# Placeholder macro written by tools/chip_assembly/macros.py
# kind: analog_pma; S81 SerDes PMA RX half (modelled analog, ot_s81_pma_bm LAT 4 behaviour)
VERSION 5.7 ;
BUSBITCHARS "[]" ;
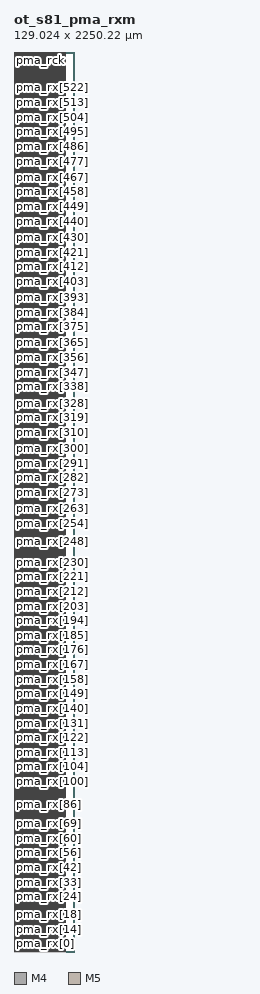
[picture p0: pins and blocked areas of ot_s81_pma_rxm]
MACRO ot_s81_pma_rxm
  FOREIGN ot_s81_pma_rxm 0 0 ;
  SYMMETRY X Y R90 ;
  SIZE 129.024 BY 2250.216 ;
  CLASS BLOCK ;
  PIN pma_rck
    DIRECTION INPUT ;
    USE SIGNAL ;
    SHAPE ABUTMENT ;
    PORT
      LAYER M4 ;
      RECT 0.000 2240.208 0.192 2240.232 ;
    END
  END pma_rck
  PIN pma_rx[0]
    DIRECTION INPUT ;
    USE SIGNAL ;
    SHAPE ABUTMENT ;
    PORT
      LAYER M4 ;
      RECT 0.000 20.496 0.192 20.520 ;
    END
  END pma_rx[0]
  PIN pma_rx[1]
    DIRECTION INPUT ;
    USE SIGNAL ;
    SHAPE ABUTMENT ;
    PORT
      LAYER M4 ;
      RECT 0.000 24.528 0.192 24.552 ;
    END
  END pma_rx[1]
  PIN pma_rx[2]
    DIRECTION INPUT ;
    USE SIGNAL ;
    SHAPE ABUTMENT ;
    PORT
      LAYER M4 ;
      RECT 0.000 28.608 0.192 28.632 ;
    END
  END pma_rx[2]
  PIN pma_rx[3]
    DIRECTION INPUT ;
    USE SIGNAL ;
    SHAPE ABUTMENT ;
    PORT
      LAYER M4 ;
      RECT 0.000 32.640 0.192 32.664 ;
    END
  END pma_rx[3]
  PIN pma_rx[4]
    DIRECTION INPUT ;
    USE SIGNAL ;
    SHAPE ABUTMENT ;
    PORT
      LAYER M4 ;
      RECT 0.000 36.720 0.192 36.744 ;
    END
  END pma_rx[4]
  PIN pma_rx[5]
    DIRECTION INPUT ;
    USE SIGNAL ;
    SHAPE ABUTMENT ;
    PORT
      LAYER M4 ;
      RECT 0.000 40.800 0.192 40.824 ;
    END
  END pma_rx[5]
  PIN pma_rx[6]
    DIRECTION INPUT ;
    USE SIGNAL ;
    SHAPE ABUTMENT ;
    PORT
      LAYER M4 ;
      RECT 0.000 44.832 0.192 44.856 ;
    END
  END pma_rx[6]
  PIN pma_rx[7]
    DIRECTION INPUT ;
    USE SIGNAL ;
    SHAPE ABUTMENT ;
    PORT
      LAYER M4 ;
      RECT 0.000 48.912 0.192 48.936 ;
    END
  END pma_rx[7]
  PIN pma_rx[8]
    DIRECTION INPUT ;
    USE SIGNAL ;
    SHAPE ABUTMENT ;
    PORT
      LAYER M4 ;
      RECT 0.000 52.944 0.192 52.968 ;
    END
  END pma_rx[8]
  PIN pma_rx[9]
    DIRECTION INPUT ;
    USE SIGNAL ;
    SHAPE ABUTMENT ;
    PORT
      LAYER M4 ;
      RECT 0.000 57.024 0.192 57.048 ;
    END
  END pma_rx[9]
  PIN pma_rx[10]
    DIRECTION INPUT ;
    USE SIGNAL ;
    SHAPE ABUTMENT ;
    PORT
      LAYER M4 ;
      RECT 0.000 61.104 0.192 61.128 ;
    END
  END pma_rx[10]
  PIN pma_rx[11]
    DIRECTION INPUT ;
    USE SIGNAL ;
    SHAPE ABUTMENT ;
    PORT
      LAYER M4 ;
      RECT 0.000 65.136 0.192 65.160 ;
    END
  END pma_rx[11]
  PIN pma_rx[12]
    DIRECTION INPUT ;
    USE SIGNAL ;
    SHAPE ABUTMENT ;
    PORT
      LAYER M4 ;
      RECT 0.000 69.216 0.192 69.240 ;
    END
  END pma_rx[12]
  PIN pma_rx[13]
    DIRECTION INPUT ;
    USE SIGNAL ;
    SHAPE ABUTMENT ;
    PORT
      LAYER M4 ;
      RECT 0.000 73.248 0.192 73.272 ;
    END
  END pma_rx[13]
  PIN pma_rx[14]
    DIRECTION INPUT ;
    USE SIGNAL ;
    SHAPE ABUTMENT ;
    PORT
      LAYER M4 ;
      RECT 0.000 77.328 0.192 77.352 ;
    END
  END pma_rx[14]
  PIN pma_rx[15]
    DIRECTION INPUT ;
    USE SIGNAL ;
    SHAPE ABUTMENT ;
    PORT
      LAYER M4 ;
      RECT 0.000 81.408 0.192 81.432 ;
    END
  END pma_rx[15]
  PIN pma_rx[16]
    DIRECTION INPUT ;
    USE SIGNAL ;
    SHAPE ABUTMENT ;
    PORT
      LAYER M4 ;
      RECT 0.000 85.440 0.192 85.464 ;
    END
  END pma_rx[16]
  PIN pma_rx[17]
    DIRECTION INPUT ;
    USE SIGNAL ;
    SHAPE ABUTMENT ;
    PORT
      LAYER M4 ;
      RECT 0.000 89.520 0.192 89.544 ;
    END
  END pma_rx[17]
  PIN pma_rx[18]
    DIRECTION INPUT ;
    USE SIGNAL ;
    SHAPE ABUTMENT ;
    PORT
      LAYER M4 ;
      RECT 0.000 93.552 0.192 93.576 ;
    END
  END pma_rx[18]
  PIN pma_rx[19]
    DIRECTION INPUT ;
    USE SIGNAL ;
    SHAPE ABUTMENT ;
    PORT
      LAYER M4 ;
      RECT 0.000 97.632 0.192 97.656 ;
    END
  END pma_rx[19]
  PIN pma_rx[20]
    DIRECTION INPUT ;
    USE SIGNAL ;
    SHAPE ABUTMENT ;
    PORT
      LAYER M4 ;
      RECT 0.000 101.712 0.192 101.736 ;
    END
  END pma_rx[20]
  PIN pma_rx[21]
    DIRECTION INPUT ;
    USE SIGNAL ;
    SHAPE ABUTMENT ;
    PORT
      LAYER M4 ;
      RECT 0.000 105.744 0.192 105.768 ;
    END
  END pma_rx[21]
  PIN pma_rx[22]
    DIRECTION INPUT ;
    USE SIGNAL ;
    SHAPE ABUTMENT ;
    PORT
      LAYER M4 ;
      RECT 0.000 109.824 0.192 109.848 ;
    END
  END pma_rx[22]
  PIN pma_rx[23]
    DIRECTION INPUT ;
    USE SIGNAL ;
    SHAPE ABUTMENT ;
    PORT
      LAYER M4 ;
      RECT 0.000 113.856 0.192 113.880 ;
    END
  END pma_rx[23]
  PIN pma_rx[24]
    DIRECTION INPUT ;
    USE SIGNAL ;
    SHAPE ABUTMENT ;
    PORT
      LAYER M4 ;
      RECT 0.000 117.936 0.192 117.960 ;
    END
  END pma_rx[24]
  PIN pma_rx[25]
    DIRECTION INPUT ;
    USE SIGNAL ;
    SHAPE ABUTMENT ;
    PORT
      LAYER M4 ;
      RECT 0.000 122.016 0.192 122.040 ;
    END
  END pma_rx[25]
  PIN pma_rx[26]
    DIRECTION INPUT ;
    USE SIGNAL ;
    SHAPE ABUTMENT ;
    PORT
      LAYER M4 ;
      RECT 0.000 126.048 0.192 126.072 ;
    END
  END pma_rx[26]
  PIN pma_rx[27]
    DIRECTION INPUT ;
    USE SIGNAL ;
    SHAPE ABUTMENT ;
    PORT
      LAYER M4 ;
      RECT 0.000 130.128 0.192 130.152 ;
    END
  END pma_rx[27]
  PIN pma_rx[28]
    DIRECTION INPUT ;
    USE SIGNAL ;
    SHAPE ABUTMENT ;
    PORT
      LAYER M4 ;
      RECT 0.000 134.160 0.192 134.184 ;
    END
  END pma_rx[28]
  PIN pma_rx[29]
    DIRECTION INPUT ;
    USE SIGNAL ;
    SHAPE ABUTMENT ;
    PORT
      LAYER M4 ;
      RECT 0.000 138.240 0.192 138.264 ;
    END
  END pma_rx[29]
  PIN pma_rx[30]
    DIRECTION INPUT ;
    USE SIGNAL ;
    SHAPE ABUTMENT ;
    PORT
      LAYER M4 ;
      RECT 0.000 142.320 0.192 142.344 ;
    END
  END pma_rx[30]
  PIN pma_rx[31]
    DIRECTION INPUT ;
    USE SIGNAL ;
    SHAPE ABUTMENT ;
    PORT
      LAYER M4 ;
      RECT 0.000 146.352 0.192 146.376 ;
    END
  END pma_rx[31]
  PIN pma_rx[32]
    DIRECTION INPUT ;
    USE SIGNAL ;
    SHAPE ABUTMENT ;
    PORT
      LAYER M4 ;
      RECT 0.000 150.432 0.192 150.456 ;
    END
  END pma_rx[32]
  PIN pma_rx[33]
    DIRECTION INPUT ;
    USE SIGNAL ;
    SHAPE ABUTMENT ;
    PORT
      LAYER M4 ;
      RECT 0.000 154.464 0.192 154.488 ;
    END
  END pma_rx[33]
  PIN pma_rx[34]
    DIRECTION INPUT ;
    USE SIGNAL ;
    SHAPE ABUTMENT ;
    PORT
      LAYER M4 ;
      RECT 0.000 158.544 0.192 158.568 ;
    END
  END pma_rx[34]
  PIN pma_rx[35]
    DIRECTION INPUT ;
    USE SIGNAL ;
    SHAPE ABUTMENT ;
    PORT
      LAYER M4 ;
      RECT 0.000 162.624 0.192 162.648 ;
    END
  END pma_rx[35]
  PIN pma_rx[36]
    DIRECTION INPUT ;
    USE SIGNAL ;
    SHAPE ABUTMENT ;
    PORT
      LAYER M4 ;
      RECT 0.000 166.656 0.192 166.680 ;
    END
  END pma_rx[36]
  PIN pma_rx[37]
    DIRECTION INPUT ;
    USE SIGNAL ;
    SHAPE ABUTMENT ;
    PORT
      LAYER M4 ;
      RECT 0.000 170.736 0.192 170.760 ;
    END
  END pma_rx[37]
  PIN pma_rx[38]
    DIRECTION INPUT ;
    USE SIGNAL ;
    SHAPE ABUTMENT ;
    PORT
      LAYER M4 ;
      RECT 0.000 174.768 0.192 174.792 ;
    END
  END pma_rx[38]
  PIN pma_rx[39]
    DIRECTION INPUT ;
    USE SIGNAL ;
    SHAPE ABUTMENT ;
    PORT
      LAYER M4 ;
      RECT 0.000 178.848 0.192 178.872 ;
    END
  END pma_rx[39]
  PIN pma_rx[40]
    DIRECTION INPUT ;
    USE SIGNAL ;
    SHAPE ABUTMENT ;
    PORT
      LAYER M4 ;
      RECT 0.000 182.928 0.192 182.952 ;
    END
  END pma_rx[40]
  PIN pma_rx[41]
    DIRECTION INPUT ;
    USE SIGNAL ;
    SHAPE ABUTMENT ;
    PORT
      LAYER M4 ;
      RECT 0.000 186.960 0.192 186.984 ;
    END
  END pma_rx[41]
  PIN pma_rx[42]
    DIRECTION INPUT ;
    USE SIGNAL ;
    SHAPE ABUTMENT ;
    PORT
      LAYER M4 ;
      RECT 0.000 191.040 0.192 191.064 ;
    END
  END pma_rx[42]
  PIN pma_rx[43]
    DIRECTION INPUT ;
    USE SIGNAL ;
    SHAPE ABUTMENT ;
    PORT
      LAYER M4 ;
      RECT 0.000 195.120 0.192 195.144 ;
    END
  END pma_rx[43]
  PIN pma_rx[44]
    DIRECTION INPUT ;
    USE SIGNAL ;
    SHAPE ABUTMENT ;
    PORT
      LAYER M4 ;
      RECT 0.000 199.152 0.192 199.176 ;
    END
  END pma_rx[44]
  PIN pma_rx[45]
    DIRECTION INPUT ;
    USE SIGNAL ;
    SHAPE ABUTMENT ;
    PORT
      LAYER M4 ;
      RECT 0.000 203.232 0.192 203.256 ;
    END
  END pma_rx[45]
  PIN pma_rx[46]
    DIRECTION INPUT ;
    USE SIGNAL ;
    SHAPE ABUTMENT ;
    PORT
      LAYER M4 ;
      RECT 0.000 207.264 0.192 207.288 ;
    END
  END pma_rx[46]
  PIN pma_rx[47]
    DIRECTION INPUT ;
    USE SIGNAL ;
    SHAPE ABUTMENT ;
    PORT
      LAYER M4 ;
      RECT 0.000 211.344 0.192 211.368 ;
    END
  END pma_rx[47]
  PIN pma_rx[48]
    DIRECTION INPUT ;
    USE SIGNAL ;
    SHAPE ABUTMENT ;
    PORT
      LAYER M4 ;
      RECT 0.000 215.424 0.192 215.448 ;
    END
  END pma_rx[48]
  PIN pma_rx[49]
    DIRECTION INPUT ;
    USE SIGNAL ;
    SHAPE ABUTMENT ;
    PORT
      LAYER M4 ;
      RECT 0.000 219.456 0.192 219.480 ;
    END
  END pma_rx[49]
  PIN pma_rx[50]
    DIRECTION INPUT ;
    USE SIGNAL ;
    SHAPE ABUTMENT ;
    PORT
      LAYER M4 ;
      RECT 0.000 223.536 0.192 223.560 ;
    END
  END pma_rx[50]
  PIN pma_rx[51]
    DIRECTION INPUT ;
    USE SIGNAL ;
    SHAPE ABUTMENT ;
    PORT
      LAYER M4 ;
      RECT 0.000 227.568 0.192 227.592 ;
    END
  END pma_rx[51]
  PIN pma_rx[52]
    DIRECTION INPUT ;
    USE SIGNAL ;
    SHAPE ABUTMENT ;
    PORT
      LAYER M4 ;
      RECT 0.000 231.648 0.192 231.672 ;
    END
  END pma_rx[52]
  PIN pma_rx[53]
    DIRECTION INPUT ;
    USE SIGNAL ;
    SHAPE ABUTMENT ;
    PORT
      LAYER M4 ;
      RECT 0.000 235.728 0.192 235.752 ;
    END
  END pma_rx[53]
  PIN pma_rx[54]
    DIRECTION INPUT ;
    USE SIGNAL ;
    SHAPE ABUTMENT ;
    PORT
      LAYER M4 ;
      RECT 0.000 239.760 0.192 239.784 ;
    END
  END pma_rx[54]
  PIN pma_rx[55]
    DIRECTION INPUT ;
    USE SIGNAL ;
    SHAPE ABUTMENT ;
    PORT
      LAYER M4 ;
      RECT 0.000 243.840 0.192 243.864 ;
    END
  END pma_rx[55]
  PIN pma_rx[56]
    DIRECTION INPUT ;
    USE SIGNAL ;
    SHAPE ABUTMENT ;
    PORT
      LAYER M4 ;
      RECT 0.000 247.872 0.192 247.896 ;
    END
  END pma_rx[56]
  PIN pma_rx[57]
    DIRECTION INPUT ;
    USE SIGNAL ;
    SHAPE ABUTMENT ;
    PORT
      LAYER M4 ;
      RECT 0.000 251.952 0.192 251.976 ;
    END
  END pma_rx[57]
  PIN pma_rx[58]
    DIRECTION INPUT ;
    USE SIGNAL ;
    SHAPE ABUTMENT ;
    PORT
      LAYER M4 ;
      RECT 0.000 256.032 0.192 256.056 ;
    END
  END pma_rx[58]
  PIN pma_rx[59]
    DIRECTION INPUT ;
    USE SIGNAL ;
    SHAPE ABUTMENT ;
    PORT
      LAYER M4 ;
      RECT 0.000 260.064 0.192 260.088 ;
    END
  END pma_rx[59]
  PIN pma_rx[60]
    DIRECTION INPUT ;
    USE SIGNAL ;
    SHAPE ABUTMENT ;
    PORT
      LAYER M4 ;
      RECT 0.000 264.144 0.192 264.168 ;
    END
  END pma_rx[60]
  PIN pma_rx[61]
    DIRECTION INPUT ;
    USE SIGNAL ;
    SHAPE ABUTMENT ;
    PORT
      LAYER M4 ;
      RECT 0.000 268.176 0.192 268.200 ;
    END
  END pma_rx[61]
  PIN pma_rx[62]
    DIRECTION INPUT ;
    USE SIGNAL ;
    SHAPE ABUTMENT ;
    PORT
      LAYER M4 ;
      RECT 0.000 272.256 0.192 272.280 ;
    END
  END pma_rx[62]
  PIN pma_rx[63]
    DIRECTION INPUT ;
    USE SIGNAL ;
    SHAPE ABUTMENT ;
    PORT
      LAYER M4 ;
      RECT 0.000 276.336 0.192 276.360 ;
    END
  END pma_rx[63]
  PIN pma_rx[64]
    DIRECTION INPUT ;
    USE SIGNAL ;
    SHAPE ABUTMENT ;
    PORT
      LAYER M4 ;
      RECT 0.000 280.368 0.192 280.392 ;
    END
  END pma_rx[64]
  PIN pma_rx[65]
    DIRECTION INPUT ;
    USE SIGNAL ;
    SHAPE ABUTMENT ;
    PORT
      LAYER M4 ;
      RECT 0.000 284.448 0.192 284.472 ;
    END
  END pma_rx[65]
  PIN pma_rx[66]
    DIRECTION INPUT ;
    USE SIGNAL ;
    SHAPE ABUTMENT ;
    PORT
      LAYER M4 ;
      RECT 0.000 288.480 0.192 288.504 ;
    END
  END pma_rx[66]
  PIN pma_rx[67]
    DIRECTION INPUT ;
    USE SIGNAL ;
    SHAPE ABUTMENT ;
    PORT
      LAYER M4 ;
      RECT 0.000 292.560 0.192 292.584 ;
    END
  END pma_rx[67]
  PIN pma_rx[68]
    DIRECTION INPUT ;
    USE SIGNAL ;
    SHAPE ABUTMENT ;
    PORT
      LAYER M4 ;
      RECT 0.000 296.640 0.192 296.664 ;
    END
  END pma_rx[68]
  PIN pma_rx[69]
    DIRECTION INPUT ;
    USE SIGNAL ;
    SHAPE ABUTMENT ;
    PORT
      LAYER M4 ;
      RECT 0.000 300.672 0.192 300.696 ;
    END
  END pma_rx[69]
  PIN pma_rx[70]
    DIRECTION INPUT ;
    USE SIGNAL ;
    SHAPE ABUTMENT ;
    PORT
      LAYER M4 ;
      RECT 0.000 304.752 0.192 304.776 ;
    END
  END pma_rx[70]
  PIN pma_rx[71]
    DIRECTION INPUT ;
    USE SIGNAL ;
    SHAPE ABUTMENT ;
    PORT
      LAYER M4 ;
      RECT 0.000 308.784 0.192 308.808 ;
    END
  END pma_rx[71]
  PIN pma_rx[72]
    DIRECTION INPUT ;
    USE SIGNAL ;
    SHAPE ABUTMENT ;
    PORT
      LAYER M4 ;
      RECT 0.000 312.864 0.192 312.888 ;
    END
  END pma_rx[72]
  PIN pma_rx[73]
    DIRECTION INPUT ;
    USE SIGNAL ;
    SHAPE ABUTMENT ;
    PORT
      LAYER M4 ;
      RECT 0.000 316.944 0.192 316.968 ;
    END
  END pma_rx[73]
  PIN pma_rx[74]
    DIRECTION INPUT ;
    USE SIGNAL ;
    SHAPE ABUTMENT ;
    PORT
      LAYER M4 ;
      RECT 0.000 320.976 0.192 321.000 ;
    END
  END pma_rx[74]
  PIN pma_rx[75]
    DIRECTION INPUT ;
    USE SIGNAL ;
    SHAPE ABUTMENT ;
    PORT
      LAYER M4 ;
      RECT 0.000 325.056 0.192 325.080 ;
    END
  END pma_rx[75]
  PIN pma_rx[76]
    DIRECTION INPUT ;
    USE SIGNAL ;
    SHAPE ABUTMENT ;
    PORT
      LAYER M4 ;
      RECT 0.000 329.088 0.192 329.112 ;
    END
  END pma_rx[76]
  PIN pma_rx[77]
    DIRECTION INPUT ;
    USE SIGNAL ;
    SHAPE ABUTMENT ;
    PORT
      LAYER M4 ;
      RECT 0.000 333.168 0.192 333.192 ;
    END
  END pma_rx[77]
  PIN pma_rx[78]
    DIRECTION INPUT ;
    USE SIGNAL ;
    SHAPE ABUTMENT ;
    PORT
      LAYER M4 ;
      RECT 0.000 337.248 0.192 337.272 ;
    END
  END pma_rx[78]
  PIN pma_rx[79]
    DIRECTION INPUT ;
    USE SIGNAL ;
    SHAPE ABUTMENT ;
    PORT
      LAYER M4 ;
      RECT 0.000 341.280 0.192 341.304 ;
    END
  END pma_rx[79]
  PIN pma_rx[80]
    DIRECTION INPUT ;
    USE SIGNAL ;
    SHAPE ABUTMENT ;
    PORT
      LAYER M4 ;
      RECT 0.000 345.360 0.192 345.384 ;
    END
  END pma_rx[80]
  PIN pma_rx[81]
    DIRECTION INPUT ;
    USE SIGNAL ;
    SHAPE ABUTMENT ;
    PORT
      LAYER M4 ;
      RECT 0.000 349.392 0.192 349.416 ;
    END
  END pma_rx[81]
  PIN pma_rx[82]
    DIRECTION INPUT ;
    USE SIGNAL ;
    SHAPE ABUTMENT ;
    PORT
      LAYER M4 ;
      RECT 0.000 353.472 0.192 353.496 ;
    END
  END pma_rx[82]
  PIN pma_rx[83]
    DIRECTION INPUT ;
    USE SIGNAL ;
    SHAPE ABUTMENT ;
    PORT
      LAYER M4 ;
      RECT 0.000 357.552 0.192 357.576 ;
    END
  END pma_rx[83]
  PIN pma_rx[84]
    DIRECTION INPUT ;
    USE SIGNAL ;
    SHAPE ABUTMENT ;
    PORT
      LAYER M4 ;
      RECT 0.000 361.584 0.192 361.608 ;
    END
  END pma_rx[84]
  PIN pma_rx[85]
    DIRECTION INPUT ;
    USE SIGNAL ;
    SHAPE ABUTMENT ;
    PORT
      LAYER M4 ;
      RECT 0.000 365.664 0.192 365.688 ;
    END
  END pma_rx[85]
  PIN pma_rx[86]
    DIRECTION INPUT ;
    USE SIGNAL ;
    SHAPE ABUTMENT ;
    PORT
      LAYER M4 ;
      RECT 0.000 369.744 0.192 369.768 ;
    END
  END pma_rx[86]
  PIN pma_rx[87]
    DIRECTION INPUT ;
    USE SIGNAL ;
    SHAPE ABUTMENT ;
    PORT
      LAYER M4 ;
      RECT 0.000 373.776 0.192 373.800 ;
    END
  END pma_rx[87]
  PIN pma_rx[88]
    DIRECTION INPUT ;
    USE SIGNAL ;
    SHAPE ABUTMENT ;
    PORT
      LAYER M4 ;
      RECT 0.000 377.856 0.192 377.880 ;
    END
  END pma_rx[88]
  PIN pma_rx[89]
    DIRECTION INPUT ;
    USE SIGNAL ;
    SHAPE ABUTMENT ;
    PORT
      LAYER M4 ;
      RECT 0.000 381.888 0.192 381.912 ;
    END
  END pma_rx[89]
  PIN pma_rx[90]
    DIRECTION INPUT ;
    USE SIGNAL ;
    SHAPE ABUTMENT ;
    PORT
      LAYER M4 ;
      RECT 0.000 385.968 0.192 385.992 ;
    END
  END pma_rx[90]
  PIN pma_rx[91]
    DIRECTION INPUT ;
    USE SIGNAL ;
    SHAPE ABUTMENT ;
    PORT
      LAYER M4 ;
      RECT 0.000 390.048 0.192 390.072 ;
    END
  END pma_rx[91]
  PIN pma_rx[92]
    DIRECTION INPUT ;
    USE SIGNAL ;
    SHAPE ABUTMENT ;
    PORT
      LAYER M4 ;
      RECT 0.000 394.080 0.192 394.104 ;
    END
  END pma_rx[92]
  PIN pma_rx[93]
    DIRECTION INPUT ;
    USE SIGNAL ;
    SHAPE ABUTMENT ;
    PORT
      LAYER M4 ;
      RECT 0.000 398.160 0.192 398.184 ;
    END
  END pma_rx[93]
  PIN pma_rx[94]
    DIRECTION INPUT ;
    USE SIGNAL ;
    SHAPE ABUTMENT ;
    PORT
      LAYER M4 ;
      RECT 0.000 402.192 0.192 402.216 ;
    END
  END pma_rx[94]
  PIN pma_rx[95]
    DIRECTION INPUT ;
    USE SIGNAL ;
    SHAPE ABUTMENT ;
    PORT
      LAYER M4 ;
      RECT 0.000 406.272 0.192 406.296 ;
    END
  END pma_rx[95]
  PIN pma_rx[96]
    DIRECTION INPUT ;
    USE SIGNAL ;
    SHAPE ABUTMENT ;
    PORT
      LAYER M4 ;
      RECT 0.000 410.352 0.192 410.376 ;
    END
  END pma_rx[96]
  PIN pma_rx[97]
    DIRECTION INPUT ;
    USE SIGNAL ;
    SHAPE ABUTMENT ;
    PORT
      LAYER M4 ;
      RECT 0.000 414.384 0.192 414.408 ;
    END
  END pma_rx[97]
  PIN pma_rx[98]
    DIRECTION INPUT ;
    USE SIGNAL ;
    SHAPE ABUTMENT ;
    PORT
      LAYER M4 ;
      RECT 0.000 418.464 0.192 418.488 ;
    END
  END pma_rx[98]
  PIN pma_rx[99]
    DIRECTION INPUT ;
    USE SIGNAL ;
    SHAPE ABUTMENT ;
    PORT
      LAYER M4 ;
      RECT 0.000 422.496 0.192 422.520 ;
    END
  END pma_rx[99]
  PIN pma_rx[100]
    DIRECTION INPUT ;
    USE SIGNAL ;
    SHAPE ABUTMENT ;
    PORT
      LAYER M4 ;
      RECT 0.000 426.576 0.192 426.600 ;
    END
  END pma_rx[100]
  PIN pma_rx[101]
    DIRECTION INPUT ;
    USE SIGNAL ;
    SHAPE ABUTMENT ;
    PORT
      LAYER M4 ;
      RECT 0.000 430.656 0.192 430.680 ;
    END
  END pma_rx[101]
  PIN pma_rx[102]
    DIRECTION INPUT ;
    USE SIGNAL ;
    SHAPE ABUTMENT ;
    PORT
      LAYER M4 ;
      RECT 0.000 434.688 0.192 434.712 ;
    END
  END pma_rx[102]
  PIN pma_rx[103]
    DIRECTION INPUT ;
    USE SIGNAL ;
    SHAPE ABUTMENT ;
    PORT
      LAYER M4 ;
      RECT 0.000 438.768 0.192 438.792 ;
    END
  END pma_rx[103]
  PIN pma_rx[104]
    DIRECTION INPUT ;
    USE SIGNAL ;
    SHAPE ABUTMENT ;
    PORT
      LAYER M4 ;
      RECT 0.000 442.800 0.192 442.824 ;
    END
  END pma_rx[104]
  PIN pma_rx[105]
    DIRECTION INPUT ;
    USE SIGNAL ;
    SHAPE ABUTMENT ;
    PORT
      LAYER M4 ;
      RECT 0.000 446.880 0.192 446.904 ;
    END
  END pma_rx[105]
  PIN pma_rx[106]
    DIRECTION INPUT ;
    USE SIGNAL ;
    SHAPE ABUTMENT ;
    PORT
      LAYER M4 ;
      RECT 0.000 450.960 0.192 450.984 ;
    END
  END pma_rx[106]
  PIN pma_rx[107]
    DIRECTION INPUT ;
    USE SIGNAL ;
    SHAPE ABUTMENT ;
    PORT
      LAYER M4 ;
      RECT 0.000 454.992 0.192 455.016 ;
    END
  END pma_rx[107]
  PIN pma_rx[108]
    DIRECTION INPUT ;
    USE SIGNAL ;
    SHAPE ABUTMENT ;
    PORT
      LAYER M4 ;
      RECT 0.000 459.072 0.192 459.096 ;
    END
  END pma_rx[108]
  PIN pma_rx[109]
    DIRECTION INPUT ;
    USE SIGNAL ;
    SHAPE ABUTMENT ;
    PORT
      LAYER M4 ;
      RECT 0.000 463.104 0.192 463.128 ;
    END
  END pma_rx[109]
  PIN pma_rx[110]
    DIRECTION INPUT ;
    USE SIGNAL ;
    SHAPE ABUTMENT ;
    PORT
      LAYER M4 ;
      RECT 0.000 467.184 0.192 467.208 ;
    END
  END pma_rx[110]
  PIN pma_rx[111]
    DIRECTION INPUT ;
    USE SIGNAL ;
    SHAPE ABUTMENT ;
    PORT
      LAYER M4 ;
      RECT 0.000 471.264 0.192 471.288 ;
    END
  END pma_rx[111]
  PIN pma_rx[112]
    DIRECTION INPUT ;
    USE SIGNAL ;
    SHAPE ABUTMENT ;
    PORT
      LAYER M4 ;
      RECT 0.000 475.296 0.192 475.320 ;
    END
  END pma_rx[112]
  PIN pma_rx[113]
    DIRECTION INPUT ;
    USE SIGNAL ;
    SHAPE ABUTMENT ;
    PORT
      LAYER M4 ;
      RECT 0.000 479.376 0.192 479.400 ;
    END
  END pma_rx[113]
  PIN pma_rx[114]
    DIRECTION INPUT ;
    USE SIGNAL ;
    SHAPE ABUTMENT ;
    PORT
      LAYER M4 ;
      RECT 0.000 483.408 0.192 483.432 ;
    END
  END pma_rx[114]
  PIN pma_rx[115]
    DIRECTION INPUT ;
    USE SIGNAL ;
    SHAPE ABUTMENT ;
    PORT
      LAYER M4 ;
      RECT 0.000 487.488 0.192 487.512 ;
    END
  END pma_rx[115]
  PIN pma_rx[116]
    DIRECTION INPUT ;
    USE SIGNAL ;
    SHAPE ABUTMENT ;
    PORT
      LAYER M4 ;
      RECT 0.000 491.568 0.192 491.592 ;
    END
  END pma_rx[116]
  PIN pma_rx[117]
    DIRECTION INPUT ;
    USE SIGNAL ;
    SHAPE ABUTMENT ;
    PORT
      LAYER M4 ;
      RECT 0.000 495.600 0.192 495.624 ;
    END
  END pma_rx[117]
  PIN pma_rx[118]
    DIRECTION INPUT ;
    USE SIGNAL ;
    SHAPE ABUTMENT ;
    PORT
      LAYER M4 ;
      RECT 0.000 499.680 0.192 499.704 ;
    END
  END pma_rx[118]
  PIN pma_rx[119]
    DIRECTION INPUT ;
    USE SIGNAL ;
    SHAPE ABUTMENT ;
    PORT
      LAYER M4 ;
      RECT 0.000 503.712 0.192 503.736 ;
    END
  END pma_rx[119]
  PIN pma_rx[120]
    DIRECTION INPUT ;
    USE SIGNAL ;
    SHAPE ABUTMENT ;
    PORT
      LAYER M4 ;
      RECT 0.000 507.792 0.192 507.816 ;
    END
  END pma_rx[120]
  PIN pma_rx[121]
    DIRECTION INPUT ;
    USE SIGNAL ;
    SHAPE ABUTMENT ;
    PORT
      LAYER M4 ;
      RECT 0.000 511.872 0.192 511.896 ;
    END
  END pma_rx[121]
  PIN pma_rx[122]
    DIRECTION INPUT ;
    USE SIGNAL ;
    SHAPE ABUTMENT ;
    PORT
      LAYER M4 ;
      RECT 0.000 515.904 0.192 515.928 ;
    END
  END pma_rx[122]
  PIN pma_rx[123]
    DIRECTION INPUT ;
    USE SIGNAL ;
    SHAPE ABUTMENT ;
    PORT
      LAYER M4 ;
      RECT 0.000 519.984 0.192 520.008 ;
    END
  END pma_rx[123]
  PIN pma_rx[124]
    DIRECTION INPUT ;
    USE SIGNAL ;
    SHAPE ABUTMENT ;
    PORT
      LAYER M4 ;
      RECT 0.000 524.016 0.192 524.040 ;
    END
  END pma_rx[124]
  PIN pma_rx[125]
    DIRECTION INPUT ;
    USE SIGNAL ;
    SHAPE ABUTMENT ;
    PORT
      LAYER M4 ;
      RECT 0.000 528.096 0.192 528.120 ;
    END
  END pma_rx[125]
  PIN pma_rx[126]
    DIRECTION INPUT ;
    USE SIGNAL ;
    SHAPE ABUTMENT ;
    PORT
      LAYER M4 ;
      RECT 0.000 532.176 0.192 532.200 ;
    END
  END pma_rx[126]
  PIN pma_rx[127]
    DIRECTION INPUT ;
    USE SIGNAL ;
    SHAPE ABUTMENT ;
    PORT
      LAYER M4 ;
      RECT 0.000 536.208 0.192 536.232 ;
    END
  END pma_rx[127]
  PIN pma_rx[128]
    DIRECTION INPUT ;
    USE SIGNAL ;
    SHAPE ABUTMENT ;
    PORT
      LAYER M4 ;
      RECT 0.000 540.288 0.192 540.312 ;
    END
  END pma_rx[128]
  PIN pma_rx[129]
    DIRECTION INPUT ;
    USE SIGNAL ;
    SHAPE ABUTMENT ;
    PORT
      LAYER M4 ;
      RECT 0.000 544.368 0.192 544.392 ;
    END
  END pma_rx[129]
  PIN pma_rx[130]
    DIRECTION INPUT ;
    USE SIGNAL ;
    SHAPE ABUTMENT ;
    PORT
      LAYER M4 ;
      RECT 0.000 548.400 0.192 548.424 ;
    END
  END pma_rx[130]
  PIN pma_rx[131]
    DIRECTION INPUT ;
    USE SIGNAL ;
    SHAPE ABUTMENT ;
    PORT
      LAYER M4 ;
      RECT 0.000 552.480 0.192 552.504 ;
    END
  END pma_rx[131]
  PIN pma_rx[132]
    DIRECTION INPUT ;
    USE SIGNAL ;
    SHAPE ABUTMENT ;
    PORT
      LAYER M4 ;
      RECT 0.000 556.512 0.192 556.536 ;
    END
  END pma_rx[132]
  PIN pma_rx[133]
    DIRECTION INPUT ;
    USE SIGNAL ;
    SHAPE ABUTMENT ;
    PORT
      LAYER M4 ;
      RECT 0.000 560.592 0.192 560.616 ;
    END
  END pma_rx[133]
  PIN pma_rx[134]
    DIRECTION INPUT ;
    USE SIGNAL ;
    SHAPE ABUTMENT ;
    PORT
      LAYER M4 ;
      RECT 0.000 564.672 0.192 564.696 ;
    END
  END pma_rx[134]
  PIN pma_rx[135]
    DIRECTION INPUT ;
    USE SIGNAL ;
    SHAPE ABUTMENT ;
    PORT
      LAYER M4 ;
      RECT 0.000 568.704 0.192 568.728 ;
    END
  END pma_rx[135]
  PIN pma_rx[136]
    DIRECTION INPUT ;
    USE SIGNAL ;
    SHAPE ABUTMENT ;
    PORT
      LAYER M4 ;
      RECT 0.000 572.784 0.192 572.808 ;
    END
  END pma_rx[136]
  PIN pma_rx[137]
    DIRECTION INPUT ;
    USE SIGNAL ;
    SHAPE ABUTMENT ;
    PORT
      LAYER M4 ;
      RECT 0.000 576.816 0.192 576.840 ;
    END
  END pma_rx[137]
  PIN pma_rx[138]
    DIRECTION INPUT ;
    USE SIGNAL ;
    SHAPE ABUTMENT ;
    PORT
      LAYER M4 ;
      RECT 0.000 580.896 0.192 580.920 ;
    END
  END pma_rx[138]
  PIN pma_rx[139]
    DIRECTION INPUT ;
    USE SIGNAL ;
    SHAPE ABUTMENT ;
    PORT
      LAYER M4 ;
      RECT 0.000 584.976 0.192 585.000 ;
    END
  END pma_rx[139]
  PIN pma_rx[140]
    DIRECTION INPUT ;
    USE SIGNAL ;
    SHAPE ABUTMENT ;
    PORT
      LAYER M4 ;
      RECT 0.000 589.008 0.192 589.032 ;
    END
  END pma_rx[140]
  PIN pma_rx[141]
    DIRECTION INPUT ;
    USE SIGNAL ;
    SHAPE ABUTMENT ;
    PORT
      LAYER M4 ;
      RECT 0.000 593.088 0.192 593.112 ;
    END
  END pma_rx[141]
  PIN pma_rx[142]
    DIRECTION INPUT ;
    USE SIGNAL ;
    SHAPE ABUTMENT ;
    PORT
      LAYER M4 ;
      RECT 0.000 597.120 0.192 597.144 ;
    END
  END pma_rx[142]
  PIN pma_rx[143]
    DIRECTION INPUT ;
    USE SIGNAL ;
    SHAPE ABUTMENT ;
    PORT
      LAYER M4 ;
      RECT 0.000 601.200 0.192 601.224 ;
    END
  END pma_rx[143]
  PIN pma_rx[144]
    DIRECTION INPUT ;
    USE SIGNAL ;
    SHAPE ABUTMENT ;
    PORT
      LAYER M4 ;
      RECT 0.000 605.280 0.192 605.304 ;
    END
  END pma_rx[144]
  PIN pma_rx[145]
    DIRECTION INPUT ;
    USE SIGNAL ;
    SHAPE ABUTMENT ;
    PORT
      LAYER M4 ;
      RECT 0.000 609.312 0.192 609.336 ;
    END
  END pma_rx[145]
  PIN pma_rx[146]
    DIRECTION INPUT ;
    USE SIGNAL ;
    SHAPE ABUTMENT ;
    PORT
      LAYER M4 ;
      RECT 0.000 613.392 0.192 613.416 ;
    END
  END pma_rx[146]
  PIN pma_rx[147]
    DIRECTION INPUT ;
    USE SIGNAL ;
    SHAPE ABUTMENT ;
    PORT
      LAYER M4 ;
      RECT 0.000 617.424 0.192 617.448 ;
    END
  END pma_rx[147]
  PIN pma_rx[148]
    DIRECTION INPUT ;
    USE SIGNAL ;
    SHAPE ABUTMENT ;
    PORT
      LAYER M4 ;
      RECT 0.000 621.504 0.192 621.528 ;
    END
  END pma_rx[148]
  PIN pma_rx[149]
    DIRECTION INPUT ;
    USE SIGNAL ;
    SHAPE ABUTMENT ;
    PORT
      LAYER M4 ;
      RECT 0.000 625.584 0.192 625.608 ;
    END
  END pma_rx[149]
  PIN pma_rx[150]
    DIRECTION INPUT ;
    USE SIGNAL ;
    SHAPE ABUTMENT ;
    PORT
      LAYER M4 ;
      RECT 0.000 629.616 0.192 629.640 ;
    END
  END pma_rx[150]
  PIN pma_rx[151]
    DIRECTION INPUT ;
    USE SIGNAL ;
    SHAPE ABUTMENT ;
    PORT
      LAYER M4 ;
      RECT 0.000 633.696 0.192 633.720 ;
    END
  END pma_rx[151]
  PIN pma_rx[152]
    DIRECTION INPUT ;
    USE SIGNAL ;
    SHAPE ABUTMENT ;
    PORT
      LAYER M4 ;
      RECT 0.000 637.728 0.192 637.752 ;
    END
  END pma_rx[152]
  PIN pma_rx[153]
    DIRECTION INPUT ;
    USE SIGNAL ;
    SHAPE ABUTMENT ;
    PORT
      LAYER M4 ;
      RECT 0.000 641.808 0.192 641.832 ;
    END
  END pma_rx[153]
  PIN pma_rx[154]
    DIRECTION INPUT ;
    USE SIGNAL ;
    SHAPE ABUTMENT ;
    PORT
      LAYER M4 ;
      RECT 0.000 645.888 0.192 645.912 ;
    END
  END pma_rx[154]
  PIN pma_rx[155]
    DIRECTION INPUT ;
    USE SIGNAL ;
    SHAPE ABUTMENT ;
    PORT
      LAYER M4 ;
      RECT 0.000 649.920 0.192 649.944 ;
    END
  END pma_rx[155]
  PIN pma_rx[156]
    DIRECTION INPUT ;
    USE SIGNAL ;
    SHAPE ABUTMENT ;
    PORT
      LAYER M4 ;
      RECT 0.000 654.000 0.192 654.024 ;
    END
  END pma_rx[156]
  PIN pma_rx[157]
    DIRECTION INPUT ;
    USE SIGNAL ;
    SHAPE ABUTMENT ;
    PORT
      LAYER M4 ;
      RECT 0.000 658.032 0.192 658.056 ;
    END
  END pma_rx[157]
  PIN pma_rx[158]
    DIRECTION INPUT ;
    USE SIGNAL ;
    SHAPE ABUTMENT ;
    PORT
      LAYER M4 ;
      RECT 0.000 662.112 0.192 662.136 ;
    END
  END pma_rx[158]
  PIN pma_rx[159]
    DIRECTION INPUT ;
    USE SIGNAL ;
    SHAPE ABUTMENT ;
    PORT
      LAYER M4 ;
      RECT 0.000 666.192 0.192 666.216 ;
    END
  END pma_rx[159]
  PIN pma_rx[160]
    DIRECTION INPUT ;
    USE SIGNAL ;
    SHAPE ABUTMENT ;
    PORT
      LAYER M4 ;
      RECT 0.000 670.224 0.192 670.248 ;
    END
  END pma_rx[160]
  PIN pma_rx[161]
    DIRECTION INPUT ;
    USE SIGNAL ;
    SHAPE ABUTMENT ;
    PORT
      LAYER M4 ;
      RECT 0.000 674.304 0.192 674.328 ;
    END
  END pma_rx[161]
  PIN pma_rx[162]
    DIRECTION INPUT ;
    USE SIGNAL ;
    SHAPE ABUTMENT ;
    PORT
      LAYER M4 ;
      RECT 0.000 678.336 0.192 678.360 ;
    END
  END pma_rx[162]
  PIN pma_rx[163]
    DIRECTION INPUT ;
    USE SIGNAL ;
    SHAPE ABUTMENT ;
    PORT
      LAYER M4 ;
      RECT 0.000 682.416 0.192 682.440 ;
    END
  END pma_rx[163]
  PIN pma_rx[164]
    DIRECTION INPUT ;
    USE SIGNAL ;
    SHAPE ABUTMENT ;
    PORT
      LAYER M4 ;
      RECT 0.000 686.496 0.192 686.520 ;
    END
  END pma_rx[164]
  PIN pma_rx[165]
    DIRECTION INPUT ;
    USE SIGNAL ;
    SHAPE ABUTMENT ;
    PORT
      LAYER M4 ;
      RECT 0.000 690.528 0.192 690.552 ;
    END
  END pma_rx[165]
  PIN pma_rx[166]
    DIRECTION INPUT ;
    USE SIGNAL ;
    SHAPE ABUTMENT ;
    PORT
      LAYER M4 ;
      RECT 0.000 694.608 0.192 694.632 ;
    END
  END pma_rx[166]
  PIN pma_rx[167]
    DIRECTION INPUT ;
    USE SIGNAL ;
    SHAPE ABUTMENT ;
    PORT
      LAYER M4 ;
      RECT 0.000 698.640 0.192 698.664 ;
    END
  END pma_rx[167]
  PIN pma_rx[168]
    DIRECTION INPUT ;
    USE SIGNAL ;
    SHAPE ABUTMENT ;
    PORT
      LAYER M4 ;
      RECT 0.000 702.720 0.192 702.744 ;
    END
  END pma_rx[168]
  PIN pma_rx[169]
    DIRECTION INPUT ;
    USE SIGNAL ;
    SHAPE ABUTMENT ;
    PORT
      LAYER M4 ;
      RECT 0.000 706.800 0.192 706.824 ;
    END
  END pma_rx[169]
  PIN pma_rx[170]
    DIRECTION INPUT ;
    USE SIGNAL ;
    SHAPE ABUTMENT ;
    PORT
      LAYER M4 ;
      RECT 0.000 710.832 0.192 710.856 ;
    END
  END pma_rx[170]
  PIN pma_rx[171]
    DIRECTION INPUT ;
    USE SIGNAL ;
    SHAPE ABUTMENT ;
    PORT
      LAYER M4 ;
      RECT 0.000 714.912 0.192 714.936 ;
    END
  END pma_rx[171]
  PIN pma_rx[172]
    DIRECTION INPUT ;
    USE SIGNAL ;
    SHAPE ABUTMENT ;
    PORT
      LAYER M4 ;
      RECT 0.000 718.992 0.192 719.016 ;
    END
  END pma_rx[172]
  PIN pma_rx[173]
    DIRECTION INPUT ;
    USE SIGNAL ;
    SHAPE ABUTMENT ;
    PORT
      LAYER M4 ;
      RECT 0.000 723.024 0.192 723.048 ;
    END
  END pma_rx[173]
  PIN pma_rx[174]
    DIRECTION INPUT ;
    USE SIGNAL ;
    SHAPE ABUTMENT ;
    PORT
      LAYER M4 ;
      RECT 0.000 727.104 0.192 727.128 ;
    END
  END pma_rx[174]
  PIN pma_rx[175]
    DIRECTION INPUT ;
    USE SIGNAL ;
    SHAPE ABUTMENT ;
    PORT
      LAYER M4 ;
      RECT 0.000 731.136 0.192 731.160 ;
    END
  END pma_rx[175]
  PIN pma_rx[176]
    DIRECTION INPUT ;
    USE SIGNAL ;
    SHAPE ABUTMENT ;
    PORT
      LAYER M4 ;
      RECT 0.000 735.216 0.192 735.240 ;
    END
  END pma_rx[176]
  PIN pma_rx[177]
    DIRECTION INPUT ;
    USE SIGNAL ;
    SHAPE ABUTMENT ;
    PORT
      LAYER M4 ;
      RECT 0.000 739.296 0.192 739.320 ;
    END
  END pma_rx[177]
  PIN pma_rx[178]
    DIRECTION INPUT ;
    USE SIGNAL ;
    SHAPE ABUTMENT ;
    PORT
      LAYER M4 ;
      RECT 0.000 743.328 0.192 743.352 ;
    END
  END pma_rx[178]
  PIN pma_rx[179]
    DIRECTION INPUT ;
    USE SIGNAL ;
    SHAPE ABUTMENT ;
    PORT
      LAYER M4 ;
      RECT 0.000 747.408 0.192 747.432 ;
    END
  END pma_rx[179]
  PIN pma_rx[180]
    DIRECTION INPUT ;
    USE SIGNAL ;
    SHAPE ABUTMENT ;
    PORT
      LAYER M4 ;
      RECT 0.000 751.440 0.192 751.464 ;
    END
  END pma_rx[180]
  PIN pma_rx[181]
    DIRECTION INPUT ;
    USE SIGNAL ;
    SHAPE ABUTMENT ;
    PORT
      LAYER M4 ;
      RECT 0.000 755.520 0.192 755.544 ;
    END
  END pma_rx[181]
  PIN pma_rx[182]
    DIRECTION INPUT ;
    USE SIGNAL ;
    SHAPE ABUTMENT ;
    PORT
      LAYER M4 ;
      RECT 0.000 759.600 0.192 759.624 ;
    END
  END pma_rx[182]
  PIN pma_rx[183]
    DIRECTION INPUT ;
    USE SIGNAL ;
    SHAPE ABUTMENT ;
    PORT
      LAYER M4 ;
      RECT 0.000 763.632 0.192 763.656 ;
    END
  END pma_rx[183]
  PIN pma_rx[184]
    DIRECTION INPUT ;
    USE SIGNAL ;
    SHAPE ABUTMENT ;
    PORT
      LAYER M4 ;
      RECT 0.000 767.712 0.192 767.736 ;
    END
  END pma_rx[184]
  PIN pma_rx[185]
    DIRECTION INPUT ;
    USE SIGNAL ;
    SHAPE ABUTMENT ;
    PORT
      LAYER M4 ;
      RECT 0.000 771.744 0.192 771.768 ;
    END
  END pma_rx[185]
  PIN pma_rx[186]
    DIRECTION INPUT ;
    USE SIGNAL ;
    SHAPE ABUTMENT ;
    PORT
      LAYER M4 ;
      RECT 0.000 775.824 0.192 775.848 ;
    END
  END pma_rx[186]
  PIN pma_rx[187]
    DIRECTION INPUT ;
    USE SIGNAL ;
    SHAPE ABUTMENT ;
    PORT
      LAYER M4 ;
      RECT 0.000 779.904 0.192 779.928 ;
    END
  END pma_rx[187]
  PIN pma_rx[188]
    DIRECTION INPUT ;
    USE SIGNAL ;
    SHAPE ABUTMENT ;
    PORT
      LAYER M4 ;
      RECT 0.000 783.936 0.192 783.960 ;
    END
  END pma_rx[188]
  PIN pma_rx[189]
    DIRECTION INPUT ;
    USE SIGNAL ;
    SHAPE ABUTMENT ;
    PORT
      LAYER M4 ;
      RECT 0.000 788.016 0.192 788.040 ;
    END
  END pma_rx[189]
  PIN pma_rx[190]
    DIRECTION INPUT ;
    USE SIGNAL ;
    SHAPE ABUTMENT ;
    PORT
      LAYER M4 ;
      RECT 0.000 792.048 0.192 792.072 ;
    END
  END pma_rx[190]
  PIN pma_rx[191]
    DIRECTION INPUT ;
    USE SIGNAL ;
    SHAPE ABUTMENT ;
    PORT
      LAYER M4 ;
      RECT 0.000 796.128 0.192 796.152 ;
    END
  END pma_rx[191]
  PIN pma_rx[192]
    DIRECTION INPUT ;
    USE SIGNAL ;
    SHAPE ABUTMENT ;
    PORT
      LAYER M4 ;
      RECT 0.000 800.208 0.192 800.232 ;
    END
  END pma_rx[192]
  PIN pma_rx[193]
    DIRECTION INPUT ;
    USE SIGNAL ;
    SHAPE ABUTMENT ;
    PORT
      LAYER M4 ;
      RECT 0.000 804.240 0.192 804.264 ;
    END
  END pma_rx[193]
  PIN pma_rx[194]
    DIRECTION INPUT ;
    USE SIGNAL ;
    SHAPE ABUTMENT ;
    PORT
      LAYER M4 ;
      RECT 0.000 808.320 0.192 808.344 ;
    END
  END pma_rx[194]
  PIN pma_rx[195]
    DIRECTION INPUT ;
    USE SIGNAL ;
    SHAPE ABUTMENT ;
    PORT
      LAYER M4 ;
      RECT 0.000 812.352 0.192 812.376 ;
    END
  END pma_rx[195]
  PIN pma_rx[196]
    DIRECTION INPUT ;
    USE SIGNAL ;
    SHAPE ABUTMENT ;
    PORT
      LAYER M4 ;
      RECT 0.000 816.432 0.192 816.456 ;
    END
  END pma_rx[196]
  PIN pma_rx[197]
    DIRECTION INPUT ;
    USE SIGNAL ;
    SHAPE ABUTMENT ;
    PORT
      LAYER M4 ;
      RECT 0.000 820.512 0.192 820.536 ;
    END
  END pma_rx[197]
  PIN pma_rx[198]
    DIRECTION INPUT ;
    USE SIGNAL ;
    SHAPE ABUTMENT ;
    PORT
      LAYER M4 ;
      RECT 0.000 824.544 0.192 824.568 ;
    END
  END pma_rx[198]
  PIN pma_rx[199]
    DIRECTION INPUT ;
    USE SIGNAL ;
    SHAPE ABUTMENT ;
    PORT
      LAYER M4 ;
      RECT 0.000 828.624 0.192 828.648 ;
    END
  END pma_rx[199]
  PIN pma_rx[200]
    DIRECTION INPUT ;
    USE SIGNAL ;
    SHAPE ABUTMENT ;
    PORT
      LAYER M4 ;
      RECT 0.000 832.656 0.192 832.680 ;
    END
  END pma_rx[200]
  PIN pma_rx[201]
    DIRECTION INPUT ;
    USE SIGNAL ;
    SHAPE ABUTMENT ;
    PORT
      LAYER M4 ;
      RECT 0.000 836.736 0.192 836.760 ;
    END
  END pma_rx[201]
  PIN pma_rx[202]
    DIRECTION INPUT ;
    USE SIGNAL ;
    SHAPE ABUTMENT ;
    PORT
      LAYER M4 ;
      RECT 0.000 840.816 0.192 840.840 ;
    END
  END pma_rx[202]
  PIN pma_rx[203]
    DIRECTION INPUT ;
    USE SIGNAL ;
    SHAPE ABUTMENT ;
    PORT
      LAYER M4 ;
      RECT 0.000 844.848 0.192 844.872 ;
    END
  END pma_rx[203]
  PIN pma_rx[204]
    DIRECTION INPUT ;
    USE SIGNAL ;
    SHAPE ABUTMENT ;
    PORT
      LAYER M4 ;
      RECT 0.000 848.928 0.192 848.952 ;
    END
  END pma_rx[204]
  PIN pma_rx[205]
    DIRECTION INPUT ;
    USE SIGNAL ;
    SHAPE ABUTMENT ;
    PORT
      LAYER M4 ;
      RECT 0.000 852.960 0.192 852.984 ;
    END
  END pma_rx[205]
  PIN pma_rx[206]
    DIRECTION INPUT ;
    USE SIGNAL ;
    SHAPE ABUTMENT ;
    PORT
      LAYER M4 ;
      RECT 0.000 857.040 0.192 857.064 ;
    END
  END pma_rx[206]
  PIN pma_rx[207]
    DIRECTION INPUT ;
    USE SIGNAL ;
    SHAPE ABUTMENT ;
    PORT
      LAYER M4 ;
      RECT 0.000 861.120 0.192 861.144 ;
    END
  END pma_rx[207]
  PIN pma_rx[208]
    DIRECTION INPUT ;
    USE SIGNAL ;
    SHAPE ABUTMENT ;
    PORT
      LAYER M4 ;
      RECT 0.000 865.152 0.192 865.176 ;
    END
  END pma_rx[208]
  PIN pma_rx[209]
    DIRECTION INPUT ;
    USE SIGNAL ;
    SHAPE ABUTMENT ;
    PORT
      LAYER M4 ;
      RECT 0.000 869.232 0.192 869.256 ;
    END
  END pma_rx[209]
  PIN pma_rx[210]
    DIRECTION INPUT ;
    USE SIGNAL ;
    SHAPE ABUTMENT ;
    PORT
      LAYER M4 ;
      RECT 0.000 873.312 0.192 873.336 ;
    END
  END pma_rx[210]
  PIN pma_rx[211]
    DIRECTION INPUT ;
    USE SIGNAL ;
    SHAPE ABUTMENT ;
    PORT
      LAYER M4 ;
      RECT 0.000 877.344 0.192 877.368 ;
    END
  END pma_rx[211]
  PIN pma_rx[212]
    DIRECTION INPUT ;
    USE SIGNAL ;
    SHAPE ABUTMENT ;
    PORT
      LAYER M4 ;
      RECT 0.000 881.424 0.192 881.448 ;
    END
  END pma_rx[212]
  PIN pma_rx[213]
    DIRECTION INPUT ;
    USE SIGNAL ;
    SHAPE ABUTMENT ;
    PORT
      LAYER M4 ;
      RECT 0.000 885.456 0.192 885.480 ;
    END
  END pma_rx[213]
  PIN pma_rx[214]
    DIRECTION INPUT ;
    USE SIGNAL ;
    SHAPE ABUTMENT ;
    PORT
      LAYER M4 ;
      RECT 0.000 889.536 0.192 889.560 ;
    END
  END pma_rx[214]
  PIN pma_rx[215]
    DIRECTION INPUT ;
    USE SIGNAL ;
    SHAPE ABUTMENT ;
    PORT
      LAYER M4 ;
      RECT 0.000 893.616 0.192 893.640 ;
    END
  END pma_rx[215]
  PIN pma_rx[216]
    DIRECTION INPUT ;
    USE SIGNAL ;
    SHAPE ABUTMENT ;
    PORT
      LAYER M4 ;
      RECT 0.000 897.648 0.192 897.672 ;
    END
  END pma_rx[216]
  PIN pma_rx[217]
    DIRECTION INPUT ;
    USE SIGNAL ;
    SHAPE ABUTMENT ;
    PORT
      LAYER M4 ;
      RECT 0.000 901.728 0.192 901.752 ;
    END
  END pma_rx[217]
  PIN pma_rx[218]
    DIRECTION INPUT ;
    USE SIGNAL ;
    SHAPE ABUTMENT ;
    PORT
      LAYER M4 ;
      RECT 0.000 905.760 0.192 905.784 ;
    END
  END pma_rx[218]
  PIN pma_rx[219]
    DIRECTION INPUT ;
    USE SIGNAL ;
    SHAPE ABUTMENT ;
    PORT
      LAYER M4 ;
      RECT 0.000 909.840 0.192 909.864 ;
    END
  END pma_rx[219]
  PIN pma_rx[220]
    DIRECTION INPUT ;
    USE SIGNAL ;
    SHAPE ABUTMENT ;
    PORT
      LAYER M4 ;
      RECT 0.000 913.920 0.192 913.944 ;
    END
  END pma_rx[220]
  PIN pma_rx[221]
    DIRECTION INPUT ;
    USE SIGNAL ;
    SHAPE ABUTMENT ;
    PORT
      LAYER M4 ;
      RECT 0.000 917.952 0.192 917.976 ;
    END
  END pma_rx[221]
  PIN pma_rx[222]
    DIRECTION INPUT ;
    USE SIGNAL ;
    SHAPE ABUTMENT ;
    PORT
      LAYER M4 ;
      RECT 0.000 922.032 0.192 922.056 ;
    END
  END pma_rx[222]
  PIN pma_rx[223]
    DIRECTION INPUT ;
    USE SIGNAL ;
    SHAPE ABUTMENT ;
    PORT
      LAYER M4 ;
      RECT 0.000 926.064 0.192 926.088 ;
    END
  END pma_rx[223]
  PIN pma_rx[224]
    DIRECTION INPUT ;
    USE SIGNAL ;
    SHAPE ABUTMENT ;
    PORT
      LAYER M4 ;
      RECT 0.000 930.144 0.192 930.168 ;
    END
  END pma_rx[224]
  PIN pma_rx[225]
    DIRECTION INPUT ;
    USE SIGNAL ;
    SHAPE ABUTMENT ;
    PORT
      LAYER M4 ;
      RECT 0.000 934.224 0.192 934.248 ;
    END
  END pma_rx[225]
  PIN pma_rx[226]
    DIRECTION INPUT ;
    USE SIGNAL ;
    SHAPE ABUTMENT ;
    PORT
      LAYER M4 ;
      RECT 0.000 938.256 0.192 938.280 ;
    END
  END pma_rx[226]
  PIN pma_rx[227]
    DIRECTION INPUT ;
    USE SIGNAL ;
    SHAPE ABUTMENT ;
    PORT
      LAYER M4 ;
      RECT 0.000 942.336 0.192 942.360 ;
    END
  END pma_rx[227]
  PIN pma_rx[228]
    DIRECTION INPUT ;
    USE SIGNAL ;
    SHAPE ABUTMENT ;
    PORT
      LAYER M4 ;
      RECT 0.000 946.368 0.192 946.392 ;
    END
  END pma_rx[228]
  PIN pma_rx[229]
    DIRECTION INPUT ;
    USE SIGNAL ;
    SHAPE ABUTMENT ;
    PORT
      LAYER M4 ;
      RECT 0.000 950.448 0.192 950.472 ;
    END
  END pma_rx[229]
  PIN pma_rx[230]
    DIRECTION INPUT ;
    USE SIGNAL ;
    SHAPE ABUTMENT ;
    PORT
      LAYER M4 ;
      RECT 0.000 954.528 0.192 954.552 ;
    END
  END pma_rx[230]
  PIN pma_rx[231]
    DIRECTION INPUT ;
    USE SIGNAL ;
    SHAPE ABUTMENT ;
    PORT
      LAYER M4 ;
      RECT 0.000 958.560 0.192 958.584 ;
    END
  END pma_rx[231]
  PIN pma_rx[232]
    DIRECTION INPUT ;
    USE SIGNAL ;
    SHAPE ABUTMENT ;
    PORT
      LAYER M4 ;
      RECT 0.000 962.640 0.192 962.664 ;
    END
  END pma_rx[232]
  PIN pma_rx[233]
    DIRECTION INPUT ;
    USE SIGNAL ;
    SHAPE ABUTMENT ;
    PORT
      LAYER M4 ;
      RECT 0.000 966.672 0.192 966.696 ;
    END
  END pma_rx[233]
  PIN pma_rx[234]
    DIRECTION INPUT ;
    USE SIGNAL ;
    SHAPE ABUTMENT ;
    PORT
      LAYER M4 ;
      RECT 0.000 970.752 0.192 970.776 ;
    END
  END pma_rx[234]
  PIN pma_rx[235]
    DIRECTION INPUT ;
    USE SIGNAL ;
    SHAPE ABUTMENT ;
    PORT
      LAYER M4 ;
      RECT 0.000 974.832 0.192 974.856 ;
    END
  END pma_rx[235]
  PIN pma_rx[236]
    DIRECTION INPUT ;
    USE SIGNAL ;
    SHAPE ABUTMENT ;
    PORT
      LAYER M4 ;
      RECT 0.000 978.864 0.192 978.888 ;
    END
  END pma_rx[236]
  PIN pma_rx[237]
    DIRECTION INPUT ;
    USE SIGNAL ;
    SHAPE ABUTMENT ;
    PORT
      LAYER M4 ;
      RECT 0.000 982.944 0.192 982.968 ;
    END
  END pma_rx[237]
  PIN pma_rx[238]
    DIRECTION INPUT ;
    USE SIGNAL ;
    SHAPE ABUTMENT ;
    PORT
      LAYER M4 ;
      RECT 0.000 986.976 0.192 987.000 ;
    END
  END pma_rx[238]
  PIN pma_rx[239]
    DIRECTION INPUT ;
    USE SIGNAL ;
    SHAPE ABUTMENT ;
    PORT
      LAYER M4 ;
      RECT 0.000 991.056 0.192 991.080 ;
    END
  END pma_rx[239]
  PIN pma_rx[240]
    DIRECTION INPUT ;
    USE SIGNAL ;
    SHAPE ABUTMENT ;
    PORT
      LAYER M4 ;
      RECT 0.000 995.136 0.192 995.160 ;
    END
  END pma_rx[240]
  PIN pma_rx[241]
    DIRECTION INPUT ;
    USE SIGNAL ;
    SHAPE ABUTMENT ;
    PORT
      LAYER M4 ;
      RECT 0.000 999.168 0.192 999.192 ;
    END
  END pma_rx[241]
  PIN pma_rx[242]
    DIRECTION INPUT ;
    USE SIGNAL ;
    SHAPE ABUTMENT ;
    PORT
      LAYER M4 ;
      RECT 0.000 1003.248 0.192 1003.272 ;
    END
  END pma_rx[242]
  PIN pma_rx[243]
    DIRECTION INPUT ;
    USE SIGNAL ;
    SHAPE ABUTMENT ;
    PORT
      LAYER M4 ;
      RECT 0.000 1007.280 0.192 1007.304 ;
    END
  END pma_rx[243]
  PIN pma_rx[244]
    DIRECTION INPUT ;
    USE SIGNAL ;
    SHAPE ABUTMENT ;
    PORT
      LAYER M4 ;
      RECT 0.000 1011.360 0.192 1011.384 ;
    END
  END pma_rx[244]
  PIN pma_rx[245]
    DIRECTION INPUT ;
    USE SIGNAL ;
    SHAPE ABUTMENT ;
    PORT
      LAYER M4 ;
      RECT 0.000 1015.440 0.192 1015.464 ;
    END
  END pma_rx[245]
  PIN pma_rx[246]
    DIRECTION INPUT ;
    USE SIGNAL ;
    SHAPE ABUTMENT ;
    PORT
      LAYER M4 ;
      RECT 0.000 1019.472 0.192 1019.496 ;
    END
  END pma_rx[246]
  PIN pma_rx[247]
    DIRECTION INPUT ;
    USE SIGNAL ;
    SHAPE ABUTMENT ;
    PORT
      LAYER M4 ;
      RECT 0.000 1023.552 0.192 1023.576 ;
    END
  END pma_rx[247]
  PIN pma_rx[248]
    DIRECTION INPUT ;
    USE SIGNAL ;
    SHAPE ABUTMENT ;
    PORT
      LAYER M4 ;
      RECT 0.000 1027.584 0.192 1027.608 ;
    END
  END pma_rx[248]
  PIN pma_rx[249]
    DIRECTION INPUT ;
    USE SIGNAL ;
    SHAPE ABUTMENT ;
    PORT
      LAYER M4 ;
      RECT 0.000 1031.664 0.192 1031.688 ;
    END
  END pma_rx[249]
  PIN pma_rx[250]
    DIRECTION INPUT ;
    USE SIGNAL ;
    SHAPE ABUTMENT ;
    PORT
      LAYER M4 ;
      RECT 0.000 1035.744 0.192 1035.768 ;
    END
  END pma_rx[250]
  PIN pma_rx[251]
    DIRECTION INPUT ;
    USE SIGNAL ;
    SHAPE ABUTMENT ;
    PORT
      LAYER M4 ;
      RECT 0.000 1039.776 0.192 1039.800 ;
    END
  END pma_rx[251]
  PIN pma_rx[252]
    DIRECTION INPUT ;
    USE SIGNAL ;
    SHAPE ABUTMENT ;
    PORT
      LAYER M4 ;
      RECT 0.000 1043.856 0.192 1043.880 ;
    END
  END pma_rx[252]
  PIN pma_rx[253]
    DIRECTION INPUT ;
    USE SIGNAL ;
    SHAPE ABUTMENT ;
    PORT
      LAYER M4 ;
      RECT 0.000 1047.936 0.192 1047.960 ;
    END
  END pma_rx[253]
  PIN pma_rx[254]
    DIRECTION INPUT ;
    USE SIGNAL ;
    SHAPE ABUTMENT ;
    PORT
      LAYER M4 ;
      RECT 0.000 1051.968 0.192 1051.992 ;
    END
  END pma_rx[254]
  PIN pma_rx[255]
    DIRECTION INPUT ;
    USE SIGNAL ;
    SHAPE ABUTMENT ;
    PORT
      LAYER M4 ;
      RECT 0.000 1056.048 0.192 1056.072 ;
    END
  END pma_rx[255]
  PIN pma_rx[256]
    DIRECTION INPUT ;
    USE SIGNAL ;
    SHAPE ABUTMENT ;
    PORT
      LAYER M4 ;
      RECT 0.000 1060.080 0.192 1060.104 ;
    END
  END pma_rx[256]
  PIN pma_rx[257]
    DIRECTION INPUT ;
    USE SIGNAL ;
    SHAPE ABUTMENT ;
    PORT
      LAYER M4 ;
      RECT 0.000 1064.160 0.192 1064.184 ;
    END
  END pma_rx[257]
  PIN pma_rx[258]
    DIRECTION INPUT ;
    USE SIGNAL ;
    SHAPE ABUTMENT ;
    PORT
      LAYER M4 ;
      RECT 0.000 1068.240 0.192 1068.264 ;
    END
  END pma_rx[258]
  PIN pma_rx[259]
    DIRECTION INPUT ;
    USE SIGNAL ;
    SHAPE ABUTMENT ;
    PORT
      LAYER M4 ;
      RECT 0.000 1072.272 0.192 1072.296 ;
    END
  END pma_rx[259]
  PIN pma_rx[260]
    DIRECTION INPUT ;
    USE SIGNAL ;
    SHAPE ABUTMENT ;
    PORT
      LAYER M4 ;
      RECT 0.000 1076.352 0.192 1076.376 ;
    END
  END pma_rx[260]
  PIN pma_rx[261]
    DIRECTION INPUT ;
    USE SIGNAL ;
    SHAPE ABUTMENT ;
    PORT
      LAYER M4 ;
      RECT 0.000 1080.384 0.192 1080.408 ;
    END
  END pma_rx[261]
  PIN pma_rx[262]
    DIRECTION INPUT ;
    USE SIGNAL ;
    SHAPE ABUTMENT ;
    PORT
      LAYER M4 ;
      RECT 0.000 1084.464 0.192 1084.488 ;
    END
  END pma_rx[262]
  PIN pma_rx[263]
    DIRECTION INPUT ;
    USE SIGNAL ;
    SHAPE ABUTMENT ;
    PORT
      LAYER M4 ;
      RECT 0.000 1088.544 0.192 1088.568 ;
    END
  END pma_rx[263]
  PIN pma_rx[264]
    DIRECTION INPUT ;
    USE SIGNAL ;
    SHAPE ABUTMENT ;
    PORT
      LAYER M4 ;
      RECT 0.000 1092.576 0.192 1092.600 ;
    END
  END pma_rx[264]
  PIN pma_rx[265]
    DIRECTION INPUT ;
    USE SIGNAL ;
    SHAPE ABUTMENT ;
    PORT
      LAYER M4 ;
      RECT 0.000 1096.656 0.192 1096.680 ;
    END
  END pma_rx[265]
  PIN pma_rx[266]
    DIRECTION INPUT ;
    USE SIGNAL ;
    SHAPE ABUTMENT ;
    PORT
      LAYER M4 ;
      RECT 0.000 1100.688 0.192 1100.712 ;
    END
  END pma_rx[266]
  PIN pma_rx[267]
    DIRECTION INPUT ;
    USE SIGNAL ;
    SHAPE ABUTMENT ;
    PORT
      LAYER M4 ;
      RECT 0.000 1104.768 0.192 1104.792 ;
    END
  END pma_rx[267]
  PIN pma_rx[268]
    DIRECTION INPUT ;
    USE SIGNAL ;
    SHAPE ABUTMENT ;
    PORT
      LAYER M4 ;
      RECT 0.000 1108.848 0.192 1108.872 ;
    END
  END pma_rx[268]
  PIN pma_rx[269]
    DIRECTION INPUT ;
    USE SIGNAL ;
    SHAPE ABUTMENT ;
    PORT
      LAYER M4 ;
      RECT 0.000 1112.880 0.192 1112.904 ;
    END
  END pma_rx[269]
  PIN pma_rx[270]
    DIRECTION INPUT ;
    USE SIGNAL ;
    SHAPE ABUTMENT ;
    PORT
      LAYER M4 ;
      RECT 0.000 1116.960 0.192 1116.984 ;
    END
  END pma_rx[270]
  PIN pma_rx[271]
    DIRECTION INPUT ;
    USE SIGNAL ;
    SHAPE ABUTMENT ;
    PORT
      LAYER M4 ;
      RECT 0.000 1120.992 0.192 1121.016 ;
    END
  END pma_rx[271]
  PIN pma_rx[272]
    DIRECTION INPUT ;
    USE SIGNAL ;
    SHAPE ABUTMENT ;
    PORT
      LAYER M4 ;
      RECT 0.000 1125.072 0.192 1125.096 ;
    END
  END pma_rx[272]
  PIN pma_rx[273]
    DIRECTION INPUT ;
    USE SIGNAL ;
    SHAPE ABUTMENT ;
    PORT
      LAYER M4 ;
      RECT 0.000 1129.152 0.192 1129.176 ;
    END
  END pma_rx[273]
  PIN pma_rx[274]
    DIRECTION INPUT ;
    USE SIGNAL ;
    SHAPE ABUTMENT ;
    PORT
      LAYER M4 ;
      RECT 0.000 1133.184 0.192 1133.208 ;
    END
  END pma_rx[274]
  PIN pma_rx[275]
    DIRECTION INPUT ;
    USE SIGNAL ;
    SHAPE ABUTMENT ;
    PORT
      LAYER M4 ;
      RECT 0.000 1137.264 0.192 1137.288 ;
    END
  END pma_rx[275]
  PIN pma_rx[276]
    DIRECTION INPUT ;
    USE SIGNAL ;
    SHAPE ABUTMENT ;
    PORT
      LAYER M4 ;
      RECT 0.000 1141.296 0.192 1141.320 ;
    END
  END pma_rx[276]
  PIN pma_rx[277]
    DIRECTION INPUT ;
    USE SIGNAL ;
    SHAPE ABUTMENT ;
    PORT
      LAYER M4 ;
      RECT 0.000 1145.376 0.192 1145.400 ;
    END
  END pma_rx[277]
  PIN pma_rx[278]
    DIRECTION INPUT ;
    USE SIGNAL ;
    SHAPE ABUTMENT ;
    PORT
      LAYER M4 ;
      RECT 0.000 1149.456 0.192 1149.480 ;
    END
  END pma_rx[278]
  PIN pma_rx[279]
    DIRECTION INPUT ;
    USE SIGNAL ;
    SHAPE ABUTMENT ;
    PORT
      LAYER M4 ;
      RECT 0.000 1153.488 0.192 1153.512 ;
    END
  END pma_rx[279]
  PIN pma_rx[280]
    DIRECTION INPUT ;
    USE SIGNAL ;
    SHAPE ABUTMENT ;
    PORT
      LAYER M4 ;
      RECT 0.000 1157.568 0.192 1157.592 ;
    END
  END pma_rx[280]
  PIN pma_rx[281]
    DIRECTION INPUT ;
    USE SIGNAL ;
    SHAPE ABUTMENT ;
    PORT
      LAYER M4 ;
      RECT 0.000 1161.600 0.192 1161.624 ;
    END
  END pma_rx[281]
  PIN pma_rx[282]
    DIRECTION INPUT ;
    USE SIGNAL ;
    SHAPE ABUTMENT ;
    PORT
      LAYER M4 ;
      RECT 0.000 1165.680 0.192 1165.704 ;
    END
  END pma_rx[282]
  PIN pma_rx[283]
    DIRECTION INPUT ;
    USE SIGNAL ;
    SHAPE ABUTMENT ;
    PORT
      LAYER M4 ;
      RECT 0.000 1169.760 0.192 1169.784 ;
    END
  END pma_rx[283]
  PIN pma_rx[284]
    DIRECTION INPUT ;
    USE SIGNAL ;
    SHAPE ABUTMENT ;
    PORT
      LAYER M4 ;
      RECT 0.000 1173.792 0.192 1173.816 ;
    END
  END pma_rx[284]
  PIN pma_rx[285]
    DIRECTION INPUT ;
    USE SIGNAL ;
    SHAPE ABUTMENT ;
    PORT
      LAYER M4 ;
      RECT 0.000 1177.872 0.192 1177.896 ;
    END
  END pma_rx[285]
  PIN pma_rx[286]
    DIRECTION INPUT ;
    USE SIGNAL ;
    SHAPE ABUTMENT ;
    PORT
      LAYER M4 ;
      RECT 0.000 1181.904 0.192 1181.928 ;
    END
  END pma_rx[286]
  PIN pma_rx[287]
    DIRECTION INPUT ;
    USE SIGNAL ;
    SHAPE ABUTMENT ;
    PORT
      LAYER M4 ;
      RECT 0.000 1185.984 0.192 1186.008 ;
    END
  END pma_rx[287]
  PIN pma_rx[288]
    DIRECTION INPUT ;
    USE SIGNAL ;
    SHAPE ABUTMENT ;
    PORT
      LAYER M4 ;
      RECT 0.000 1190.064 0.192 1190.088 ;
    END
  END pma_rx[288]
  PIN pma_rx[289]
    DIRECTION INPUT ;
    USE SIGNAL ;
    SHAPE ABUTMENT ;
    PORT
      LAYER M4 ;
      RECT 0.000 1194.096 0.192 1194.120 ;
    END
  END pma_rx[289]
  PIN pma_rx[290]
    DIRECTION INPUT ;
    USE SIGNAL ;
    SHAPE ABUTMENT ;
    PORT
      LAYER M4 ;
      RECT 0.000 1198.176 0.192 1198.200 ;
    END
  END pma_rx[290]
  PIN pma_rx[291]
    DIRECTION INPUT ;
    USE SIGNAL ;
    SHAPE ABUTMENT ;
    PORT
      LAYER M4 ;
      RECT 0.000 1202.208 0.192 1202.232 ;
    END
  END pma_rx[291]
  PIN pma_rx[292]
    DIRECTION INPUT ;
    USE SIGNAL ;
    SHAPE ABUTMENT ;
    PORT
      LAYER M4 ;
      RECT 0.000 1206.288 0.192 1206.312 ;
    END
  END pma_rx[292]
  PIN pma_rx[293]
    DIRECTION INPUT ;
    USE SIGNAL ;
    SHAPE ABUTMENT ;
    PORT
      LAYER M4 ;
      RECT 0.000 1210.368 0.192 1210.392 ;
    END
  END pma_rx[293]
  PIN pma_rx[294]
    DIRECTION INPUT ;
    USE SIGNAL ;
    SHAPE ABUTMENT ;
    PORT
      LAYER M4 ;
      RECT 0.000 1214.400 0.192 1214.424 ;
    END
  END pma_rx[294]
  PIN pma_rx[295]
    DIRECTION INPUT ;
    USE SIGNAL ;
    SHAPE ABUTMENT ;
    PORT
      LAYER M4 ;
      RECT 0.000 1218.480 0.192 1218.504 ;
    END
  END pma_rx[295]
  PIN pma_rx[296]
    DIRECTION INPUT ;
    USE SIGNAL ;
    SHAPE ABUTMENT ;
    PORT
      LAYER M4 ;
      RECT 0.000 1222.560 0.192 1222.584 ;
    END
  END pma_rx[296]
  PIN pma_rx[297]
    DIRECTION INPUT ;
    USE SIGNAL ;
    SHAPE ABUTMENT ;
    PORT
      LAYER M4 ;
      RECT 0.000 1226.592 0.192 1226.616 ;
    END
  END pma_rx[297]
  PIN pma_rx[298]
    DIRECTION INPUT ;
    USE SIGNAL ;
    SHAPE ABUTMENT ;
    PORT
      LAYER M4 ;
      RECT 0.000 1230.672 0.192 1230.696 ;
    END
  END pma_rx[298]
  PIN pma_rx[299]
    DIRECTION INPUT ;
    USE SIGNAL ;
    SHAPE ABUTMENT ;
    PORT
      LAYER M4 ;
      RECT 0.000 1234.704 0.192 1234.728 ;
    END
  END pma_rx[299]
  PIN pma_rx[300]
    DIRECTION INPUT ;
    USE SIGNAL ;
    SHAPE ABUTMENT ;
    PORT
      LAYER M4 ;
      RECT 0.000 1238.784 0.192 1238.808 ;
    END
  END pma_rx[300]
  PIN pma_rx[301]
    DIRECTION INPUT ;
    USE SIGNAL ;
    SHAPE ABUTMENT ;
    PORT
      LAYER M4 ;
      RECT 0.000 1242.864 0.192 1242.888 ;
    END
  END pma_rx[301]
  PIN pma_rx[302]
    DIRECTION INPUT ;
    USE SIGNAL ;
    SHAPE ABUTMENT ;
    PORT
      LAYER M4 ;
      RECT 0.000 1246.896 0.192 1246.920 ;
    END
  END pma_rx[302]
  PIN pma_rx[303]
    DIRECTION INPUT ;
    USE SIGNAL ;
    SHAPE ABUTMENT ;
    PORT
      LAYER M4 ;
      RECT 0.000 1250.976 0.192 1251.000 ;
    END
  END pma_rx[303]
  PIN pma_rx[304]
    DIRECTION INPUT ;
    USE SIGNAL ;
    SHAPE ABUTMENT ;
    PORT
      LAYER M4 ;
      RECT 0.000 1255.008 0.192 1255.032 ;
    END
  END pma_rx[304]
  PIN pma_rx[305]
    DIRECTION INPUT ;
    USE SIGNAL ;
    SHAPE ABUTMENT ;
    PORT
      LAYER M4 ;
      RECT 0.000 1259.088 0.192 1259.112 ;
    END
  END pma_rx[305]
  PIN pma_rx[306]
    DIRECTION INPUT ;
    USE SIGNAL ;
    SHAPE ABUTMENT ;
    PORT
      LAYER M4 ;
      RECT 0.000 1263.168 0.192 1263.192 ;
    END
  END pma_rx[306]
  PIN pma_rx[307]
    DIRECTION INPUT ;
    USE SIGNAL ;
    SHAPE ABUTMENT ;
    PORT
      LAYER M4 ;
      RECT 0.000 1267.200 0.192 1267.224 ;
    END
  END pma_rx[307]
  PIN pma_rx[308]
    DIRECTION INPUT ;
    USE SIGNAL ;
    SHAPE ABUTMENT ;
    PORT
      LAYER M4 ;
      RECT 0.000 1271.280 0.192 1271.304 ;
    END
  END pma_rx[308]
  PIN pma_rx[309]
    DIRECTION INPUT ;
    USE SIGNAL ;
    SHAPE ABUTMENT ;
    PORT
      LAYER M4 ;
      RECT 0.000 1275.312 0.192 1275.336 ;
    END
  END pma_rx[309]
  PIN pma_rx[310]
    DIRECTION INPUT ;
    USE SIGNAL ;
    SHAPE ABUTMENT ;
    PORT
      LAYER M4 ;
      RECT 0.000 1279.392 0.192 1279.416 ;
    END
  END pma_rx[310]
  PIN pma_rx[311]
    DIRECTION INPUT ;
    USE SIGNAL ;
    SHAPE ABUTMENT ;
    PORT
      LAYER M4 ;
      RECT 0.000 1283.472 0.192 1283.496 ;
    END
  END pma_rx[311]
  PIN pma_rx[312]
    DIRECTION INPUT ;
    USE SIGNAL ;
    SHAPE ABUTMENT ;
    PORT
      LAYER M4 ;
      RECT 0.000 1287.504 0.192 1287.528 ;
    END
  END pma_rx[312]
  PIN pma_rx[313]
    DIRECTION INPUT ;
    USE SIGNAL ;
    SHAPE ABUTMENT ;
    PORT
      LAYER M4 ;
      RECT 0.000 1291.584 0.192 1291.608 ;
    END
  END pma_rx[313]
  PIN pma_rx[314]
    DIRECTION INPUT ;
    USE SIGNAL ;
    SHAPE ABUTMENT ;
    PORT
      LAYER M4 ;
      RECT 0.000 1295.616 0.192 1295.640 ;
    END
  END pma_rx[314]
  PIN pma_rx[315]
    DIRECTION INPUT ;
    USE SIGNAL ;
    SHAPE ABUTMENT ;
    PORT
      LAYER M4 ;
      RECT 0.000 1299.696 0.192 1299.720 ;
    END
  END pma_rx[315]
  PIN pma_rx[316]
    DIRECTION INPUT ;
    USE SIGNAL ;
    SHAPE ABUTMENT ;
    PORT
      LAYER M4 ;
      RECT 0.000 1303.776 0.192 1303.800 ;
    END
  END pma_rx[316]
  PIN pma_rx[317]
    DIRECTION INPUT ;
    USE SIGNAL ;
    SHAPE ABUTMENT ;
    PORT
      LAYER M4 ;
      RECT 0.000 1307.808 0.192 1307.832 ;
    END
  END pma_rx[317]
  PIN pma_rx[318]
    DIRECTION INPUT ;
    USE SIGNAL ;
    SHAPE ABUTMENT ;
    PORT
      LAYER M4 ;
      RECT 0.000 1311.888 0.192 1311.912 ;
    END
  END pma_rx[318]
  PIN pma_rx[319]
    DIRECTION INPUT ;
    USE SIGNAL ;
    SHAPE ABUTMENT ;
    PORT
      LAYER M4 ;
      RECT 0.000 1315.920 0.192 1315.944 ;
    END
  END pma_rx[319]
  PIN pma_rx[320]
    DIRECTION INPUT ;
    USE SIGNAL ;
    SHAPE ABUTMENT ;
    PORT
      LAYER M4 ;
      RECT 0.000 1320.000 0.192 1320.024 ;
    END
  END pma_rx[320]
  PIN pma_rx[321]
    DIRECTION INPUT ;
    USE SIGNAL ;
    SHAPE ABUTMENT ;
    PORT
      LAYER M4 ;
      RECT 0.000 1324.080 0.192 1324.104 ;
    END
  END pma_rx[321]
  PIN pma_rx[322]
    DIRECTION INPUT ;
    USE SIGNAL ;
    SHAPE ABUTMENT ;
    PORT
      LAYER M4 ;
      RECT 0.000 1328.112 0.192 1328.136 ;
    END
  END pma_rx[322]
  PIN pma_rx[323]
    DIRECTION INPUT ;
    USE SIGNAL ;
    SHAPE ABUTMENT ;
    PORT
      LAYER M4 ;
      RECT 0.000 1332.192 0.192 1332.216 ;
    END
  END pma_rx[323]
  PIN pma_rx[324]
    DIRECTION INPUT ;
    USE SIGNAL ;
    SHAPE ABUTMENT ;
    PORT
      LAYER M4 ;
      RECT 0.000 1336.224 0.192 1336.248 ;
    END
  END pma_rx[324]
  PIN pma_rx[325]
    DIRECTION INPUT ;
    USE SIGNAL ;
    SHAPE ABUTMENT ;
    PORT
      LAYER M4 ;
      RECT 0.000 1340.304 0.192 1340.328 ;
    END
  END pma_rx[325]
  PIN pma_rx[326]
    DIRECTION INPUT ;
    USE SIGNAL ;
    SHAPE ABUTMENT ;
    PORT
      LAYER M4 ;
      RECT 0.000 1344.384 0.192 1344.408 ;
    END
  END pma_rx[326]
  PIN pma_rx[327]
    DIRECTION INPUT ;
    USE SIGNAL ;
    SHAPE ABUTMENT ;
    PORT
      LAYER M4 ;
      RECT 0.000 1348.416 0.192 1348.440 ;
    END
  END pma_rx[327]
  PIN pma_rx[328]
    DIRECTION INPUT ;
    USE SIGNAL ;
    SHAPE ABUTMENT ;
    PORT
      LAYER M4 ;
      RECT 0.000 1352.496 0.192 1352.520 ;
    END
  END pma_rx[328]
  PIN pma_rx[329]
    DIRECTION INPUT ;
    USE SIGNAL ;
    SHAPE ABUTMENT ;
    PORT
      LAYER M4 ;
      RECT 0.000 1356.528 0.192 1356.552 ;
    END
  END pma_rx[329]
  PIN pma_rx[330]
    DIRECTION INPUT ;
    USE SIGNAL ;
    SHAPE ABUTMENT ;
    PORT
      LAYER M4 ;
      RECT 0.000 1360.608 0.192 1360.632 ;
    END
  END pma_rx[330]
  PIN pma_rx[331]
    DIRECTION INPUT ;
    USE SIGNAL ;
    SHAPE ABUTMENT ;
    PORT
      LAYER M4 ;
      RECT 0.000 1364.688 0.192 1364.712 ;
    END
  END pma_rx[331]
  PIN pma_rx[332]
    DIRECTION INPUT ;
    USE SIGNAL ;
    SHAPE ABUTMENT ;
    PORT
      LAYER M4 ;
      RECT 0.000 1368.720 0.192 1368.744 ;
    END
  END pma_rx[332]
  PIN pma_rx[333]
    DIRECTION INPUT ;
    USE SIGNAL ;
    SHAPE ABUTMENT ;
    PORT
      LAYER M4 ;
      RECT 0.000 1372.800 0.192 1372.824 ;
    END
  END pma_rx[333]
  PIN pma_rx[334]
    DIRECTION INPUT ;
    USE SIGNAL ;
    SHAPE ABUTMENT ;
    PORT
      LAYER M4 ;
      RECT 0.000 1376.832 0.192 1376.856 ;
    END
  END pma_rx[334]
  PIN pma_rx[335]
    DIRECTION INPUT ;
    USE SIGNAL ;
    SHAPE ABUTMENT ;
    PORT
      LAYER M4 ;
      RECT 0.000 1380.912 0.192 1380.936 ;
    END
  END pma_rx[335]
  PIN pma_rx[336]
    DIRECTION INPUT ;
    USE SIGNAL ;
    SHAPE ABUTMENT ;
    PORT
      LAYER M4 ;
      RECT 0.000 1384.992 0.192 1385.016 ;
    END
  END pma_rx[336]
  PIN pma_rx[337]
    DIRECTION INPUT ;
    USE SIGNAL ;
    SHAPE ABUTMENT ;
    PORT
      LAYER M4 ;
      RECT 0.000 1389.024 0.192 1389.048 ;
    END
  END pma_rx[337]
  PIN pma_rx[338]
    DIRECTION INPUT ;
    USE SIGNAL ;
    SHAPE ABUTMENT ;
    PORT
      LAYER M4 ;
      RECT 0.000 1393.104 0.192 1393.128 ;
    END
  END pma_rx[338]
  PIN pma_rx[339]
    DIRECTION INPUT ;
    USE SIGNAL ;
    SHAPE ABUTMENT ;
    PORT
      LAYER M4 ;
      RECT 0.000 1397.184 0.192 1397.208 ;
    END
  END pma_rx[339]
  PIN pma_rx[340]
    DIRECTION INPUT ;
    USE SIGNAL ;
    SHAPE ABUTMENT ;
    PORT
      LAYER M4 ;
      RECT 0.000 1401.216 0.192 1401.240 ;
    END
  END pma_rx[340]
  PIN pma_rx[341]
    DIRECTION INPUT ;
    USE SIGNAL ;
    SHAPE ABUTMENT ;
    PORT
      LAYER M4 ;
      RECT 0.000 1405.296 0.192 1405.320 ;
    END
  END pma_rx[341]
  PIN pma_rx[342]
    DIRECTION INPUT ;
    USE SIGNAL ;
    SHAPE ABUTMENT ;
    PORT
      LAYER M4 ;
      RECT 0.000 1409.328 0.192 1409.352 ;
    END
  END pma_rx[342]
  PIN pma_rx[343]
    DIRECTION INPUT ;
    USE SIGNAL ;
    SHAPE ABUTMENT ;
    PORT
      LAYER M4 ;
      RECT 0.000 1413.408 0.192 1413.432 ;
    END
  END pma_rx[343]
  PIN pma_rx[344]
    DIRECTION INPUT ;
    USE SIGNAL ;
    SHAPE ABUTMENT ;
    PORT
      LAYER M4 ;
      RECT 0.000 1417.488 0.192 1417.512 ;
    END
  END pma_rx[344]
  PIN pma_rx[345]
    DIRECTION INPUT ;
    USE SIGNAL ;
    SHAPE ABUTMENT ;
    PORT
      LAYER M4 ;
      RECT 0.000 1421.520 0.192 1421.544 ;
    END
  END pma_rx[345]
  PIN pma_rx[346]
    DIRECTION INPUT ;
    USE SIGNAL ;
    SHAPE ABUTMENT ;
    PORT
      LAYER M4 ;
      RECT 0.000 1425.600 0.192 1425.624 ;
    END
  END pma_rx[346]
  PIN pma_rx[347]
    DIRECTION INPUT ;
    USE SIGNAL ;
    SHAPE ABUTMENT ;
    PORT
      LAYER M4 ;
      RECT 0.000 1429.632 0.192 1429.656 ;
    END
  END pma_rx[347]
  PIN pma_rx[348]
    DIRECTION INPUT ;
    USE SIGNAL ;
    SHAPE ABUTMENT ;
    PORT
      LAYER M4 ;
      RECT 0.000 1433.712 0.192 1433.736 ;
    END
  END pma_rx[348]
  PIN pma_rx[349]
    DIRECTION INPUT ;
    USE SIGNAL ;
    SHAPE ABUTMENT ;
    PORT
      LAYER M4 ;
      RECT 0.000 1437.792 0.192 1437.816 ;
    END
  END pma_rx[349]
  PIN pma_rx[350]
    DIRECTION INPUT ;
    USE SIGNAL ;
    SHAPE ABUTMENT ;
    PORT
      LAYER M4 ;
      RECT 0.000 1441.824 0.192 1441.848 ;
    END
  END pma_rx[350]
  PIN pma_rx[351]
    DIRECTION INPUT ;
    USE SIGNAL ;
    SHAPE ABUTMENT ;
    PORT
      LAYER M4 ;
      RECT 0.000 1445.904 0.192 1445.928 ;
    END
  END pma_rx[351]
  PIN pma_rx[352]
    DIRECTION INPUT ;
    USE SIGNAL ;
    SHAPE ABUTMENT ;
    PORT
      LAYER M4 ;
      RECT 0.000 1449.936 0.192 1449.960 ;
    END
  END pma_rx[352]
  PIN pma_rx[353]
    DIRECTION INPUT ;
    USE SIGNAL ;
    SHAPE ABUTMENT ;
    PORT
      LAYER M4 ;
      RECT 0.000 1454.016 0.192 1454.040 ;
    END
  END pma_rx[353]
  PIN pma_rx[354]
    DIRECTION INPUT ;
    USE SIGNAL ;
    SHAPE ABUTMENT ;
    PORT
      LAYER M4 ;
      RECT 0.000 1458.096 0.192 1458.120 ;
    END
  END pma_rx[354]
  PIN pma_rx[355]
    DIRECTION INPUT ;
    USE SIGNAL ;
    SHAPE ABUTMENT ;
    PORT
      LAYER M4 ;
      RECT 0.000 1462.128 0.192 1462.152 ;
    END
  END pma_rx[355]
  PIN pma_rx[356]
    DIRECTION INPUT ;
    USE SIGNAL ;
    SHAPE ABUTMENT ;
    PORT
      LAYER M4 ;
      RECT 0.000 1466.208 0.192 1466.232 ;
    END
  END pma_rx[356]
  PIN pma_rx[357]
    DIRECTION INPUT ;
    USE SIGNAL ;
    SHAPE ABUTMENT ;
    PORT
      LAYER M4 ;
      RECT 0.000 1470.240 0.192 1470.264 ;
    END
  END pma_rx[357]
  PIN pma_rx[358]
    DIRECTION INPUT ;
    USE SIGNAL ;
    SHAPE ABUTMENT ;
    PORT
      LAYER M4 ;
      RECT 0.000 1474.320 0.192 1474.344 ;
    END
  END pma_rx[358]
  PIN pma_rx[359]
    DIRECTION INPUT ;
    USE SIGNAL ;
    SHAPE ABUTMENT ;
    PORT
      LAYER M4 ;
      RECT 0.000 1478.400 0.192 1478.424 ;
    END
  END pma_rx[359]
  PIN pma_rx[360]
    DIRECTION INPUT ;
    USE SIGNAL ;
    SHAPE ABUTMENT ;
    PORT
      LAYER M4 ;
      RECT 0.000 1482.432 0.192 1482.456 ;
    END
  END pma_rx[360]
  PIN pma_rx[361]
    DIRECTION INPUT ;
    USE SIGNAL ;
    SHAPE ABUTMENT ;
    PORT
      LAYER M4 ;
      RECT 0.000 1486.512 0.192 1486.536 ;
    END
  END pma_rx[361]
  PIN pma_rx[362]
    DIRECTION INPUT ;
    USE SIGNAL ;
    SHAPE ABUTMENT ;
    PORT
      LAYER M4 ;
      RECT 0.000 1490.544 0.192 1490.568 ;
    END
  END pma_rx[362]
  PIN pma_rx[363]
    DIRECTION INPUT ;
    USE SIGNAL ;
    SHAPE ABUTMENT ;
    PORT
      LAYER M4 ;
      RECT 0.000 1494.624 0.192 1494.648 ;
    END
  END pma_rx[363]
  PIN pma_rx[364]
    DIRECTION INPUT ;
    USE SIGNAL ;
    SHAPE ABUTMENT ;
    PORT
      LAYER M4 ;
      RECT 0.000 1498.704 0.192 1498.728 ;
    END
  END pma_rx[364]
  PIN pma_rx[365]
    DIRECTION INPUT ;
    USE SIGNAL ;
    SHAPE ABUTMENT ;
    PORT
      LAYER M4 ;
      RECT 0.000 1502.736 0.192 1502.760 ;
    END
  END pma_rx[365]
  PIN pma_rx[366]
    DIRECTION INPUT ;
    USE SIGNAL ;
    SHAPE ABUTMENT ;
    PORT
      LAYER M4 ;
      RECT 0.000 1506.816 0.192 1506.840 ;
    END
  END pma_rx[366]
  PIN pma_rx[367]
    DIRECTION INPUT ;
    USE SIGNAL ;
    SHAPE ABUTMENT ;
    PORT
      LAYER M4 ;
      RECT 0.000 1510.848 0.192 1510.872 ;
    END
  END pma_rx[367]
  PIN pma_rx[368]
    DIRECTION INPUT ;
    USE SIGNAL ;
    SHAPE ABUTMENT ;
    PORT
      LAYER M4 ;
      RECT 0.000 1514.928 0.192 1514.952 ;
    END
  END pma_rx[368]
  PIN pma_rx[369]
    DIRECTION INPUT ;
    USE SIGNAL ;
    SHAPE ABUTMENT ;
    PORT
      LAYER M4 ;
      RECT 0.000 1519.008 0.192 1519.032 ;
    END
  END pma_rx[369]
  PIN pma_rx[370]
    DIRECTION INPUT ;
    USE SIGNAL ;
    SHAPE ABUTMENT ;
    PORT
      LAYER M4 ;
      RECT 0.000 1523.040 0.192 1523.064 ;
    END
  END pma_rx[370]
  PIN pma_rx[371]
    DIRECTION INPUT ;
    USE SIGNAL ;
    SHAPE ABUTMENT ;
    PORT
      LAYER M4 ;
      RECT 0.000 1527.120 0.192 1527.144 ;
    END
  END pma_rx[371]
  PIN pma_rx[372]
    DIRECTION INPUT ;
    USE SIGNAL ;
    SHAPE ABUTMENT ;
    PORT
      LAYER M4 ;
      RECT 0.000 1531.152 0.192 1531.176 ;
    END
  END pma_rx[372]
  PIN pma_rx[373]
    DIRECTION INPUT ;
    USE SIGNAL ;
    SHAPE ABUTMENT ;
    PORT
      LAYER M4 ;
      RECT 0.000 1535.232 0.192 1535.256 ;
    END
  END pma_rx[373]
  PIN pma_rx[374]
    DIRECTION INPUT ;
    USE SIGNAL ;
    SHAPE ABUTMENT ;
    PORT
      LAYER M4 ;
      RECT 0.000 1539.312 0.192 1539.336 ;
    END
  END pma_rx[374]
  PIN pma_rx[375]
    DIRECTION INPUT ;
    USE SIGNAL ;
    SHAPE ABUTMENT ;
    PORT
      LAYER M4 ;
      RECT 0.000 1543.344 0.192 1543.368 ;
    END
  END pma_rx[375]
  PIN pma_rx[376]
    DIRECTION INPUT ;
    USE SIGNAL ;
    SHAPE ABUTMENT ;
    PORT
      LAYER M4 ;
      RECT 0.000 1547.424 0.192 1547.448 ;
    END
  END pma_rx[376]
  PIN pma_rx[377]
    DIRECTION INPUT ;
    USE SIGNAL ;
    SHAPE ABUTMENT ;
    PORT
      LAYER M4 ;
      RECT 0.000 1551.504 0.192 1551.528 ;
    END
  END pma_rx[377]
  PIN pma_rx[378]
    DIRECTION INPUT ;
    USE SIGNAL ;
    SHAPE ABUTMENT ;
    PORT
      LAYER M4 ;
      RECT 0.000 1555.536 0.192 1555.560 ;
    END
  END pma_rx[378]
  PIN pma_rx[379]
    DIRECTION INPUT ;
    USE SIGNAL ;
    SHAPE ABUTMENT ;
    PORT
      LAYER M4 ;
      RECT 0.000 1559.616 0.192 1559.640 ;
    END
  END pma_rx[379]
  PIN pma_rx[380]
    DIRECTION INPUT ;
    USE SIGNAL ;
    SHAPE ABUTMENT ;
    PORT
      LAYER M4 ;
      RECT 0.000 1563.648 0.192 1563.672 ;
    END
  END pma_rx[380]
  PIN pma_rx[381]
    DIRECTION INPUT ;
    USE SIGNAL ;
    SHAPE ABUTMENT ;
    PORT
      LAYER M4 ;
      RECT 0.000 1567.728 0.192 1567.752 ;
    END
  END pma_rx[381]
  PIN pma_rx[382]
    DIRECTION INPUT ;
    USE SIGNAL ;
    SHAPE ABUTMENT ;
    PORT
      LAYER M4 ;
      RECT 0.000 1571.808 0.192 1571.832 ;
    END
  END pma_rx[382]
  PIN pma_rx[383]
    DIRECTION INPUT ;
    USE SIGNAL ;
    SHAPE ABUTMENT ;
    PORT
      LAYER M4 ;
      RECT 0.000 1575.840 0.192 1575.864 ;
    END
  END pma_rx[383]
  PIN pma_rx[384]
    DIRECTION INPUT ;
    USE SIGNAL ;
    SHAPE ABUTMENT ;
    PORT
      LAYER M4 ;
      RECT 0.000 1579.920 0.192 1579.944 ;
    END
  END pma_rx[384]
  PIN pma_rx[385]
    DIRECTION INPUT ;
    USE SIGNAL ;
    SHAPE ABUTMENT ;
    PORT
      LAYER M4 ;
      RECT 0.000 1583.952 0.192 1583.976 ;
    END
  END pma_rx[385]
  PIN pma_rx[386]
    DIRECTION INPUT ;
    USE SIGNAL ;
    SHAPE ABUTMENT ;
    PORT
      LAYER M4 ;
      RECT 0.000 1588.032 0.192 1588.056 ;
    END
  END pma_rx[386]
  PIN pma_rx[387]
    DIRECTION INPUT ;
    USE SIGNAL ;
    SHAPE ABUTMENT ;
    PORT
      LAYER M4 ;
      RECT 0.000 1592.112 0.192 1592.136 ;
    END
  END pma_rx[387]
  PIN pma_rx[388]
    DIRECTION INPUT ;
    USE SIGNAL ;
    SHAPE ABUTMENT ;
    PORT
      LAYER M4 ;
      RECT 0.000 1596.144 0.192 1596.168 ;
    END
  END pma_rx[388]
  PIN pma_rx[389]
    DIRECTION INPUT ;
    USE SIGNAL ;
    SHAPE ABUTMENT ;
    PORT
      LAYER M4 ;
      RECT 0.000 1600.224 0.192 1600.248 ;
    END
  END pma_rx[389]
  PIN pma_rx[390]
    DIRECTION INPUT ;
    USE SIGNAL ;
    SHAPE ABUTMENT ;
    PORT
      LAYER M4 ;
      RECT 0.000 1604.256 0.192 1604.280 ;
    END
  END pma_rx[390]
  PIN pma_rx[391]
    DIRECTION INPUT ;
    USE SIGNAL ;
    SHAPE ABUTMENT ;
    PORT
      LAYER M4 ;
      RECT 0.000 1608.336 0.192 1608.360 ;
    END
  END pma_rx[391]
  PIN pma_rx[392]
    DIRECTION INPUT ;
    USE SIGNAL ;
    SHAPE ABUTMENT ;
    PORT
      LAYER M4 ;
      RECT 0.000 1612.416 0.192 1612.440 ;
    END
  END pma_rx[392]
  PIN pma_rx[393]
    DIRECTION INPUT ;
    USE SIGNAL ;
    SHAPE ABUTMENT ;
    PORT
      LAYER M4 ;
      RECT 0.000 1616.448 0.192 1616.472 ;
    END
  END pma_rx[393]
  PIN pma_rx[394]
    DIRECTION INPUT ;
    USE SIGNAL ;
    SHAPE ABUTMENT ;
    PORT
      LAYER M4 ;
      RECT 0.000 1620.528 0.192 1620.552 ;
    END
  END pma_rx[394]
  PIN pma_rx[395]
    DIRECTION INPUT ;
    USE SIGNAL ;
    SHAPE ABUTMENT ;
    PORT
      LAYER M4 ;
      RECT 0.000 1624.560 0.192 1624.584 ;
    END
  END pma_rx[395]
  PIN pma_rx[396]
    DIRECTION INPUT ;
    USE SIGNAL ;
    SHAPE ABUTMENT ;
    PORT
      LAYER M4 ;
      RECT 0.000 1628.640 0.192 1628.664 ;
    END
  END pma_rx[396]
  PIN pma_rx[397]
    DIRECTION INPUT ;
    USE SIGNAL ;
    SHAPE ABUTMENT ;
    PORT
      LAYER M4 ;
      RECT 0.000 1632.720 0.192 1632.744 ;
    END
  END pma_rx[397]
  PIN pma_rx[398]
    DIRECTION INPUT ;
    USE SIGNAL ;
    SHAPE ABUTMENT ;
    PORT
      LAYER M4 ;
      RECT 0.000 1636.752 0.192 1636.776 ;
    END
  END pma_rx[398]
  PIN pma_rx[399]
    DIRECTION INPUT ;
    USE SIGNAL ;
    SHAPE ABUTMENT ;
    PORT
      LAYER M4 ;
      RECT 0.000 1640.832 0.192 1640.856 ;
    END
  END pma_rx[399]
  PIN pma_rx[400]
    DIRECTION INPUT ;
    USE SIGNAL ;
    SHAPE ABUTMENT ;
    PORT
      LAYER M4 ;
      RECT 0.000 1644.864 0.192 1644.888 ;
    END
  END pma_rx[400]
  PIN pma_rx[401]
    DIRECTION INPUT ;
    USE SIGNAL ;
    SHAPE ABUTMENT ;
    PORT
      LAYER M4 ;
      RECT 0.000 1648.944 0.192 1648.968 ;
    END
  END pma_rx[401]
  PIN pma_rx[402]
    DIRECTION INPUT ;
    USE SIGNAL ;
    SHAPE ABUTMENT ;
    PORT
      LAYER M4 ;
      RECT 0.000 1653.024 0.192 1653.048 ;
    END
  END pma_rx[402]
  PIN pma_rx[403]
    DIRECTION INPUT ;
    USE SIGNAL ;
    SHAPE ABUTMENT ;
    PORT
      LAYER M4 ;
      RECT 0.000 1657.056 0.192 1657.080 ;
    END
  END pma_rx[403]
  PIN pma_rx[404]
    DIRECTION INPUT ;
    USE SIGNAL ;
    SHAPE ABUTMENT ;
    PORT
      LAYER M4 ;
      RECT 0.000 1661.136 0.192 1661.160 ;
    END
  END pma_rx[404]
  PIN pma_rx[405]
    DIRECTION INPUT ;
    USE SIGNAL ;
    SHAPE ABUTMENT ;
    PORT
      LAYER M4 ;
      RECT 0.000 1665.168 0.192 1665.192 ;
    END
  END pma_rx[405]
  PIN pma_rx[406]
    DIRECTION INPUT ;
    USE SIGNAL ;
    SHAPE ABUTMENT ;
    PORT
      LAYER M4 ;
      RECT 0.000 1669.248 0.192 1669.272 ;
    END
  END pma_rx[406]
  PIN pma_rx[407]
    DIRECTION INPUT ;
    USE SIGNAL ;
    SHAPE ABUTMENT ;
    PORT
      LAYER M4 ;
      RECT 0.000 1673.328 0.192 1673.352 ;
    END
  END pma_rx[407]
  PIN pma_rx[408]
    DIRECTION INPUT ;
    USE SIGNAL ;
    SHAPE ABUTMENT ;
    PORT
      LAYER M4 ;
      RECT 0.000 1677.360 0.192 1677.384 ;
    END
  END pma_rx[408]
  PIN pma_rx[409]
    DIRECTION INPUT ;
    USE SIGNAL ;
    SHAPE ABUTMENT ;
    PORT
      LAYER M4 ;
      RECT 0.000 1681.440 0.192 1681.464 ;
    END
  END pma_rx[409]
  PIN pma_rx[410]
    DIRECTION INPUT ;
    USE SIGNAL ;
    SHAPE ABUTMENT ;
    PORT
      LAYER M4 ;
      RECT 0.000 1685.472 0.192 1685.496 ;
    END
  END pma_rx[410]
  PIN pma_rx[411]
    DIRECTION INPUT ;
    USE SIGNAL ;
    SHAPE ABUTMENT ;
    PORT
      LAYER M4 ;
      RECT 0.000 1689.552 0.192 1689.576 ;
    END
  END pma_rx[411]
  PIN pma_rx[412]
    DIRECTION INPUT ;
    USE SIGNAL ;
    SHAPE ABUTMENT ;
    PORT
      LAYER M4 ;
      RECT 0.000 1693.632 0.192 1693.656 ;
    END
  END pma_rx[412]
  PIN pma_rx[413]
    DIRECTION INPUT ;
    USE SIGNAL ;
    SHAPE ABUTMENT ;
    PORT
      LAYER M4 ;
      RECT 0.000 1697.664 0.192 1697.688 ;
    END
  END pma_rx[413]
  PIN pma_rx[414]
    DIRECTION INPUT ;
    USE SIGNAL ;
    SHAPE ABUTMENT ;
    PORT
      LAYER M4 ;
      RECT 0.000 1701.744 0.192 1701.768 ;
    END
  END pma_rx[414]
  PIN pma_rx[415]
    DIRECTION INPUT ;
    USE SIGNAL ;
    SHAPE ABUTMENT ;
    PORT
      LAYER M4 ;
      RECT 0.000 1705.776 0.192 1705.800 ;
    END
  END pma_rx[415]
  PIN pma_rx[416]
    DIRECTION INPUT ;
    USE SIGNAL ;
    SHAPE ABUTMENT ;
    PORT
      LAYER M4 ;
      RECT 0.000 1709.856 0.192 1709.880 ;
    END
  END pma_rx[416]
  PIN pma_rx[417]
    DIRECTION INPUT ;
    USE SIGNAL ;
    SHAPE ABUTMENT ;
    PORT
      LAYER M4 ;
      RECT 0.000 1713.936 0.192 1713.960 ;
    END
  END pma_rx[417]
  PIN pma_rx[418]
    DIRECTION INPUT ;
    USE SIGNAL ;
    SHAPE ABUTMENT ;
    PORT
      LAYER M4 ;
      RECT 0.000 1717.968 0.192 1717.992 ;
    END
  END pma_rx[418]
  PIN pma_rx[419]
    DIRECTION INPUT ;
    USE SIGNAL ;
    SHAPE ABUTMENT ;
    PORT
      LAYER M4 ;
      RECT 0.000 1722.048 0.192 1722.072 ;
    END
  END pma_rx[419]
  PIN pma_rx[420]
    DIRECTION INPUT ;
    USE SIGNAL ;
    SHAPE ABUTMENT ;
    PORT
      LAYER M4 ;
      RECT 0.000 1726.128 0.192 1726.152 ;
    END
  END pma_rx[420]
  PIN pma_rx[421]
    DIRECTION INPUT ;
    USE SIGNAL ;
    SHAPE ABUTMENT ;
    PORT
      LAYER M4 ;
      RECT 0.000 1730.160 0.192 1730.184 ;
    END
  END pma_rx[421]
  PIN pma_rx[422]
    DIRECTION INPUT ;
    USE SIGNAL ;
    SHAPE ABUTMENT ;
    PORT
      LAYER M4 ;
      RECT 0.000 1734.240 0.192 1734.264 ;
    END
  END pma_rx[422]
  PIN pma_rx[423]
    DIRECTION INPUT ;
    USE SIGNAL ;
    SHAPE ABUTMENT ;
    PORT
      LAYER M4 ;
      RECT 0.000 1738.272 0.192 1738.296 ;
    END
  END pma_rx[423]
  PIN pma_rx[424]
    DIRECTION INPUT ;
    USE SIGNAL ;
    SHAPE ABUTMENT ;
    PORT
      LAYER M4 ;
      RECT 0.000 1742.352 0.192 1742.376 ;
    END
  END pma_rx[424]
  PIN pma_rx[425]
    DIRECTION INPUT ;
    USE SIGNAL ;
    SHAPE ABUTMENT ;
    PORT
      LAYER M4 ;
      RECT 0.000 1746.432 0.192 1746.456 ;
    END
  END pma_rx[425]
  PIN pma_rx[426]
    DIRECTION INPUT ;
    USE SIGNAL ;
    SHAPE ABUTMENT ;
    PORT
      LAYER M4 ;
      RECT 0.000 1750.464 0.192 1750.488 ;
    END
  END pma_rx[426]
  PIN pma_rx[427]
    DIRECTION INPUT ;
    USE SIGNAL ;
    SHAPE ABUTMENT ;
    PORT
      LAYER M4 ;
      RECT 0.000 1754.544 0.192 1754.568 ;
    END
  END pma_rx[427]
  PIN pma_rx[428]
    DIRECTION INPUT ;
    USE SIGNAL ;
    SHAPE ABUTMENT ;
    PORT
      LAYER M4 ;
      RECT 0.000 1758.576 0.192 1758.600 ;
    END
  END pma_rx[428]
  PIN pma_rx[429]
    DIRECTION INPUT ;
    USE SIGNAL ;
    SHAPE ABUTMENT ;
    PORT
      LAYER M4 ;
      RECT 0.000 1762.656 0.192 1762.680 ;
    END
  END pma_rx[429]
  PIN pma_rx[430]
    DIRECTION INPUT ;
    USE SIGNAL ;
    SHAPE ABUTMENT ;
    PORT
      LAYER M4 ;
      RECT 0.000 1766.736 0.192 1766.760 ;
    END
  END pma_rx[430]
  PIN pma_rx[431]
    DIRECTION INPUT ;
    USE SIGNAL ;
    SHAPE ABUTMENT ;
    PORT
      LAYER M4 ;
      RECT 0.000 1770.768 0.192 1770.792 ;
    END
  END pma_rx[431]
  PIN pma_rx[432]
    DIRECTION INPUT ;
    USE SIGNAL ;
    SHAPE ABUTMENT ;
    PORT
      LAYER M4 ;
      RECT 0.000 1774.848 0.192 1774.872 ;
    END
  END pma_rx[432]
  PIN pma_rx[433]
    DIRECTION INPUT ;
    USE SIGNAL ;
    SHAPE ABUTMENT ;
    PORT
      LAYER M4 ;
      RECT 0.000 1778.880 0.192 1778.904 ;
    END
  END pma_rx[433]
  PIN pma_rx[434]
    DIRECTION INPUT ;
    USE SIGNAL ;
    SHAPE ABUTMENT ;
    PORT
      LAYER M4 ;
      RECT 0.000 1782.960 0.192 1782.984 ;
    END
  END pma_rx[434]
  PIN pma_rx[435]
    DIRECTION INPUT ;
    USE SIGNAL ;
    SHAPE ABUTMENT ;
    PORT
      LAYER M4 ;
      RECT 0.000 1787.040 0.192 1787.064 ;
    END
  END pma_rx[435]
  PIN pma_rx[436]
    DIRECTION INPUT ;
    USE SIGNAL ;
    SHAPE ABUTMENT ;
    PORT
      LAYER M4 ;
      RECT 0.000 1791.072 0.192 1791.096 ;
    END
  END pma_rx[436]
  PIN pma_rx[437]
    DIRECTION INPUT ;
    USE SIGNAL ;
    SHAPE ABUTMENT ;
    PORT
      LAYER M4 ;
      RECT 0.000 1795.152 0.192 1795.176 ;
    END
  END pma_rx[437]
  PIN pma_rx[438]
    DIRECTION INPUT ;
    USE SIGNAL ;
    SHAPE ABUTMENT ;
    PORT
      LAYER M4 ;
      RECT 0.000 1799.184 0.192 1799.208 ;
    END
  END pma_rx[438]
  PIN pma_rx[439]
    DIRECTION INPUT ;
    USE SIGNAL ;
    SHAPE ABUTMENT ;
    PORT
      LAYER M4 ;
      RECT 0.000 1803.264 0.192 1803.288 ;
    END
  END pma_rx[439]
  PIN pma_rx[440]
    DIRECTION INPUT ;
    USE SIGNAL ;
    SHAPE ABUTMENT ;
    PORT
      LAYER M4 ;
      RECT 0.000 1807.344 0.192 1807.368 ;
    END
  END pma_rx[440]
  PIN pma_rx[441]
    DIRECTION INPUT ;
    USE SIGNAL ;
    SHAPE ABUTMENT ;
    PORT
      LAYER M4 ;
      RECT 0.000 1811.376 0.192 1811.400 ;
    END
  END pma_rx[441]
  PIN pma_rx[442]
    DIRECTION INPUT ;
    USE SIGNAL ;
    SHAPE ABUTMENT ;
    PORT
      LAYER M4 ;
      RECT 0.000 1815.456 0.192 1815.480 ;
    END
  END pma_rx[442]
  PIN pma_rx[443]
    DIRECTION INPUT ;
    USE SIGNAL ;
    SHAPE ABUTMENT ;
    PORT
      LAYER M4 ;
      RECT 0.000 1819.488 0.192 1819.512 ;
    END
  END pma_rx[443]
  PIN pma_rx[444]
    DIRECTION INPUT ;
    USE SIGNAL ;
    SHAPE ABUTMENT ;
    PORT
      LAYER M4 ;
      RECT 0.000 1823.568 0.192 1823.592 ;
    END
  END pma_rx[444]
  PIN pma_rx[445]
    DIRECTION INPUT ;
    USE SIGNAL ;
    SHAPE ABUTMENT ;
    PORT
      LAYER M4 ;
      RECT 0.000 1827.648 0.192 1827.672 ;
    END
  END pma_rx[445]
  PIN pma_rx[446]
    DIRECTION INPUT ;
    USE SIGNAL ;
    SHAPE ABUTMENT ;
    PORT
      LAYER M4 ;
      RECT 0.000 1831.680 0.192 1831.704 ;
    END
  END pma_rx[446]
  PIN pma_rx[447]
    DIRECTION INPUT ;
    USE SIGNAL ;
    SHAPE ABUTMENT ;
    PORT
      LAYER M4 ;
      RECT 0.000 1835.760 0.192 1835.784 ;
    END
  END pma_rx[447]
  PIN pma_rx[448]
    DIRECTION INPUT ;
    USE SIGNAL ;
    SHAPE ABUTMENT ;
    PORT
      LAYER M4 ;
      RECT 0.000 1839.792 0.192 1839.816 ;
    END
  END pma_rx[448]
  PIN pma_rx[449]
    DIRECTION INPUT ;
    USE SIGNAL ;
    SHAPE ABUTMENT ;
    PORT
      LAYER M4 ;
      RECT 0.000 1843.872 0.192 1843.896 ;
    END
  END pma_rx[449]
  PIN pma_rx[450]
    DIRECTION INPUT ;
    USE SIGNAL ;
    SHAPE ABUTMENT ;
    PORT
      LAYER M4 ;
      RECT 0.000 1847.952 0.192 1847.976 ;
    END
  END pma_rx[450]
  PIN pma_rx[451]
    DIRECTION INPUT ;
    USE SIGNAL ;
    SHAPE ABUTMENT ;
    PORT
      LAYER M4 ;
      RECT 0.000 1851.984 0.192 1852.008 ;
    END
  END pma_rx[451]
  PIN pma_rx[452]
    DIRECTION INPUT ;
    USE SIGNAL ;
    SHAPE ABUTMENT ;
    PORT
      LAYER M4 ;
      RECT 0.000 1856.064 0.192 1856.088 ;
    END
  END pma_rx[452]
  PIN pma_rx[453]
    DIRECTION INPUT ;
    USE SIGNAL ;
    SHAPE ABUTMENT ;
    PORT
      LAYER M4 ;
      RECT 0.000 1860.096 0.192 1860.120 ;
    END
  END pma_rx[453]
  PIN pma_rx[454]
    DIRECTION INPUT ;
    USE SIGNAL ;
    SHAPE ABUTMENT ;
    PORT
      LAYER M4 ;
      RECT 0.000 1864.176 0.192 1864.200 ;
    END
  END pma_rx[454]
  PIN pma_rx[455]
    DIRECTION INPUT ;
    USE SIGNAL ;
    SHAPE ABUTMENT ;
    PORT
      LAYER M4 ;
      RECT 0.000 1868.256 0.192 1868.280 ;
    END
  END pma_rx[455]
  PIN pma_rx[456]
    DIRECTION INPUT ;
    USE SIGNAL ;
    SHAPE ABUTMENT ;
    PORT
      LAYER M4 ;
      RECT 0.000 1872.288 0.192 1872.312 ;
    END
  END pma_rx[456]
  PIN pma_rx[457]
    DIRECTION INPUT ;
    USE SIGNAL ;
    SHAPE ABUTMENT ;
    PORT
      LAYER M4 ;
      RECT 0.000 1876.368 0.192 1876.392 ;
    END
  END pma_rx[457]
  PIN pma_rx[458]
    DIRECTION INPUT ;
    USE SIGNAL ;
    SHAPE ABUTMENT ;
    PORT
      LAYER M4 ;
      RECT 0.000 1880.400 0.192 1880.424 ;
    END
  END pma_rx[458]
  PIN pma_rx[459]
    DIRECTION INPUT ;
    USE SIGNAL ;
    SHAPE ABUTMENT ;
    PORT
      LAYER M4 ;
      RECT 0.000 1884.480 0.192 1884.504 ;
    END
  END pma_rx[459]
  PIN pma_rx[460]
    DIRECTION INPUT ;
    USE SIGNAL ;
    SHAPE ABUTMENT ;
    PORT
      LAYER M4 ;
      RECT 0.000 1888.560 0.192 1888.584 ;
    END
  END pma_rx[460]
  PIN pma_rx[461]
    DIRECTION INPUT ;
    USE SIGNAL ;
    SHAPE ABUTMENT ;
    PORT
      LAYER M4 ;
      RECT 0.000 1892.592 0.192 1892.616 ;
    END
  END pma_rx[461]
  PIN pma_rx[462]
    DIRECTION INPUT ;
    USE SIGNAL ;
    SHAPE ABUTMENT ;
    PORT
      LAYER M4 ;
      RECT 0.000 1896.672 0.192 1896.696 ;
    END
  END pma_rx[462]
  PIN pma_rx[463]
    DIRECTION INPUT ;
    USE SIGNAL ;
    SHAPE ABUTMENT ;
    PORT
      LAYER M4 ;
      RECT 0.000 1900.752 0.192 1900.776 ;
    END
  END pma_rx[463]
  PIN pma_rx[464]
    DIRECTION INPUT ;
    USE SIGNAL ;
    SHAPE ABUTMENT ;
    PORT
      LAYER M4 ;
      RECT 0.000 1904.784 0.192 1904.808 ;
    END
  END pma_rx[464]
  PIN pma_rx[465]
    DIRECTION INPUT ;
    USE SIGNAL ;
    SHAPE ABUTMENT ;
    PORT
      LAYER M4 ;
      RECT 0.000 1908.864 0.192 1908.888 ;
    END
  END pma_rx[465]
  PIN pma_rx[466]
    DIRECTION INPUT ;
    USE SIGNAL ;
    SHAPE ABUTMENT ;
    PORT
      LAYER M4 ;
      RECT 0.000 1912.896 0.192 1912.920 ;
    END
  END pma_rx[466]
  PIN pma_rx[467]
    DIRECTION INPUT ;
    USE SIGNAL ;
    SHAPE ABUTMENT ;
    PORT
      LAYER M4 ;
      RECT 0.000 1916.976 0.192 1917.000 ;
    END
  END pma_rx[467]
  PIN pma_rx[468]
    DIRECTION INPUT ;
    USE SIGNAL ;
    SHAPE ABUTMENT ;
    PORT
      LAYER M4 ;
      RECT 0.000 1921.056 0.192 1921.080 ;
    END
  END pma_rx[468]
  PIN pma_rx[469]
    DIRECTION INPUT ;
    USE SIGNAL ;
    SHAPE ABUTMENT ;
    PORT
      LAYER M4 ;
      RECT 0.000 1925.088 0.192 1925.112 ;
    END
  END pma_rx[469]
  PIN pma_rx[470]
    DIRECTION INPUT ;
    USE SIGNAL ;
    SHAPE ABUTMENT ;
    PORT
      LAYER M4 ;
      RECT 0.000 1929.168 0.192 1929.192 ;
    END
  END pma_rx[470]
  PIN pma_rx[471]
    DIRECTION INPUT ;
    USE SIGNAL ;
    SHAPE ABUTMENT ;
    PORT
      LAYER M4 ;
      RECT 0.000 1933.200 0.192 1933.224 ;
    END
  END pma_rx[471]
  PIN pma_rx[472]
    DIRECTION INPUT ;
    USE SIGNAL ;
    SHAPE ABUTMENT ;
    PORT
      LAYER M4 ;
      RECT 0.000 1937.280 0.192 1937.304 ;
    END
  END pma_rx[472]
  PIN pma_rx[473]
    DIRECTION INPUT ;
    USE SIGNAL ;
    SHAPE ABUTMENT ;
    PORT
      LAYER M4 ;
      RECT 0.000 1941.360 0.192 1941.384 ;
    END
  END pma_rx[473]
  PIN pma_rx[474]
    DIRECTION INPUT ;
    USE SIGNAL ;
    SHAPE ABUTMENT ;
    PORT
      LAYER M4 ;
      RECT 0.000 1945.392 0.192 1945.416 ;
    END
  END pma_rx[474]
  PIN pma_rx[475]
    DIRECTION INPUT ;
    USE SIGNAL ;
    SHAPE ABUTMENT ;
    PORT
      LAYER M4 ;
      RECT 0.000 1949.472 0.192 1949.496 ;
    END
  END pma_rx[475]
  PIN pma_rx[476]
    DIRECTION INPUT ;
    USE SIGNAL ;
    SHAPE ABUTMENT ;
    PORT
      LAYER M4 ;
      RECT 0.000 1953.504 0.192 1953.528 ;
    END
  END pma_rx[476]
  PIN pma_rx[477]
    DIRECTION INPUT ;
    USE SIGNAL ;
    SHAPE ABUTMENT ;
    PORT
      LAYER M4 ;
      RECT 0.000 1957.584 0.192 1957.608 ;
    END
  END pma_rx[477]
  PIN pma_rx[478]
    DIRECTION INPUT ;
    USE SIGNAL ;
    SHAPE ABUTMENT ;
    PORT
      LAYER M4 ;
      RECT 0.000 1961.664 0.192 1961.688 ;
    END
  END pma_rx[478]
  PIN pma_rx[479]
    DIRECTION INPUT ;
    USE SIGNAL ;
    SHAPE ABUTMENT ;
    PORT
      LAYER M4 ;
      RECT 0.000 1965.696 0.192 1965.720 ;
    END
  END pma_rx[479]
  PIN pma_rx[480]
    DIRECTION INPUT ;
    USE SIGNAL ;
    SHAPE ABUTMENT ;
    PORT
      LAYER M4 ;
      RECT 0.000 1969.776 0.192 1969.800 ;
    END
  END pma_rx[480]
  PIN pma_rx[481]
    DIRECTION INPUT ;
    USE SIGNAL ;
    SHAPE ABUTMENT ;
    PORT
      LAYER M4 ;
      RECT 0.000 1973.808 0.192 1973.832 ;
    END
  END pma_rx[481]
  PIN pma_rx[482]
    DIRECTION INPUT ;
    USE SIGNAL ;
    SHAPE ABUTMENT ;
    PORT
      LAYER M4 ;
      RECT 0.000 1977.888 0.192 1977.912 ;
    END
  END pma_rx[482]
  PIN pma_rx[483]
    DIRECTION INPUT ;
    USE SIGNAL ;
    SHAPE ABUTMENT ;
    PORT
      LAYER M4 ;
      RECT 0.000 1981.968 0.192 1981.992 ;
    END
  END pma_rx[483]
  PIN pma_rx[484]
    DIRECTION INPUT ;
    USE SIGNAL ;
    SHAPE ABUTMENT ;
    PORT
      LAYER M4 ;
      RECT 0.000 1986.000 0.192 1986.024 ;
    END
  END pma_rx[484]
  PIN pma_rx[485]
    DIRECTION INPUT ;
    USE SIGNAL ;
    SHAPE ABUTMENT ;
    PORT
      LAYER M4 ;
      RECT 0.000 1990.080 0.192 1990.104 ;
    END
  END pma_rx[485]
  PIN pma_rx[486]
    DIRECTION INPUT ;
    USE SIGNAL ;
    SHAPE ABUTMENT ;
    PORT
      LAYER M4 ;
      RECT 0.000 1994.112 0.192 1994.136 ;
    END
  END pma_rx[486]
  PIN pma_rx[487]
    DIRECTION INPUT ;
    USE SIGNAL ;
    SHAPE ABUTMENT ;
    PORT
      LAYER M4 ;
      RECT 0.000 1998.192 0.192 1998.216 ;
    END
  END pma_rx[487]
  PIN pma_rx[488]
    DIRECTION INPUT ;
    USE SIGNAL ;
    SHAPE ABUTMENT ;
    PORT
      LAYER M4 ;
      RECT 0.000 2002.272 0.192 2002.296 ;
    END
  END pma_rx[488]
  PIN pma_rx[489]
    DIRECTION INPUT ;
    USE SIGNAL ;
    SHAPE ABUTMENT ;
    PORT
      LAYER M4 ;
      RECT 0.000 2006.304 0.192 2006.328 ;
    END
  END pma_rx[489]
  PIN pma_rx[490]
    DIRECTION INPUT ;
    USE SIGNAL ;
    SHAPE ABUTMENT ;
    PORT
      LAYER M4 ;
      RECT 0.000 2010.384 0.192 2010.408 ;
    END
  END pma_rx[490]
  PIN pma_rx[491]
    DIRECTION INPUT ;
    USE SIGNAL ;
    SHAPE ABUTMENT ;
    PORT
      LAYER M4 ;
      RECT 0.000 2014.416 0.192 2014.440 ;
    END
  END pma_rx[491]
  PIN pma_rx[492]
    DIRECTION INPUT ;
    USE SIGNAL ;
    SHAPE ABUTMENT ;
    PORT
      LAYER M4 ;
      RECT 0.000 2018.496 0.192 2018.520 ;
    END
  END pma_rx[492]
  PIN pma_rx[493]
    DIRECTION INPUT ;
    USE SIGNAL ;
    SHAPE ABUTMENT ;
    PORT
      LAYER M4 ;
      RECT 0.000 2022.576 0.192 2022.600 ;
    END
  END pma_rx[493]
  PIN pma_rx[494]
    DIRECTION INPUT ;
    USE SIGNAL ;
    SHAPE ABUTMENT ;
    PORT
      LAYER M4 ;
      RECT 0.000 2026.608 0.192 2026.632 ;
    END
  END pma_rx[494]
  PIN pma_rx[495]
    DIRECTION INPUT ;
    USE SIGNAL ;
    SHAPE ABUTMENT ;
    PORT
      LAYER M4 ;
      RECT 0.000 2030.688 0.192 2030.712 ;
    END
  END pma_rx[495]
  PIN pma_rx[496]
    DIRECTION INPUT ;
    USE SIGNAL ;
    SHAPE ABUTMENT ;
    PORT
      LAYER M4 ;
      RECT 0.000 2034.720 0.192 2034.744 ;
    END
  END pma_rx[496]
  PIN pma_rx[497]
    DIRECTION INPUT ;
    USE SIGNAL ;
    SHAPE ABUTMENT ;
    PORT
      LAYER M4 ;
      RECT 0.000 2038.800 0.192 2038.824 ;
    END
  END pma_rx[497]
  PIN pma_rx[498]
    DIRECTION INPUT ;
    USE SIGNAL ;
    SHAPE ABUTMENT ;
    PORT
      LAYER M4 ;
      RECT 0.000 2042.880 0.192 2042.904 ;
    END
  END pma_rx[498]
  PIN pma_rx[499]
    DIRECTION INPUT ;
    USE SIGNAL ;
    SHAPE ABUTMENT ;
    PORT
      LAYER M4 ;
      RECT 0.000 2046.912 0.192 2046.936 ;
    END
  END pma_rx[499]
  PIN pma_rx[500]
    DIRECTION INPUT ;
    USE SIGNAL ;
    SHAPE ABUTMENT ;
    PORT
      LAYER M4 ;
      RECT 0.000 2050.992 0.192 2051.016 ;
    END
  END pma_rx[500]
  PIN pma_rx[501]
    DIRECTION INPUT ;
    USE SIGNAL ;
    SHAPE ABUTMENT ;
    PORT
      LAYER M4 ;
      RECT 0.000 2055.024 0.192 2055.048 ;
    END
  END pma_rx[501]
  PIN pma_rx[502]
    DIRECTION INPUT ;
    USE SIGNAL ;
    SHAPE ABUTMENT ;
    PORT
      LAYER M4 ;
      RECT 0.000 2059.104 0.192 2059.128 ;
    END
  END pma_rx[502]
  PIN pma_rx[503]
    DIRECTION INPUT ;
    USE SIGNAL ;
    SHAPE ABUTMENT ;
    PORT
      LAYER M4 ;
      RECT 0.000 2063.184 0.192 2063.208 ;
    END
  END pma_rx[503]
  PIN pma_rx[504]
    DIRECTION INPUT ;
    USE SIGNAL ;
    SHAPE ABUTMENT ;
    PORT
      LAYER M4 ;
      RECT 0.000 2067.216 0.192 2067.240 ;
    END
  END pma_rx[504]
  PIN pma_rx[505]
    DIRECTION INPUT ;
    USE SIGNAL ;
    SHAPE ABUTMENT ;
    PORT
      LAYER M4 ;
      RECT 0.000 2071.296 0.192 2071.320 ;
    END
  END pma_rx[505]
  PIN pma_rx[506]
    DIRECTION INPUT ;
    USE SIGNAL ;
    SHAPE ABUTMENT ;
    PORT
      LAYER M4 ;
      RECT 0.000 2075.376 0.192 2075.400 ;
    END
  END pma_rx[506]
  PIN pma_rx[507]
    DIRECTION INPUT ;
    USE SIGNAL ;
    SHAPE ABUTMENT ;
    PORT
      LAYER M4 ;
      RECT 0.000 2079.408 0.192 2079.432 ;
    END
  END pma_rx[507]
  PIN pma_rx[508]
    DIRECTION INPUT ;
    USE SIGNAL ;
    SHAPE ABUTMENT ;
    PORT
      LAYER M4 ;
      RECT 0.000 2083.488 0.192 2083.512 ;
    END
  END pma_rx[508]
  PIN pma_rx[509]
    DIRECTION INPUT ;
    USE SIGNAL ;
    SHAPE ABUTMENT ;
    PORT
      LAYER M4 ;
      RECT 0.000 2087.520 0.192 2087.544 ;
    END
  END pma_rx[509]
  PIN pma_rx[510]
    DIRECTION INPUT ;
    USE SIGNAL ;
    SHAPE ABUTMENT ;
    PORT
      LAYER M4 ;
      RECT 0.000 2091.600 0.192 2091.624 ;
    END
  END pma_rx[510]
  PIN pma_rx[511]
    DIRECTION INPUT ;
    USE SIGNAL ;
    SHAPE ABUTMENT ;
    PORT
      LAYER M4 ;
      RECT 0.000 2095.680 0.192 2095.704 ;
    END
  END pma_rx[511]
  PIN pma_rx[512]
    DIRECTION INPUT ;
    USE SIGNAL ;
    SHAPE ABUTMENT ;
    PORT
      LAYER M4 ;
      RECT 0.000 2099.712 0.192 2099.736 ;
    END
  END pma_rx[512]
  PIN pma_rx[513]
    DIRECTION INPUT ;
    USE SIGNAL ;
    SHAPE ABUTMENT ;
    PORT
      LAYER M4 ;
      RECT 0.000 2103.792 0.192 2103.816 ;
    END
  END pma_rx[513]
  PIN pma_rx[514]
    DIRECTION INPUT ;
    USE SIGNAL ;
    SHAPE ABUTMENT ;
    PORT
      LAYER M4 ;
      RECT 0.000 2107.824 0.192 2107.848 ;
    END
  END pma_rx[514]
  PIN pma_rx[515]
    DIRECTION INPUT ;
    USE SIGNAL ;
    SHAPE ABUTMENT ;
    PORT
      LAYER M4 ;
      RECT 0.000 2111.904 0.192 2111.928 ;
    END
  END pma_rx[515]
  PIN pma_rx[516]
    DIRECTION INPUT ;
    USE SIGNAL ;
    SHAPE ABUTMENT ;
    PORT
      LAYER M4 ;
      RECT 0.000 2115.984 0.192 2116.008 ;
    END
  END pma_rx[516]
  PIN pma_rx[517]
    DIRECTION INPUT ;
    USE SIGNAL ;
    SHAPE ABUTMENT ;
    PORT
      LAYER M4 ;
      RECT 0.000 2120.016 0.192 2120.040 ;
    END
  END pma_rx[517]
  PIN pma_rx[518]
    DIRECTION INPUT ;
    USE SIGNAL ;
    SHAPE ABUTMENT ;
    PORT
      LAYER M4 ;
      RECT 0.000 2124.096 0.192 2124.120 ;
    END
  END pma_rx[518]
  PIN pma_rx[519]
    DIRECTION INPUT ;
    USE SIGNAL ;
    SHAPE ABUTMENT ;
    PORT
      LAYER M4 ;
      RECT 0.000 2128.128 0.192 2128.152 ;
    END
  END pma_rx[519]
  PIN pma_rx[520]
    DIRECTION INPUT ;
    USE SIGNAL ;
    SHAPE ABUTMENT ;
    PORT
      LAYER M4 ;
      RECT 0.000 2132.208 0.192 2132.232 ;
    END
  END pma_rx[520]
  PIN pma_rx[521]
    DIRECTION INPUT ;
    USE SIGNAL ;
    SHAPE ABUTMENT ;
    PORT
      LAYER M4 ;
      RECT 0.000 2136.288 0.192 2136.312 ;
    END
  END pma_rx[521]
  PIN pma_rx[522]
    DIRECTION INPUT ;
    USE SIGNAL ;
    SHAPE ABUTMENT ;
    PORT
      LAYER M4 ;
      RECT 0.000 2140.320 0.192 2140.344 ;
    END
  END pma_rx[522]
  PIN pma_rx[523]
    DIRECTION INPUT ;
    USE SIGNAL ;
    SHAPE ABUTMENT ;
    PORT
      LAYER M4 ;
      RECT 0.000 2144.400 0.192 2144.424 ;
    END
  END pma_rx[523]
  PIN pma_rx[524]
    DIRECTION INPUT ;
    USE SIGNAL ;
    SHAPE ABUTMENT ;
    PORT
      LAYER M4 ;
      RECT 0.000 2148.432 0.192 2148.456 ;
    END
  END pma_rx[524]
  PIN pma_rx[525]
    DIRECTION INPUT ;
    USE SIGNAL ;
    SHAPE ABUTMENT ;
    PORT
      LAYER M4 ;
      RECT 0.000 2152.512 0.192 2152.536 ;
    END
  END pma_rx[525]
  PIN pma_rx[526]
    DIRECTION INPUT ;
    USE SIGNAL ;
    SHAPE ABUTMENT ;
    PORT
      LAYER M4 ;
      RECT 0.000 2156.592 0.192 2156.616 ;
    END
  END pma_rx[526]
  PIN pma_rx[527]
    DIRECTION INPUT ;
    USE SIGNAL ;
    SHAPE ABUTMENT ;
    PORT
      LAYER M4 ;
      RECT 0.000 2160.624 0.192 2160.648 ;
    END
  END pma_rx[527]
  PIN pma_rx[528]
    DIRECTION INPUT ;
    USE SIGNAL ;
    SHAPE ABUTMENT ;
    PORT
      LAYER M4 ;
      RECT 0.000 2164.704 0.192 2164.728 ;
    END
  END pma_rx[528]
  PIN pma_rx[529]
    DIRECTION INPUT ;
    USE SIGNAL ;
    SHAPE ABUTMENT ;
    PORT
      LAYER M4 ;
      RECT 0.000 2168.736 0.192 2168.760 ;
    END
  END pma_rx[529]
  PIN pma_rx[530]
    DIRECTION INPUT ;
    USE SIGNAL ;
    SHAPE ABUTMENT ;
    PORT
      LAYER M4 ;
      RECT 0.000 2172.816 0.192 2172.840 ;
    END
  END pma_rx[530]
  PIN pma_rx[531]
    DIRECTION INPUT ;
    USE SIGNAL ;
    SHAPE ABUTMENT ;
    PORT
      LAYER M4 ;
      RECT 0.000 2176.896 0.192 2176.920 ;
    END
  END pma_rx[531]
  PIN pma_rx[532]
    DIRECTION INPUT ;
    USE SIGNAL ;
    SHAPE ABUTMENT ;
    PORT
      LAYER M4 ;
      RECT 0.000 2180.928 0.192 2180.952 ;
    END
  END pma_rx[532]
  PIN pma_rx[533]
    DIRECTION INPUT ;
    USE SIGNAL ;
    SHAPE ABUTMENT ;
    PORT
      LAYER M4 ;
      RECT 0.000 2185.008 0.192 2185.032 ;
    END
  END pma_rx[533]
  PIN pma_rx[534]
    DIRECTION INPUT ;
    USE SIGNAL ;
    SHAPE ABUTMENT ;
    PORT
      LAYER M4 ;
      RECT 0.000 2189.040 0.192 2189.064 ;
    END
  END pma_rx[534]
  PIN pma_rx[535]
    DIRECTION INPUT ;
    USE SIGNAL ;
    SHAPE ABUTMENT ;
    PORT
      LAYER M4 ;
      RECT 0.000 2193.120 0.192 2193.144 ;
    END
  END pma_rx[535]
  PIN pma_rx[536]
    DIRECTION INPUT ;
    USE SIGNAL ;
    SHAPE ABUTMENT ;
    PORT
      LAYER M4 ;
      RECT 0.000 2197.200 0.192 2197.224 ;
    END
  END pma_rx[536]
  PIN pma_rx[537]
    DIRECTION INPUT ;
    USE SIGNAL ;
    SHAPE ABUTMENT ;
    PORT
      LAYER M4 ;
      RECT 0.000 2201.232 0.192 2201.256 ;
    END
  END pma_rx[537]
  PIN pma_rx[538]
    DIRECTION INPUT ;
    USE SIGNAL ;
    SHAPE ABUTMENT ;
    PORT
      LAYER M4 ;
      RECT 0.000 2205.312 0.192 2205.336 ;
    END
  END pma_rx[538]
  PIN pma_rx[539]
    DIRECTION INPUT ;
    USE SIGNAL ;
    SHAPE ABUTMENT ;
    PORT
      LAYER M4 ;
      RECT 0.000 2209.344 0.192 2209.368 ;
    END
  END pma_rx[539]
  PIN pma_rx[540]
    DIRECTION INPUT ;
    USE SIGNAL ;
    SHAPE ABUTMENT ;
    PORT
      LAYER M4 ;
      RECT 0.000 2213.424 0.192 2213.448 ;
    END
  END pma_rx[540]
  PIN pma_rx[541]
    DIRECTION INPUT ;
    USE SIGNAL ;
    SHAPE ABUTMENT ;
    PORT
      LAYER M4 ;
      RECT 0.000 2217.504 0.192 2217.528 ;
    END
  END pma_rx[541]
  PIN pma_rx[542]
    DIRECTION INPUT ;
    USE SIGNAL ;
    SHAPE ABUTMENT ;
    PORT
      LAYER M4 ;
      RECT 0.000 2221.536 0.192 2221.560 ;
    END
  END pma_rx[542]
  PIN pma_rx[543]
    DIRECTION INPUT ;
    USE SIGNAL ;
    SHAPE ABUTMENT ;
    PORT
      LAYER M4 ;
      RECT 0.000 2225.616 0.192 2225.640 ;
    END
  END pma_rx[543]
  PIN q[0]
    DIRECTION OUTPUT ;
    USE SIGNAL ;
    SHAPE ABUTMENT ;
    PORT
      LAYER M5 ;
      RECT 4.512 2250.024 4.536 2250.216 ;
    END
  END q[0]
  PIN q[1]
    DIRECTION OUTPUT ;
    USE SIGNAL ;
    SHAPE ABUTMENT ;
    PORT
      LAYER M5 ;
      RECT 4.704 2250.024 4.728 2250.216 ;
    END
  END q[1]
  PIN q[2]
    DIRECTION OUTPUT ;
    USE SIGNAL ;
    SHAPE ABUTMENT ;
    PORT
      LAYER M5 ;
      RECT 4.944 2250.024 4.968 2250.216 ;
    END
  END q[2]
  PIN q[3]
    DIRECTION OUTPUT ;
    USE SIGNAL ;
    SHAPE ABUTMENT ;
    PORT
      LAYER M5 ;
      RECT 5.136 2250.024 5.160 2250.216 ;
    END
  END q[3]
  PIN q[4]
    DIRECTION OUTPUT ;
    USE SIGNAL ;
    SHAPE ABUTMENT ;
    PORT
      LAYER M5 ;
      RECT 5.376 2250.024 5.400 2250.216 ;
    END
  END q[4]
  PIN q[5]
    DIRECTION OUTPUT ;
    USE SIGNAL ;
    SHAPE ABUTMENT ;
    PORT
      LAYER M5 ;
      RECT 5.568 2250.024 5.592 2250.216 ;
    END
  END q[5]
  PIN q[6]
    DIRECTION OUTPUT ;
    USE SIGNAL ;
    SHAPE ABUTMENT ;
    PORT
      LAYER M5 ;
      RECT 5.808 2250.024 5.832 2250.216 ;
    END
  END q[6]
  PIN q[7]
    DIRECTION OUTPUT ;
    USE SIGNAL ;
    SHAPE ABUTMENT ;
    PORT
      LAYER M5 ;
      RECT 6.048 2250.024 6.072 2250.216 ;
    END
  END q[7]
  PIN q[8]
    DIRECTION OUTPUT ;
    USE SIGNAL ;
    SHAPE ABUTMENT ;
    PORT
      LAYER M5 ;
      RECT 6.240 2250.024 6.264 2250.216 ;
    END
  END q[8]
  PIN q[9]
    DIRECTION OUTPUT ;
    USE SIGNAL ;
    SHAPE ABUTMENT ;
    PORT
      LAYER M5 ;
      RECT 6.480 2250.024 6.504 2250.216 ;
    END
  END q[9]
  PIN q[10]
    DIRECTION OUTPUT ;
    USE SIGNAL ;
    SHAPE ABUTMENT ;
    PORT
      LAYER M5 ;
      RECT 6.672 2250.024 6.696 2250.216 ;
    END
  END q[10]
  PIN q[11]
    DIRECTION OUTPUT ;
    USE SIGNAL ;
    SHAPE ABUTMENT ;
    PORT
      LAYER M5 ;
      RECT 6.912 2250.024 6.936 2250.216 ;
    END
  END q[11]
  PIN q[12]
    DIRECTION OUTPUT ;
    USE SIGNAL ;
    SHAPE ABUTMENT ;
    PORT
      LAYER M5 ;
      RECT 7.152 2250.024 7.176 2250.216 ;
    END
  END q[12]
  PIN q[13]
    DIRECTION OUTPUT ;
    USE SIGNAL ;
    SHAPE ABUTMENT ;
    PORT
      LAYER M5 ;
      RECT 7.344 2250.024 7.368 2250.216 ;
    END
  END q[13]
  PIN q[14]
    DIRECTION OUTPUT ;
    USE SIGNAL ;
    SHAPE ABUTMENT ;
    PORT
      LAYER M5 ;
      RECT 7.584 2250.024 7.608 2250.216 ;
    END
  END q[14]
  PIN q[15]
    DIRECTION OUTPUT ;
    USE SIGNAL ;
    SHAPE ABUTMENT ;
    PORT
      LAYER M5 ;
      RECT 7.776 2250.024 7.800 2250.216 ;
    END
  END q[15]
  PIN q[16]
    DIRECTION OUTPUT ;
    USE SIGNAL ;
    SHAPE ABUTMENT ;
    PORT
      LAYER M5 ;
      RECT 8.016 2250.024 8.040 2250.216 ;
    END
  END q[16]
  PIN q[17]
    DIRECTION OUTPUT ;
    USE SIGNAL ;
    SHAPE ABUTMENT ;
    PORT
      LAYER M5 ;
      RECT 8.256 2250.024 8.280 2250.216 ;
    END
  END q[17]
  PIN q[18]
    DIRECTION OUTPUT ;
    USE SIGNAL ;
    SHAPE ABUTMENT ;
    PORT
      LAYER M5 ;
      RECT 8.448 2250.024 8.472 2250.216 ;
    END
  END q[18]
  PIN q[19]
    DIRECTION OUTPUT ;
    USE SIGNAL ;
    SHAPE ABUTMENT ;
    PORT
      LAYER M5 ;
      RECT 8.688 2250.024 8.712 2250.216 ;
    END
  END q[19]
  PIN q[20]
    DIRECTION OUTPUT ;
    USE SIGNAL ;
    SHAPE ABUTMENT ;
    PORT
      LAYER M5 ;
      RECT 8.880 2250.024 8.904 2250.216 ;
    END
  END q[20]
  PIN q[21]
    DIRECTION OUTPUT ;
    USE SIGNAL ;
    SHAPE ABUTMENT ;
    PORT
      LAYER M5 ;
      RECT 9.120 2250.024 9.144 2250.216 ;
    END
  END q[21]
  PIN q[22]
    DIRECTION OUTPUT ;
    USE SIGNAL ;
    SHAPE ABUTMENT ;
    PORT
      LAYER M5 ;
      RECT 9.360 2250.024 9.384 2250.216 ;
    END
  END q[22]
  PIN q[23]
    DIRECTION OUTPUT ;
    USE SIGNAL ;
    SHAPE ABUTMENT ;
    PORT
      LAYER M5 ;
      RECT 9.552 2250.024 9.576 2250.216 ;
    END
  END q[23]
  PIN q[24]
    DIRECTION OUTPUT ;
    USE SIGNAL ;
    SHAPE ABUTMENT ;
    PORT
      LAYER M5 ;
      RECT 9.792 2250.024 9.816 2250.216 ;
    END
  END q[24]
  PIN q[25]
    DIRECTION OUTPUT ;
    USE SIGNAL ;
    SHAPE ABUTMENT ;
    PORT
      LAYER M5 ;
      RECT 9.984 2250.024 10.008 2250.216 ;
    END
  END q[25]
  PIN q[26]
    DIRECTION OUTPUT ;
    USE SIGNAL ;
    SHAPE ABUTMENT ;
    PORT
      LAYER M5 ;
      RECT 10.224 2250.024 10.248 2250.216 ;
    END
  END q[26]
  PIN q[27]
    DIRECTION OUTPUT ;
    USE SIGNAL ;
    SHAPE ABUTMENT ;
    PORT
      LAYER M5 ;
      RECT 10.464 2250.024 10.488 2250.216 ;
    END
  END q[27]
  PIN q[28]
    DIRECTION OUTPUT ;
    USE SIGNAL ;
    SHAPE ABUTMENT ;
    PORT
      LAYER M5 ;
      RECT 10.656 2250.024 10.680 2250.216 ;
    END
  END q[28]
  PIN q[29]
    DIRECTION OUTPUT ;
    USE SIGNAL ;
    SHAPE ABUTMENT ;
    PORT
      LAYER M5 ;
      RECT 10.896 2250.024 10.920 2250.216 ;
    END
  END q[29]
  PIN q[30]
    DIRECTION OUTPUT ;
    USE SIGNAL ;
    SHAPE ABUTMENT ;
    PORT
      LAYER M5 ;
      RECT 11.088 2250.024 11.112 2250.216 ;
    END
  END q[30]
  PIN q[31]
    DIRECTION OUTPUT ;
    USE SIGNAL ;
    SHAPE ABUTMENT ;
    PORT
      LAYER M5 ;
      RECT 11.328 2250.024 11.352 2250.216 ;
    END
  END q[31]
  PIN q[32]
    DIRECTION OUTPUT ;
    USE SIGNAL ;
    SHAPE ABUTMENT ;
    PORT
      LAYER M5 ;
      RECT 11.568 2250.024 11.592 2250.216 ;
    END
  END q[32]
  PIN q[33]
    DIRECTION OUTPUT ;
    USE SIGNAL ;
    SHAPE ABUTMENT ;
    PORT
      LAYER M5 ;
      RECT 11.760 2250.024 11.784 2250.216 ;
    END
  END q[33]
  PIN q[34]
    DIRECTION OUTPUT ;
    USE SIGNAL ;
    SHAPE ABUTMENT ;
    PORT
      LAYER M5 ;
      RECT 12.000 2250.024 12.024 2250.216 ;
    END
  END q[34]
  PIN q[35]
    DIRECTION OUTPUT ;
    USE SIGNAL ;
    SHAPE ABUTMENT ;
    PORT
      LAYER M5 ;
      RECT 12.192 2250.024 12.216 2250.216 ;
    END
  END q[35]
  PIN q[36]
    DIRECTION OUTPUT ;
    USE SIGNAL ;
    SHAPE ABUTMENT ;
    PORT
      LAYER M5 ;
      RECT 12.432 2250.024 12.456 2250.216 ;
    END
  END q[36]
  PIN q[37]
    DIRECTION OUTPUT ;
    USE SIGNAL ;
    SHAPE ABUTMENT ;
    PORT
      LAYER M5 ;
      RECT 12.672 2250.024 12.696 2250.216 ;
    END
  END q[37]
  PIN q[38]
    DIRECTION OUTPUT ;
    USE SIGNAL ;
    SHAPE ABUTMENT ;
    PORT
      LAYER M5 ;
      RECT 12.864 2250.024 12.888 2250.216 ;
    END
  END q[38]
  PIN q[39]
    DIRECTION OUTPUT ;
    USE SIGNAL ;
    SHAPE ABUTMENT ;
    PORT
      LAYER M5 ;
      RECT 13.104 2250.024 13.128 2250.216 ;
    END
  END q[39]
  PIN q[40]
    DIRECTION OUTPUT ;
    USE SIGNAL ;
    SHAPE ABUTMENT ;
    PORT
      LAYER M5 ;
      RECT 13.296 2250.024 13.320 2250.216 ;
    END
  END q[40]
  PIN q[41]
    DIRECTION OUTPUT ;
    USE SIGNAL ;
    SHAPE ABUTMENT ;
    PORT
      LAYER M5 ;
      RECT 13.536 2250.024 13.560 2250.216 ;
    END
  END q[41]
  PIN q[42]
    DIRECTION OUTPUT ;
    USE SIGNAL ;
    SHAPE ABUTMENT ;
    PORT
      LAYER M5 ;
      RECT 13.776 2250.024 13.800 2250.216 ;
    END
  END q[42]
  PIN q[43]
    DIRECTION OUTPUT ;
    USE SIGNAL ;
    SHAPE ABUTMENT ;
    PORT
      LAYER M5 ;
      RECT 13.968 2250.024 13.992 2250.216 ;
    END
  END q[43]
  PIN q[44]
    DIRECTION OUTPUT ;
    USE SIGNAL ;
    SHAPE ABUTMENT ;
    PORT
      LAYER M5 ;
      RECT 14.208 2250.024 14.232 2250.216 ;
    END
  END q[44]
  PIN q[45]
    DIRECTION OUTPUT ;
    USE SIGNAL ;
    SHAPE ABUTMENT ;
    PORT
      LAYER M5 ;
      RECT 14.400 2250.024 14.424 2250.216 ;
    END
  END q[45]
  PIN q[46]
    DIRECTION OUTPUT ;
    USE SIGNAL ;
    SHAPE ABUTMENT ;
    PORT
      LAYER M5 ;
      RECT 14.640 2250.024 14.664 2250.216 ;
    END
  END q[46]
  PIN q[47]
    DIRECTION OUTPUT ;
    USE SIGNAL ;
    SHAPE ABUTMENT ;
    PORT
      LAYER M5 ;
      RECT 14.832 2250.024 14.856 2250.216 ;
    END
  END q[47]
  PIN q[48]
    DIRECTION OUTPUT ;
    USE SIGNAL ;
    SHAPE ABUTMENT ;
    PORT
      LAYER M5 ;
      RECT 15.072 2250.024 15.096 2250.216 ;
    END
  END q[48]
  PIN q[49]
    DIRECTION OUTPUT ;
    USE SIGNAL ;
    SHAPE ABUTMENT ;
    PORT
      LAYER M5 ;
      RECT 15.312 2250.024 15.336 2250.216 ;
    END
  END q[49]
  PIN q[50]
    DIRECTION OUTPUT ;
    USE SIGNAL ;
    SHAPE ABUTMENT ;
    PORT
      LAYER M5 ;
      RECT 15.504 2250.024 15.528 2250.216 ;
    END
  END q[50]
  PIN q[51]
    DIRECTION OUTPUT ;
    USE SIGNAL ;
    SHAPE ABUTMENT ;
    PORT
      LAYER M5 ;
      RECT 15.744 2250.024 15.768 2250.216 ;
    END
  END q[51]
  PIN q[52]
    DIRECTION OUTPUT ;
    USE SIGNAL ;
    SHAPE ABUTMENT ;
    PORT
      LAYER M5 ;
      RECT 15.936 2250.024 15.960 2250.216 ;
    END
  END q[52]
  PIN q[53]
    DIRECTION OUTPUT ;
    USE SIGNAL ;
    SHAPE ABUTMENT ;
    PORT
      LAYER M5 ;
      RECT 16.176 2250.024 16.200 2250.216 ;
    END
  END q[53]
  PIN q[54]
    DIRECTION OUTPUT ;
    USE SIGNAL ;
    SHAPE ABUTMENT ;
    PORT
      LAYER M5 ;
      RECT 16.416 2250.024 16.440 2250.216 ;
    END
  END q[54]
  PIN q[55]
    DIRECTION OUTPUT ;
    USE SIGNAL ;
    SHAPE ABUTMENT ;
    PORT
      LAYER M5 ;
      RECT 16.608 2250.024 16.632 2250.216 ;
    END
  END q[55]
  PIN q[56]
    DIRECTION OUTPUT ;
    USE SIGNAL ;
    SHAPE ABUTMENT ;
    PORT
      LAYER M5 ;
      RECT 16.848 2250.024 16.872 2250.216 ;
    END
  END q[56]
  PIN q[57]
    DIRECTION OUTPUT ;
    USE SIGNAL ;
    SHAPE ABUTMENT ;
    PORT
      LAYER M5 ;
      RECT 17.040 2250.024 17.064 2250.216 ;
    END
  END q[57]
  PIN q[58]
    DIRECTION OUTPUT ;
    USE SIGNAL ;
    SHAPE ABUTMENT ;
    PORT
      LAYER M5 ;
      RECT 17.280 2250.024 17.304 2250.216 ;
    END
  END q[58]
  PIN q[59]
    DIRECTION OUTPUT ;
    USE SIGNAL ;
    SHAPE ABUTMENT ;
    PORT
      LAYER M5 ;
      RECT 17.520 2250.024 17.544 2250.216 ;
    END
  END q[59]
  PIN q[60]
    DIRECTION OUTPUT ;
    USE SIGNAL ;
    SHAPE ABUTMENT ;
    PORT
      LAYER M5 ;
      RECT 17.712 2250.024 17.736 2250.216 ;
    END
  END q[60]
  PIN q[61]
    DIRECTION OUTPUT ;
    USE SIGNAL ;
    SHAPE ABUTMENT ;
    PORT
      LAYER M5 ;
      RECT 17.952 2250.024 17.976 2250.216 ;
    END
  END q[61]
  PIN q[62]
    DIRECTION OUTPUT ;
    USE SIGNAL ;
    SHAPE ABUTMENT ;
    PORT
      LAYER M5 ;
      RECT 18.144 2250.024 18.168 2250.216 ;
    END
  END q[62]
  PIN q[63]
    DIRECTION OUTPUT ;
    USE SIGNAL ;
    SHAPE ABUTMENT ;
    PORT
      LAYER M5 ;
      RECT 18.384 2250.024 18.408 2250.216 ;
    END
  END q[63]
  PIN q[64]
    DIRECTION OUTPUT ;
    USE SIGNAL ;
    SHAPE ABUTMENT ;
    PORT
      LAYER M5 ;
      RECT 18.624 2250.024 18.648 2250.216 ;
    END
  END q[64]
  PIN q[65]
    DIRECTION OUTPUT ;
    USE SIGNAL ;
    SHAPE ABUTMENT ;
    PORT
      LAYER M5 ;
      RECT 18.816 2250.024 18.840 2250.216 ;
    END
  END q[65]
  PIN q[66]
    DIRECTION OUTPUT ;
    USE SIGNAL ;
    SHAPE ABUTMENT ;
    PORT
      LAYER M5 ;
      RECT 19.056 2250.024 19.080 2250.216 ;
    END
  END q[66]
  PIN q[67]
    DIRECTION OUTPUT ;
    USE SIGNAL ;
    SHAPE ABUTMENT ;
    PORT
      LAYER M5 ;
      RECT 19.248 2250.024 19.272 2250.216 ;
    END
  END q[67]
  PIN q[68]
    DIRECTION OUTPUT ;
    USE SIGNAL ;
    SHAPE ABUTMENT ;
    PORT
      LAYER M5 ;
      RECT 19.488 2250.024 19.512 2250.216 ;
    END
  END q[68]
  PIN q[69]
    DIRECTION OUTPUT ;
    USE SIGNAL ;
    SHAPE ABUTMENT ;
    PORT
      LAYER M5 ;
      RECT 19.728 2250.024 19.752 2250.216 ;
    END
  END q[69]
  PIN q[70]
    DIRECTION OUTPUT ;
    USE SIGNAL ;
    SHAPE ABUTMENT ;
    PORT
      LAYER M5 ;
      RECT 19.920 2250.024 19.944 2250.216 ;
    END
  END q[70]
  PIN q[71]
    DIRECTION OUTPUT ;
    USE SIGNAL ;
    SHAPE ABUTMENT ;
    PORT
      LAYER M5 ;
      RECT 20.160 2250.024 20.184 2250.216 ;
    END
  END q[71]
  PIN q[72]
    DIRECTION OUTPUT ;
    USE SIGNAL ;
    SHAPE ABUTMENT ;
    PORT
      LAYER M5 ;
      RECT 20.352 2250.024 20.376 2250.216 ;
    END
  END q[72]
  PIN q[73]
    DIRECTION OUTPUT ;
    USE SIGNAL ;
    SHAPE ABUTMENT ;
    PORT
      LAYER M5 ;
      RECT 20.592 2250.024 20.616 2250.216 ;
    END
  END q[73]
  PIN q[74]
    DIRECTION OUTPUT ;
    USE SIGNAL ;
    SHAPE ABUTMENT ;
    PORT
      LAYER M5 ;
      RECT 20.832 2250.024 20.856 2250.216 ;
    END
  END q[74]
  PIN q[75]
    DIRECTION OUTPUT ;
    USE SIGNAL ;
    SHAPE ABUTMENT ;
    PORT
      LAYER M5 ;
      RECT 21.024 2250.024 21.048 2250.216 ;
    END
  END q[75]
  PIN q[76]
    DIRECTION OUTPUT ;
    USE SIGNAL ;
    SHAPE ABUTMENT ;
    PORT
      LAYER M5 ;
      RECT 21.264 2250.024 21.288 2250.216 ;
    END
  END q[76]
  PIN q[77]
    DIRECTION OUTPUT ;
    USE SIGNAL ;
    SHAPE ABUTMENT ;
    PORT
      LAYER M5 ;
      RECT 21.456 2250.024 21.480 2250.216 ;
    END
  END q[77]
  PIN q[78]
    DIRECTION OUTPUT ;
    USE SIGNAL ;
    SHAPE ABUTMENT ;
    PORT
      LAYER M5 ;
      RECT 21.696 2250.024 21.720 2250.216 ;
    END
  END q[78]
  PIN q[79]
    DIRECTION OUTPUT ;
    USE SIGNAL ;
    SHAPE ABUTMENT ;
    PORT
      LAYER M5 ;
      RECT 21.936 2250.024 21.960 2250.216 ;
    END
  END q[79]
  PIN q[80]
    DIRECTION OUTPUT ;
    USE SIGNAL ;
    SHAPE ABUTMENT ;
    PORT
      LAYER M5 ;
      RECT 22.128 2250.024 22.152 2250.216 ;
    END
  END q[80]
  PIN q[81]
    DIRECTION OUTPUT ;
    USE SIGNAL ;
    SHAPE ABUTMENT ;
    PORT
      LAYER M5 ;
      RECT 22.368 2250.024 22.392 2250.216 ;
    END
  END q[81]
  PIN q[82]
    DIRECTION OUTPUT ;
    USE SIGNAL ;
    SHAPE ABUTMENT ;
    PORT
      LAYER M5 ;
      RECT 22.560 2250.024 22.584 2250.216 ;
    END
  END q[82]
  PIN q[83]
    DIRECTION OUTPUT ;
    USE SIGNAL ;
    SHAPE ABUTMENT ;
    PORT
      LAYER M5 ;
      RECT 22.800 2250.024 22.824 2250.216 ;
    END
  END q[83]
  PIN q[84]
    DIRECTION OUTPUT ;
    USE SIGNAL ;
    SHAPE ABUTMENT ;
    PORT
      LAYER M5 ;
      RECT 23.040 2250.024 23.064 2250.216 ;
    END
  END q[84]
  PIN q[85]
    DIRECTION OUTPUT ;
    USE SIGNAL ;
    SHAPE ABUTMENT ;
    PORT
      LAYER M5 ;
      RECT 23.232 2250.024 23.256 2250.216 ;
    END
  END q[85]
  PIN q[86]
    DIRECTION OUTPUT ;
    USE SIGNAL ;
    SHAPE ABUTMENT ;
    PORT
      LAYER M5 ;
      RECT 23.472 2250.024 23.496 2250.216 ;
    END
  END q[86]
  PIN q[87]
    DIRECTION OUTPUT ;
    USE SIGNAL ;
    SHAPE ABUTMENT ;
    PORT
      LAYER M5 ;
      RECT 23.664 2250.024 23.688 2250.216 ;
    END
  END q[87]
  PIN q[88]
    DIRECTION OUTPUT ;
    USE SIGNAL ;
    SHAPE ABUTMENT ;
    PORT
      LAYER M5 ;
      RECT 23.904 2250.024 23.928 2250.216 ;
    END
  END q[88]
  PIN q[89]
    DIRECTION OUTPUT ;
    USE SIGNAL ;
    SHAPE ABUTMENT ;
    PORT
      LAYER M5 ;
      RECT 24.144 2250.024 24.168 2250.216 ;
    END
  END q[89]
  PIN q[90]
    DIRECTION OUTPUT ;
    USE SIGNAL ;
    SHAPE ABUTMENT ;
    PORT
      LAYER M5 ;
      RECT 24.336 2250.024 24.360 2250.216 ;
    END
  END q[90]
  PIN q[91]
    DIRECTION OUTPUT ;
    USE SIGNAL ;
    SHAPE ABUTMENT ;
    PORT
      LAYER M5 ;
      RECT 24.576 2250.024 24.600 2250.216 ;
    END
  END q[91]
  PIN q[92]
    DIRECTION OUTPUT ;
    USE SIGNAL ;
    SHAPE ABUTMENT ;
    PORT
      LAYER M5 ;
      RECT 24.768 2250.024 24.792 2250.216 ;
    END
  END q[92]
  PIN q[93]
    DIRECTION OUTPUT ;
    USE SIGNAL ;
    SHAPE ABUTMENT ;
    PORT
      LAYER M5 ;
      RECT 25.008 2250.024 25.032 2250.216 ;
    END
  END q[93]
  PIN q[94]
    DIRECTION OUTPUT ;
    USE SIGNAL ;
    SHAPE ABUTMENT ;
    PORT
      LAYER M5 ;
      RECT 25.200 2250.024 25.224 2250.216 ;
    END
  END q[94]
  PIN q[95]
    DIRECTION OUTPUT ;
    USE SIGNAL ;
    SHAPE ABUTMENT ;
    PORT
      LAYER M5 ;
      RECT 25.440 2250.024 25.464 2250.216 ;
    END
  END q[95]
  PIN q[96]
    DIRECTION OUTPUT ;
    USE SIGNAL ;
    SHAPE ABUTMENT ;
    PORT
      LAYER M5 ;
      RECT 25.680 2250.024 25.704 2250.216 ;
    END
  END q[96]
  PIN q[97]
    DIRECTION OUTPUT ;
    USE SIGNAL ;
    SHAPE ABUTMENT ;
    PORT
      LAYER M5 ;
      RECT 25.872 2250.024 25.896 2250.216 ;
    END
  END q[97]
  PIN q[98]
    DIRECTION OUTPUT ;
    USE SIGNAL ;
    SHAPE ABUTMENT ;
    PORT
      LAYER M5 ;
      RECT 26.112 2250.024 26.136 2250.216 ;
    END
  END q[98]
  PIN q[99]
    DIRECTION OUTPUT ;
    USE SIGNAL ;
    SHAPE ABUTMENT ;
    PORT
      LAYER M5 ;
      RECT 26.304 2250.024 26.328 2250.216 ;
    END
  END q[99]
  PIN q[100]
    DIRECTION OUTPUT ;
    USE SIGNAL ;
    SHAPE ABUTMENT ;
    PORT
      LAYER M5 ;
      RECT 26.544 2250.024 26.568 2250.216 ;
    END
  END q[100]
  PIN q[101]
    DIRECTION OUTPUT ;
    USE SIGNAL ;
    SHAPE ABUTMENT ;
    PORT
      LAYER M5 ;
      RECT 26.784 2250.024 26.808 2250.216 ;
    END
  END q[101]
  PIN q[102]
    DIRECTION OUTPUT ;
    USE SIGNAL ;
    SHAPE ABUTMENT ;
    PORT
      LAYER M5 ;
      RECT 26.976 2250.024 27.000 2250.216 ;
    END
  END q[102]
  PIN q[103]
    DIRECTION OUTPUT ;
    USE SIGNAL ;
    SHAPE ABUTMENT ;
    PORT
      LAYER M5 ;
      RECT 27.216 2250.024 27.240 2250.216 ;
    END
  END q[103]
  PIN q[104]
    DIRECTION OUTPUT ;
    USE SIGNAL ;
    SHAPE ABUTMENT ;
    PORT
      LAYER M5 ;
      RECT 27.408 2250.024 27.432 2250.216 ;
    END
  END q[104]
  PIN q[105]
    DIRECTION OUTPUT ;
    USE SIGNAL ;
    SHAPE ABUTMENT ;
    PORT
      LAYER M5 ;
      RECT 27.648 2250.024 27.672 2250.216 ;
    END
  END q[105]
  PIN q[106]
    DIRECTION OUTPUT ;
    USE SIGNAL ;
    SHAPE ABUTMENT ;
    PORT
      LAYER M5 ;
      RECT 27.888 2250.024 27.912 2250.216 ;
    END
  END q[106]
  PIN q[107]
    DIRECTION OUTPUT ;
    USE SIGNAL ;
    SHAPE ABUTMENT ;
    PORT
      LAYER M5 ;
      RECT 28.080 2250.024 28.104 2250.216 ;
    END
  END q[107]
  PIN q[108]
    DIRECTION OUTPUT ;
    USE SIGNAL ;
    SHAPE ABUTMENT ;
    PORT
      LAYER M5 ;
      RECT 28.320 2250.024 28.344 2250.216 ;
    END
  END q[108]
  PIN q[109]
    DIRECTION OUTPUT ;
    USE SIGNAL ;
    SHAPE ABUTMENT ;
    PORT
      LAYER M5 ;
      RECT 28.512 2250.024 28.536 2250.216 ;
    END
  END q[109]
  PIN q[110]
    DIRECTION OUTPUT ;
    USE SIGNAL ;
    SHAPE ABUTMENT ;
    PORT
      LAYER M5 ;
      RECT 28.752 2250.024 28.776 2250.216 ;
    END
  END q[110]
  PIN q[111]
    DIRECTION OUTPUT ;
    USE SIGNAL ;
    SHAPE ABUTMENT ;
    PORT
      LAYER M5 ;
      RECT 28.992 2250.024 29.016 2250.216 ;
    END
  END q[111]
  PIN q[112]
    DIRECTION OUTPUT ;
    USE SIGNAL ;
    SHAPE ABUTMENT ;
    PORT
      LAYER M5 ;
      RECT 29.184 2250.024 29.208 2250.216 ;
    END
  END q[112]
  PIN q[113]
    DIRECTION OUTPUT ;
    USE SIGNAL ;
    SHAPE ABUTMENT ;
    PORT
      LAYER M5 ;
      RECT 29.424 2250.024 29.448 2250.216 ;
    END
  END q[113]
  PIN q[114]
    DIRECTION OUTPUT ;
    USE SIGNAL ;
    SHAPE ABUTMENT ;
    PORT
      LAYER M5 ;
      RECT 29.616 2250.024 29.640 2250.216 ;
    END
  END q[114]
  PIN q[115]
    DIRECTION OUTPUT ;
    USE SIGNAL ;
    SHAPE ABUTMENT ;
    PORT
      LAYER M5 ;
      RECT 29.856 2250.024 29.880 2250.216 ;
    END
  END q[115]
  PIN q[116]
    DIRECTION OUTPUT ;
    USE SIGNAL ;
    SHAPE ABUTMENT ;
    PORT
      LAYER M5 ;
      RECT 30.096 2250.024 30.120 2250.216 ;
    END
  END q[116]
  PIN q[117]
    DIRECTION OUTPUT ;
    USE SIGNAL ;
    SHAPE ABUTMENT ;
    PORT
      LAYER M5 ;
      RECT 30.288 2250.024 30.312 2250.216 ;
    END
  END q[117]
  PIN q[118]
    DIRECTION OUTPUT ;
    USE SIGNAL ;
    SHAPE ABUTMENT ;
    PORT
      LAYER M5 ;
      RECT 30.528 2250.024 30.552 2250.216 ;
    END
  END q[118]
  PIN q[119]
    DIRECTION OUTPUT ;
    USE SIGNAL ;
    SHAPE ABUTMENT ;
    PORT
      LAYER M5 ;
      RECT 30.720 2250.024 30.744 2250.216 ;
    END
  END q[119]
  PIN q[120]
    DIRECTION OUTPUT ;
    USE SIGNAL ;
    SHAPE ABUTMENT ;
    PORT
      LAYER M5 ;
      RECT 30.960 2250.024 30.984 2250.216 ;
    END
  END q[120]
  PIN q[121]
    DIRECTION OUTPUT ;
    USE SIGNAL ;
    SHAPE ABUTMENT ;
    PORT
      LAYER M5 ;
      RECT 31.200 2250.024 31.224 2250.216 ;
    END
  END q[121]
  PIN q[122]
    DIRECTION OUTPUT ;
    USE SIGNAL ;
    SHAPE ABUTMENT ;
    PORT
      LAYER M5 ;
      RECT 31.392 2250.024 31.416 2250.216 ;
    END
  END q[122]
  PIN q[123]
    DIRECTION OUTPUT ;
    USE SIGNAL ;
    SHAPE ABUTMENT ;
    PORT
      LAYER M5 ;
      RECT 31.632 2250.024 31.656 2250.216 ;
    END
  END q[123]
  PIN q[124]
    DIRECTION OUTPUT ;
    USE SIGNAL ;
    SHAPE ABUTMENT ;
    PORT
      LAYER M5 ;
      RECT 31.824 2250.024 31.848 2250.216 ;
    END
  END q[124]
  PIN q[125]
    DIRECTION OUTPUT ;
    USE SIGNAL ;
    SHAPE ABUTMENT ;
    PORT
      LAYER M5 ;
      RECT 32.064 2250.024 32.088 2250.216 ;
    END
  END q[125]
  PIN q[126]
    DIRECTION OUTPUT ;
    USE SIGNAL ;
    SHAPE ABUTMENT ;
    PORT
      LAYER M5 ;
      RECT 32.304 2250.024 32.328 2250.216 ;
    END
  END q[126]
  PIN q[127]
    DIRECTION OUTPUT ;
    USE SIGNAL ;
    SHAPE ABUTMENT ;
    PORT
      LAYER M5 ;
      RECT 32.496 2250.024 32.520 2250.216 ;
    END
  END q[127]
  PIN q[128]
    DIRECTION OUTPUT ;
    USE SIGNAL ;
    SHAPE ABUTMENT ;
    PORT
      LAYER M5 ;
      RECT 32.736 2250.024 32.760 2250.216 ;
    END
  END q[128]
  PIN q[129]
    DIRECTION OUTPUT ;
    USE SIGNAL ;
    SHAPE ABUTMENT ;
    PORT
      LAYER M5 ;
      RECT 32.928 2250.024 32.952 2250.216 ;
    END
  END q[129]
  PIN q[130]
    DIRECTION OUTPUT ;
    USE SIGNAL ;
    SHAPE ABUTMENT ;
    PORT
      LAYER M5 ;
      RECT 33.168 2250.024 33.192 2250.216 ;
    END
  END q[130]
  PIN q[131]
    DIRECTION OUTPUT ;
    USE SIGNAL ;
    SHAPE ABUTMENT ;
    PORT
      LAYER M5 ;
      RECT 33.408 2250.024 33.432 2250.216 ;
    END
  END q[131]
  PIN q[132]
    DIRECTION OUTPUT ;
    USE SIGNAL ;
    SHAPE ABUTMENT ;
    PORT
      LAYER M5 ;
      RECT 33.600 2250.024 33.624 2250.216 ;
    END
  END q[132]
  PIN q[133]
    DIRECTION OUTPUT ;
    USE SIGNAL ;
    SHAPE ABUTMENT ;
    PORT
      LAYER M5 ;
      RECT 33.840 2250.024 33.864 2250.216 ;
    END
  END q[133]
  PIN q[134]
    DIRECTION OUTPUT ;
    USE SIGNAL ;
    SHAPE ABUTMENT ;
    PORT
      LAYER M5 ;
      RECT 34.032 2250.024 34.056 2250.216 ;
    END
  END q[134]
  PIN q[135]
    DIRECTION OUTPUT ;
    USE SIGNAL ;
    SHAPE ABUTMENT ;
    PORT
      LAYER M5 ;
      RECT 34.272 2250.024 34.296 2250.216 ;
    END
  END q[135]
  PIN q[136]
    DIRECTION OUTPUT ;
    USE SIGNAL ;
    SHAPE ABUTMENT ;
    PORT
      LAYER M5 ;
      RECT 34.512 2250.024 34.536 2250.216 ;
    END
  END q[136]
  PIN q[137]
    DIRECTION OUTPUT ;
    USE SIGNAL ;
    SHAPE ABUTMENT ;
    PORT
      LAYER M5 ;
      RECT 34.704 2250.024 34.728 2250.216 ;
    END
  END q[137]
  PIN q[138]
    DIRECTION OUTPUT ;
    USE SIGNAL ;
    SHAPE ABUTMENT ;
    PORT
      LAYER M5 ;
      RECT 34.944 2250.024 34.968 2250.216 ;
    END
  END q[138]
  PIN q[139]
    DIRECTION OUTPUT ;
    USE SIGNAL ;
    SHAPE ABUTMENT ;
    PORT
      LAYER M5 ;
      RECT 35.136 2250.024 35.160 2250.216 ;
    END
  END q[139]
  PIN q[140]
    DIRECTION OUTPUT ;
    USE SIGNAL ;
    SHAPE ABUTMENT ;
    PORT
      LAYER M5 ;
      RECT 35.376 2250.024 35.400 2250.216 ;
    END
  END q[140]
  PIN q[141]
    DIRECTION OUTPUT ;
    USE SIGNAL ;
    SHAPE ABUTMENT ;
    PORT
      LAYER M5 ;
      RECT 35.568 2250.024 35.592 2250.216 ;
    END
  END q[141]
  PIN q[142]
    DIRECTION OUTPUT ;
    USE SIGNAL ;
    SHAPE ABUTMENT ;
    PORT
      LAYER M5 ;
      RECT 35.808 2250.024 35.832 2250.216 ;
    END
  END q[142]
  PIN q[143]
    DIRECTION OUTPUT ;
    USE SIGNAL ;
    SHAPE ABUTMENT ;
    PORT
      LAYER M5 ;
      RECT 36.048 2250.024 36.072 2250.216 ;
    END
  END q[143]
  PIN q[144]
    DIRECTION OUTPUT ;
    USE SIGNAL ;
    SHAPE ABUTMENT ;
    PORT
      LAYER M5 ;
      RECT 36.240 2250.024 36.264 2250.216 ;
    END
  END q[144]
  PIN q[145]
    DIRECTION OUTPUT ;
    USE SIGNAL ;
    SHAPE ABUTMENT ;
    PORT
      LAYER M5 ;
      RECT 36.480 2250.024 36.504 2250.216 ;
    END
  END q[145]
  PIN q[146]
    DIRECTION OUTPUT ;
    USE SIGNAL ;
    SHAPE ABUTMENT ;
    PORT
      LAYER M5 ;
      RECT 36.672 2250.024 36.696 2250.216 ;
    END
  END q[146]
  PIN q[147]
    DIRECTION OUTPUT ;
    USE SIGNAL ;
    SHAPE ABUTMENT ;
    PORT
      LAYER M5 ;
      RECT 36.912 2250.024 36.936 2250.216 ;
    END
  END q[147]
  PIN q[148]
    DIRECTION OUTPUT ;
    USE SIGNAL ;
    SHAPE ABUTMENT ;
    PORT
      LAYER M5 ;
      RECT 37.152 2250.024 37.176 2250.216 ;
    END
  END q[148]
  PIN q[149]
    DIRECTION OUTPUT ;
    USE SIGNAL ;
    SHAPE ABUTMENT ;
    PORT
      LAYER M5 ;
      RECT 37.344 2250.024 37.368 2250.216 ;
    END
  END q[149]
  PIN q[150]
    DIRECTION OUTPUT ;
    USE SIGNAL ;
    SHAPE ABUTMENT ;
    PORT
      LAYER M5 ;
      RECT 37.584 2250.024 37.608 2250.216 ;
    END
  END q[150]
  PIN q[151]
    DIRECTION OUTPUT ;
    USE SIGNAL ;
    SHAPE ABUTMENT ;
    PORT
      LAYER M5 ;
      RECT 37.776 2250.024 37.800 2250.216 ;
    END
  END q[151]
  PIN q[152]
    DIRECTION OUTPUT ;
    USE SIGNAL ;
    SHAPE ABUTMENT ;
    PORT
      LAYER M5 ;
      RECT 38.016 2250.024 38.040 2250.216 ;
    END
  END q[152]
  PIN q[153]
    DIRECTION OUTPUT ;
    USE SIGNAL ;
    SHAPE ABUTMENT ;
    PORT
      LAYER M5 ;
      RECT 38.256 2250.024 38.280 2250.216 ;
    END
  END q[153]
  PIN q[154]
    DIRECTION OUTPUT ;
    USE SIGNAL ;
    SHAPE ABUTMENT ;
    PORT
      LAYER M5 ;
      RECT 38.448 2250.024 38.472 2250.216 ;
    END
  END q[154]
  PIN q[155]
    DIRECTION OUTPUT ;
    USE SIGNAL ;
    SHAPE ABUTMENT ;
    PORT
      LAYER M5 ;
      RECT 38.688 2250.024 38.712 2250.216 ;
    END
  END q[155]
  PIN q[156]
    DIRECTION OUTPUT ;
    USE SIGNAL ;
    SHAPE ABUTMENT ;
    PORT
      LAYER M5 ;
      RECT 38.880 2250.024 38.904 2250.216 ;
    END
  END q[156]
  PIN q[157]
    DIRECTION OUTPUT ;
    USE SIGNAL ;
    SHAPE ABUTMENT ;
    PORT
      LAYER M5 ;
      RECT 39.120 2250.024 39.144 2250.216 ;
    END
  END q[157]
  PIN q[158]
    DIRECTION OUTPUT ;
    USE SIGNAL ;
    SHAPE ABUTMENT ;
    PORT
      LAYER M5 ;
      RECT 39.360 2250.024 39.384 2250.216 ;
    END
  END q[158]
  PIN q[159]
    DIRECTION OUTPUT ;
    USE SIGNAL ;
    SHAPE ABUTMENT ;
    PORT
      LAYER M5 ;
      RECT 39.552 2250.024 39.576 2250.216 ;
    END
  END q[159]
  PIN q[160]
    DIRECTION OUTPUT ;
    USE SIGNAL ;
    SHAPE ABUTMENT ;
    PORT
      LAYER M5 ;
      RECT 39.792 2250.024 39.816 2250.216 ;
    END
  END q[160]
  PIN q[161]
    DIRECTION OUTPUT ;
    USE SIGNAL ;
    SHAPE ABUTMENT ;
    PORT
      LAYER M5 ;
      RECT 39.984 2250.024 40.008 2250.216 ;
    END
  END q[161]
  PIN q[162]
    DIRECTION OUTPUT ;
    USE SIGNAL ;
    SHAPE ABUTMENT ;
    PORT
      LAYER M5 ;
      RECT 40.224 2250.024 40.248 2250.216 ;
    END
  END q[162]
  PIN q[163]
    DIRECTION OUTPUT ;
    USE SIGNAL ;
    SHAPE ABUTMENT ;
    PORT
      LAYER M5 ;
      RECT 40.464 2250.024 40.488 2250.216 ;
    END
  END q[163]
  PIN q[164]
    DIRECTION OUTPUT ;
    USE SIGNAL ;
    SHAPE ABUTMENT ;
    PORT
      LAYER M5 ;
      RECT 40.656 2250.024 40.680 2250.216 ;
    END
  END q[164]
  PIN q[165]
    DIRECTION OUTPUT ;
    USE SIGNAL ;
    SHAPE ABUTMENT ;
    PORT
      LAYER M5 ;
      RECT 40.896 2250.024 40.920 2250.216 ;
    END
  END q[165]
  PIN q[166]
    DIRECTION OUTPUT ;
    USE SIGNAL ;
    SHAPE ABUTMENT ;
    PORT
      LAYER M5 ;
      RECT 41.088 2250.024 41.112 2250.216 ;
    END
  END q[166]
  PIN q[167]
    DIRECTION OUTPUT ;
    USE SIGNAL ;
    SHAPE ABUTMENT ;
    PORT
      LAYER M5 ;
      RECT 41.328 2250.024 41.352 2250.216 ;
    END
  END q[167]
  PIN q[168]
    DIRECTION OUTPUT ;
    USE SIGNAL ;
    SHAPE ABUTMENT ;
    PORT
      LAYER M5 ;
      RECT 41.568 2250.024 41.592 2250.216 ;
    END
  END q[168]
  PIN q[169]
    DIRECTION OUTPUT ;
    USE SIGNAL ;
    SHAPE ABUTMENT ;
    PORT
      LAYER M5 ;
      RECT 41.760 2250.024 41.784 2250.216 ;
    END
  END q[169]
  PIN q[170]
    DIRECTION OUTPUT ;
    USE SIGNAL ;
    SHAPE ABUTMENT ;
    PORT
      LAYER M5 ;
      RECT 42.000 2250.024 42.024 2250.216 ;
    END
  END q[170]
  PIN q[171]
    DIRECTION OUTPUT ;
    USE SIGNAL ;
    SHAPE ABUTMENT ;
    PORT
      LAYER M5 ;
      RECT 42.192 2250.024 42.216 2250.216 ;
    END
  END q[171]
  PIN q[172]
    DIRECTION OUTPUT ;
    USE SIGNAL ;
    SHAPE ABUTMENT ;
    PORT
      LAYER M5 ;
      RECT 42.432 2250.024 42.456 2250.216 ;
    END
  END q[172]
  PIN q[173]
    DIRECTION OUTPUT ;
    USE SIGNAL ;
    SHAPE ABUTMENT ;
    PORT
      LAYER M5 ;
      RECT 42.672 2250.024 42.696 2250.216 ;
    END
  END q[173]
  PIN q[174]
    DIRECTION OUTPUT ;
    USE SIGNAL ;
    SHAPE ABUTMENT ;
    PORT
      LAYER M5 ;
      RECT 42.864 2250.024 42.888 2250.216 ;
    END
  END q[174]
  PIN q[175]
    DIRECTION OUTPUT ;
    USE SIGNAL ;
    SHAPE ABUTMENT ;
    PORT
      LAYER M5 ;
      RECT 43.104 2250.024 43.128 2250.216 ;
    END
  END q[175]
  PIN q[176]
    DIRECTION OUTPUT ;
    USE SIGNAL ;
    SHAPE ABUTMENT ;
    PORT
      LAYER M5 ;
      RECT 43.296 2250.024 43.320 2250.216 ;
    END
  END q[176]
  PIN q[177]
    DIRECTION OUTPUT ;
    USE SIGNAL ;
    SHAPE ABUTMENT ;
    PORT
      LAYER M5 ;
      RECT 43.536 2250.024 43.560 2250.216 ;
    END
  END q[177]
  PIN q[178]
    DIRECTION OUTPUT ;
    USE SIGNAL ;
    SHAPE ABUTMENT ;
    PORT
      LAYER M5 ;
      RECT 43.776 2250.024 43.800 2250.216 ;
    END
  END q[178]
  PIN q[179]
    DIRECTION OUTPUT ;
    USE SIGNAL ;
    SHAPE ABUTMENT ;
    PORT
      LAYER M5 ;
      RECT 43.968 2250.024 43.992 2250.216 ;
    END
  END q[179]
  PIN q[180]
    DIRECTION OUTPUT ;
    USE SIGNAL ;
    SHAPE ABUTMENT ;
    PORT
      LAYER M5 ;
      RECT 44.208 2250.024 44.232 2250.216 ;
    END
  END q[180]
  PIN q[181]
    DIRECTION OUTPUT ;
    USE SIGNAL ;
    SHAPE ABUTMENT ;
    PORT
      LAYER M5 ;
      RECT 44.400 2250.024 44.424 2250.216 ;
    END
  END q[181]
  PIN q[182]
    DIRECTION OUTPUT ;
    USE SIGNAL ;
    SHAPE ABUTMENT ;
    PORT
      LAYER M5 ;
      RECT 44.640 2250.024 44.664 2250.216 ;
    END
  END q[182]
  PIN q[183]
    DIRECTION OUTPUT ;
    USE SIGNAL ;
    SHAPE ABUTMENT ;
    PORT
      LAYER M5 ;
      RECT 44.832 2250.024 44.856 2250.216 ;
    END
  END q[183]
  PIN q[184]
    DIRECTION OUTPUT ;
    USE SIGNAL ;
    SHAPE ABUTMENT ;
    PORT
      LAYER M5 ;
      RECT 45.072 2250.024 45.096 2250.216 ;
    END
  END q[184]
  PIN q[185]
    DIRECTION OUTPUT ;
    USE SIGNAL ;
    SHAPE ABUTMENT ;
    PORT
      LAYER M5 ;
      RECT 45.312 2250.024 45.336 2250.216 ;
    END
  END q[185]
  PIN q[186]
    DIRECTION OUTPUT ;
    USE SIGNAL ;
    SHAPE ABUTMENT ;
    PORT
      LAYER M5 ;
      RECT 45.504 2250.024 45.528 2250.216 ;
    END
  END q[186]
  PIN q[187]
    DIRECTION OUTPUT ;
    USE SIGNAL ;
    SHAPE ABUTMENT ;
    PORT
      LAYER M5 ;
      RECT 45.744 2250.024 45.768 2250.216 ;
    END
  END q[187]
  PIN q[188]
    DIRECTION OUTPUT ;
    USE SIGNAL ;
    SHAPE ABUTMENT ;
    PORT
      LAYER M5 ;
      RECT 45.936 2250.024 45.960 2250.216 ;
    END
  END q[188]
  PIN q[189]
    DIRECTION OUTPUT ;
    USE SIGNAL ;
    SHAPE ABUTMENT ;
    PORT
      LAYER M5 ;
      RECT 46.176 2250.024 46.200 2250.216 ;
    END
  END q[189]
  PIN q[190]
    DIRECTION OUTPUT ;
    USE SIGNAL ;
    SHAPE ABUTMENT ;
    PORT
      LAYER M5 ;
      RECT 46.416 2250.024 46.440 2250.216 ;
    END
  END q[190]
  PIN q[191]
    DIRECTION OUTPUT ;
    USE SIGNAL ;
    SHAPE ABUTMENT ;
    PORT
      LAYER M5 ;
      RECT 46.608 2250.024 46.632 2250.216 ;
    END
  END q[191]
  PIN q[192]
    DIRECTION OUTPUT ;
    USE SIGNAL ;
    SHAPE ABUTMENT ;
    PORT
      LAYER M5 ;
      RECT 46.848 2250.024 46.872 2250.216 ;
    END
  END q[192]
  PIN q[193]
    DIRECTION OUTPUT ;
    USE SIGNAL ;
    SHAPE ABUTMENT ;
    PORT
      LAYER M5 ;
      RECT 47.040 2250.024 47.064 2250.216 ;
    END
  END q[193]
  PIN q[194]
    DIRECTION OUTPUT ;
    USE SIGNAL ;
    SHAPE ABUTMENT ;
    PORT
      LAYER M5 ;
      RECT 47.280 2250.024 47.304 2250.216 ;
    END
  END q[194]
  PIN q[195]
    DIRECTION OUTPUT ;
    USE SIGNAL ;
    SHAPE ABUTMENT ;
    PORT
      LAYER M5 ;
      RECT 47.520 2250.024 47.544 2250.216 ;
    END
  END q[195]
  PIN q[196]
    DIRECTION OUTPUT ;
    USE SIGNAL ;
    SHAPE ABUTMENT ;
    PORT
      LAYER M5 ;
      RECT 47.712 2250.024 47.736 2250.216 ;
    END
  END q[196]
  PIN q[197]
    DIRECTION OUTPUT ;
    USE SIGNAL ;
    SHAPE ABUTMENT ;
    PORT
      LAYER M5 ;
      RECT 47.952 2250.024 47.976 2250.216 ;
    END
  END q[197]
  PIN q[198]
    DIRECTION OUTPUT ;
    USE SIGNAL ;
    SHAPE ABUTMENT ;
    PORT
      LAYER M5 ;
      RECT 48.144 2250.024 48.168 2250.216 ;
    END
  END q[198]
  PIN q[199]
    DIRECTION OUTPUT ;
    USE SIGNAL ;
    SHAPE ABUTMENT ;
    PORT
      LAYER M5 ;
      RECT 48.384 2250.024 48.408 2250.216 ;
    END
  END q[199]
  PIN q[200]
    DIRECTION OUTPUT ;
    USE SIGNAL ;
    SHAPE ABUTMENT ;
    PORT
      LAYER M5 ;
      RECT 48.624 2250.024 48.648 2250.216 ;
    END
  END q[200]
  PIN q[201]
    DIRECTION OUTPUT ;
    USE SIGNAL ;
    SHAPE ABUTMENT ;
    PORT
      LAYER M5 ;
      RECT 48.816 2250.024 48.840 2250.216 ;
    END
  END q[201]
  PIN q[202]
    DIRECTION OUTPUT ;
    USE SIGNAL ;
    SHAPE ABUTMENT ;
    PORT
      LAYER M5 ;
      RECT 49.056 2250.024 49.080 2250.216 ;
    END
  END q[202]
  PIN q[203]
    DIRECTION OUTPUT ;
    USE SIGNAL ;
    SHAPE ABUTMENT ;
    PORT
      LAYER M5 ;
      RECT 49.248 2250.024 49.272 2250.216 ;
    END
  END q[203]
  PIN q[204]
    DIRECTION OUTPUT ;
    USE SIGNAL ;
    SHAPE ABUTMENT ;
    PORT
      LAYER M5 ;
      RECT 49.488 2250.024 49.512 2250.216 ;
    END
  END q[204]
  PIN q[205]
    DIRECTION OUTPUT ;
    USE SIGNAL ;
    SHAPE ABUTMENT ;
    PORT
      LAYER M5 ;
      RECT 49.728 2250.024 49.752 2250.216 ;
    END
  END q[205]
  PIN q[206]
    DIRECTION OUTPUT ;
    USE SIGNAL ;
    SHAPE ABUTMENT ;
    PORT
      LAYER M5 ;
      RECT 49.920 2250.024 49.944 2250.216 ;
    END
  END q[206]
  PIN q[207]
    DIRECTION OUTPUT ;
    USE SIGNAL ;
    SHAPE ABUTMENT ;
    PORT
      LAYER M5 ;
      RECT 50.160 2250.024 50.184 2250.216 ;
    END
  END q[207]
  PIN q[208]
    DIRECTION OUTPUT ;
    USE SIGNAL ;
    SHAPE ABUTMENT ;
    PORT
      LAYER M5 ;
      RECT 50.352 2250.024 50.376 2250.216 ;
    END
  END q[208]
  PIN q[209]
    DIRECTION OUTPUT ;
    USE SIGNAL ;
    SHAPE ABUTMENT ;
    PORT
      LAYER M5 ;
      RECT 50.592 2250.024 50.616 2250.216 ;
    END
  END q[209]
  PIN q[210]
    DIRECTION OUTPUT ;
    USE SIGNAL ;
    SHAPE ABUTMENT ;
    PORT
      LAYER M5 ;
      RECT 50.832 2250.024 50.856 2250.216 ;
    END
  END q[210]
  PIN q[211]
    DIRECTION OUTPUT ;
    USE SIGNAL ;
    SHAPE ABUTMENT ;
    PORT
      LAYER M5 ;
      RECT 51.024 2250.024 51.048 2250.216 ;
    END
  END q[211]
  PIN q[212]
    DIRECTION OUTPUT ;
    USE SIGNAL ;
    SHAPE ABUTMENT ;
    PORT
      LAYER M5 ;
      RECT 51.264 2250.024 51.288 2250.216 ;
    END
  END q[212]
  PIN q[213]
    DIRECTION OUTPUT ;
    USE SIGNAL ;
    SHAPE ABUTMENT ;
    PORT
      LAYER M5 ;
      RECT 51.456 2250.024 51.480 2250.216 ;
    END
  END q[213]
  PIN q[214]
    DIRECTION OUTPUT ;
    USE SIGNAL ;
    SHAPE ABUTMENT ;
    PORT
      LAYER M5 ;
      RECT 51.696 2250.024 51.720 2250.216 ;
    END
  END q[214]
  PIN q[215]
    DIRECTION OUTPUT ;
    USE SIGNAL ;
    SHAPE ABUTMENT ;
    PORT
      LAYER M5 ;
      RECT 51.936 2250.024 51.960 2250.216 ;
    END
  END q[215]
  PIN q[216]
    DIRECTION OUTPUT ;
    USE SIGNAL ;
    SHAPE ABUTMENT ;
    PORT
      LAYER M5 ;
      RECT 52.128 2250.024 52.152 2250.216 ;
    END
  END q[216]
  PIN q[217]
    DIRECTION OUTPUT ;
    USE SIGNAL ;
    SHAPE ABUTMENT ;
    PORT
      LAYER M5 ;
      RECT 52.368 2250.024 52.392 2250.216 ;
    END
  END q[217]
  PIN q[218]
    DIRECTION OUTPUT ;
    USE SIGNAL ;
    SHAPE ABUTMENT ;
    PORT
      LAYER M5 ;
      RECT 52.560 2250.024 52.584 2250.216 ;
    END
  END q[218]
  PIN q[219]
    DIRECTION OUTPUT ;
    USE SIGNAL ;
    SHAPE ABUTMENT ;
    PORT
      LAYER M5 ;
      RECT 52.800 2250.024 52.824 2250.216 ;
    END
  END q[219]
  PIN q[220]
    DIRECTION OUTPUT ;
    USE SIGNAL ;
    SHAPE ABUTMENT ;
    PORT
      LAYER M5 ;
      RECT 53.040 2250.024 53.064 2250.216 ;
    END
  END q[220]
  PIN q[221]
    DIRECTION OUTPUT ;
    USE SIGNAL ;
    SHAPE ABUTMENT ;
    PORT
      LAYER M5 ;
      RECT 53.232 2250.024 53.256 2250.216 ;
    END
  END q[221]
  PIN q[222]
    DIRECTION OUTPUT ;
    USE SIGNAL ;
    SHAPE ABUTMENT ;
    PORT
      LAYER M5 ;
      RECT 53.472 2250.024 53.496 2250.216 ;
    END
  END q[222]
  PIN q[223]
    DIRECTION OUTPUT ;
    USE SIGNAL ;
    SHAPE ABUTMENT ;
    PORT
      LAYER M5 ;
      RECT 53.664 2250.024 53.688 2250.216 ;
    END
  END q[223]
  PIN q[224]
    DIRECTION OUTPUT ;
    USE SIGNAL ;
    SHAPE ABUTMENT ;
    PORT
      LAYER M5 ;
      RECT 53.904 2250.024 53.928 2250.216 ;
    END
  END q[224]
  PIN q[225]
    DIRECTION OUTPUT ;
    USE SIGNAL ;
    SHAPE ABUTMENT ;
    PORT
      LAYER M5 ;
      RECT 54.144 2250.024 54.168 2250.216 ;
    END
  END q[225]
  PIN q[226]
    DIRECTION OUTPUT ;
    USE SIGNAL ;
    SHAPE ABUTMENT ;
    PORT
      LAYER M5 ;
      RECT 54.336 2250.024 54.360 2250.216 ;
    END
  END q[226]
  PIN q[227]
    DIRECTION OUTPUT ;
    USE SIGNAL ;
    SHAPE ABUTMENT ;
    PORT
      LAYER M5 ;
      RECT 54.576 2250.024 54.600 2250.216 ;
    END
  END q[227]
  PIN q[228]
    DIRECTION OUTPUT ;
    USE SIGNAL ;
    SHAPE ABUTMENT ;
    PORT
      LAYER M5 ;
      RECT 54.768 2250.024 54.792 2250.216 ;
    END
  END q[228]
  PIN q[229]
    DIRECTION OUTPUT ;
    USE SIGNAL ;
    SHAPE ABUTMENT ;
    PORT
      LAYER M5 ;
      RECT 55.008 2250.024 55.032 2250.216 ;
    END
  END q[229]
  PIN q[230]
    DIRECTION OUTPUT ;
    USE SIGNAL ;
    SHAPE ABUTMENT ;
    PORT
      LAYER M5 ;
      RECT 55.200 2250.024 55.224 2250.216 ;
    END
  END q[230]
  PIN q[231]
    DIRECTION OUTPUT ;
    USE SIGNAL ;
    SHAPE ABUTMENT ;
    PORT
      LAYER M5 ;
      RECT 55.440 2250.024 55.464 2250.216 ;
    END
  END q[231]
  PIN q[232]
    DIRECTION OUTPUT ;
    USE SIGNAL ;
    SHAPE ABUTMENT ;
    PORT
      LAYER M5 ;
      RECT 55.680 2250.024 55.704 2250.216 ;
    END
  END q[232]
  PIN q[233]
    DIRECTION OUTPUT ;
    USE SIGNAL ;
    SHAPE ABUTMENT ;
    PORT
      LAYER M5 ;
      RECT 55.872 2250.024 55.896 2250.216 ;
    END
  END q[233]
  PIN q[234]
    DIRECTION OUTPUT ;
    USE SIGNAL ;
    SHAPE ABUTMENT ;
    PORT
      LAYER M5 ;
      RECT 56.112 2250.024 56.136 2250.216 ;
    END
  END q[234]
  PIN q[235]
    DIRECTION OUTPUT ;
    USE SIGNAL ;
    SHAPE ABUTMENT ;
    PORT
      LAYER M5 ;
      RECT 56.304 2250.024 56.328 2250.216 ;
    END
  END q[235]
  PIN q[236]
    DIRECTION OUTPUT ;
    USE SIGNAL ;
    SHAPE ABUTMENT ;
    PORT
      LAYER M5 ;
      RECT 56.544 2250.024 56.568 2250.216 ;
    END
  END q[236]
  PIN q[237]
    DIRECTION OUTPUT ;
    USE SIGNAL ;
    SHAPE ABUTMENT ;
    PORT
      LAYER M5 ;
      RECT 56.784 2250.024 56.808 2250.216 ;
    END
  END q[237]
  PIN q[238]
    DIRECTION OUTPUT ;
    USE SIGNAL ;
    SHAPE ABUTMENT ;
    PORT
      LAYER M5 ;
      RECT 56.976 2250.024 57.000 2250.216 ;
    END
  END q[238]
  PIN q[239]
    DIRECTION OUTPUT ;
    USE SIGNAL ;
    SHAPE ABUTMENT ;
    PORT
      LAYER M5 ;
      RECT 57.216 2250.024 57.240 2250.216 ;
    END
  END q[239]
  PIN q[240]
    DIRECTION OUTPUT ;
    USE SIGNAL ;
    SHAPE ABUTMENT ;
    PORT
      LAYER M5 ;
      RECT 57.408 2250.024 57.432 2250.216 ;
    END
  END q[240]
  PIN q[241]
    DIRECTION OUTPUT ;
    USE SIGNAL ;
    SHAPE ABUTMENT ;
    PORT
      LAYER M5 ;
      RECT 57.648 2250.024 57.672 2250.216 ;
    END
  END q[241]
  PIN q[242]
    DIRECTION OUTPUT ;
    USE SIGNAL ;
    SHAPE ABUTMENT ;
    PORT
      LAYER M5 ;
      RECT 57.888 2250.024 57.912 2250.216 ;
    END
  END q[242]
  PIN q[243]
    DIRECTION OUTPUT ;
    USE SIGNAL ;
    SHAPE ABUTMENT ;
    PORT
      LAYER M5 ;
      RECT 58.080 2250.024 58.104 2250.216 ;
    END
  END q[243]
  PIN q[244]
    DIRECTION OUTPUT ;
    USE SIGNAL ;
    SHAPE ABUTMENT ;
    PORT
      LAYER M5 ;
      RECT 58.320 2250.024 58.344 2250.216 ;
    END
  END q[244]
  PIN q[245]
    DIRECTION OUTPUT ;
    USE SIGNAL ;
    SHAPE ABUTMENT ;
    PORT
      LAYER M5 ;
      RECT 58.512 2250.024 58.536 2250.216 ;
    END
  END q[245]
  PIN q[246]
    DIRECTION OUTPUT ;
    USE SIGNAL ;
    SHAPE ABUTMENT ;
    PORT
      LAYER M5 ;
      RECT 58.752 2250.024 58.776 2250.216 ;
    END
  END q[246]
  PIN q[247]
    DIRECTION OUTPUT ;
    USE SIGNAL ;
    SHAPE ABUTMENT ;
    PORT
      LAYER M5 ;
      RECT 58.992 2250.024 59.016 2250.216 ;
    END
  END q[247]
  PIN q[248]
    DIRECTION OUTPUT ;
    USE SIGNAL ;
    SHAPE ABUTMENT ;
    PORT
      LAYER M5 ;
      RECT 59.184 2250.024 59.208 2250.216 ;
    END
  END q[248]
  PIN q[249]
    DIRECTION OUTPUT ;
    USE SIGNAL ;
    SHAPE ABUTMENT ;
    PORT
      LAYER M5 ;
      RECT 59.424 2250.024 59.448 2250.216 ;
    END
  END q[249]
  PIN q[250]
    DIRECTION OUTPUT ;
    USE SIGNAL ;
    SHAPE ABUTMENT ;
    PORT
      LAYER M5 ;
      RECT 59.616 2250.024 59.640 2250.216 ;
    END
  END q[250]
  PIN q[251]
    DIRECTION OUTPUT ;
    USE SIGNAL ;
    SHAPE ABUTMENT ;
    PORT
      LAYER M5 ;
      RECT 59.856 2250.024 59.880 2250.216 ;
    END
  END q[251]
  PIN q[252]
    DIRECTION OUTPUT ;
    USE SIGNAL ;
    SHAPE ABUTMENT ;
    PORT
      LAYER M5 ;
      RECT 60.096 2250.024 60.120 2250.216 ;
    END
  END q[252]
  PIN q[253]
    DIRECTION OUTPUT ;
    USE SIGNAL ;
    SHAPE ABUTMENT ;
    PORT
      LAYER M5 ;
      RECT 60.288 2250.024 60.312 2250.216 ;
    END
  END q[253]
  PIN q[254]
    DIRECTION OUTPUT ;
    USE SIGNAL ;
    SHAPE ABUTMENT ;
    PORT
      LAYER M5 ;
      RECT 60.528 2250.024 60.552 2250.216 ;
    END
  END q[254]
  PIN q[255]
    DIRECTION OUTPUT ;
    USE SIGNAL ;
    SHAPE ABUTMENT ;
    PORT
      LAYER M5 ;
      RECT 60.720 2250.024 60.744 2250.216 ;
    END
  END q[255]
  PIN q[256]
    DIRECTION OUTPUT ;
    USE SIGNAL ;
    SHAPE ABUTMENT ;
    PORT
      LAYER M5 ;
      RECT 60.960 2250.024 60.984 2250.216 ;
    END
  END q[256]
  PIN q[257]
    DIRECTION OUTPUT ;
    USE SIGNAL ;
    SHAPE ABUTMENT ;
    PORT
      LAYER M5 ;
      RECT 61.200 2250.024 61.224 2250.216 ;
    END
  END q[257]
  PIN q[258]
    DIRECTION OUTPUT ;
    USE SIGNAL ;
    SHAPE ABUTMENT ;
    PORT
      LAYER M5 ;
      RECT 61.392 2250.024 61.416 2250.216 ;
    END
  END q[258]
  PIN q[259]
    DIRECTION OUTPUT ;
    USE SIGNAL ;
    SHAPE ABUTMENT ;
    PORT
      LAYER M5 ;
      RECT 61.632 2250.024 61.656 2250.216 ;
    END
  END q[259]
  PIN q[260]
    DIRECTION OUTPUT ;
    USE SIGNAL ;
    SHAPE ABUTMENT ;
    PORT
      LAYER M5 ;
      RECT 61.824 2250.024 61.848 2250.216 ;
    END
  END q[260]
  PIN q[261]
    DIRECTION OUTPUT ;
    USE SIGNAL ;
    SHAPE ABUTMENT ;
    PORT
      LAYER M5 ;
      RECT 62.064 2250.024 62.088 2250.216 ;
    END
  END q[261]
  PIN q[262]
    DIRECTION OUTPUT ;
    USE SIGNAL ;
    SHAPE ABUTMENT ;
    PORT
      LAYER M5 ;
      RECT 62.304 2250.024 62.328 2250.216 ;
    END
  END q[262]
  PIN q[263]
    DIRECTION OUTPUT ;
    USE SIGNAL ;
    SHAPE ABUTMENT ;
    PORT
      LAYER M5 ;
      RECT 62.496 2250.024 62.520 2250.216 ;
    END
  END q[263]
  PIN q[264]
    DIRECTION OUTPUT ;
    USE SIGNAL ;
    SHAPE ABUTMENT ;
    PORT
      LAYER M5 ;
      RECT 62.736 2250.024 62.760 2250.216 ;
    END
  END q[264]
  PIN q[265]
    DIRECTION OUTPUT ;
    USE SIGNAL ;
    SHAPE ABUTMENT ;
    PORT
      LAYER M5 ;
      RECT 62.928 2250.024 62.952 2250.216 ;
    END
  END q[265]
  PIN q[266]
    DIRECTION OUTPUT ;
    USE SIGNAL ;
    SHAPE ABUTMENT ;
    PORT
      LAYER M5 ;
      RECT 63.168 2250.024 63.192 2250.216 ;
    END
  END q[266]
  PIN q[267]
    DIRECTION OUTPUT ;
    USE SIGNAL ;
    SHAPE ABUTMENT ;
    PORT
      LAYER M5 ;
      RECT 63.408 2250.024 63.432 2250.216 ;
    END
  END q[267]
  PIN q[268]
    DIRECTION OUTPUT ;
    USE SIGNAL ;
    SHAPE ABUTMENT ;
    PORT
      LAYER M5 ;
      RECT 63.600 2250.024 63.624 2250.216 ;
    END
  END q[268]
  PIN q[269]
    DIRECTION OUTPUT ;
    USE SIGNAL ;
    SHAPE ABUTMENT ;
    PORT
      LAYER M5 ;
      RECT 63.840 2250.024 63.864 2250.216 ;
    END
  END q[269]
  PIN q[270]
    DIRECTION OUTPUT ;
    USE SIGNAL ;
    SHAPE ABUTMENT ;
    PORT
      LAYER M5 ;
      RECT 64.032 2250.024 64.056 2250.216 ;
    END
  END q[270]
  PIN q[271]
    DIRECTION OUTPUT ;
    USE SIGNAL ;
    SHAPE ABUTMENT ;
    PORT
      LAYER M5 ;
      RECT 64.272 2250.024 64.296 2250.216 ;
    END
  END q[271]
  PIN q[272]
    DIRECTION OUTPUT ;
    USE SIGNAL ;
    SHAPE ABUTMENT ;
    PORT
      LAYER M5 ;
      RECT 64.512 2250.024 64.536 2250.216 ;
    END
  END q[272]
  PIN q[273]
    DIRECTION OUTPUT ;
    USE SIGNAL ;
    SHAPE ABUTMENT ;
    PORT
      LAYER M5 ;
      RECT 64.704 2250.024 64.728 2250.216 ;
    END
  END q[273]
  PIN q[274]
    DIRECTION OUTPUT ;
    USE SIGNAL ;
    SHAPE ABUTMENT ;
    PORT
      LAYER M5 ;
      RECT 64.944 2250.024 64.968 2250.216 ;
    END
  END q[274]
  PIN q[275]
    DIRECTION OUTPUT ;
    USE SIGNAL ;
    SHAPE ABUTMENT ;
    PORT
      LAYER M5 ;
      RECT 65.136 2250.024 65.160 2250.216 ;
    END
  END q[275]
  PIN q[276]
    DIRECTION OUTPUT ;
    USE SIGNAL ;
    SHAPE ABUTMENT ;
    PORT
      LAYER M5 ;
      RECT 65.376 2250.024 65.400 2250.216 ;
    END
  END q[276]
  PIN q[277]
    DIRECTION OUTPUT ;
    USE SIGNAL ;
    SHAPE ABUTMENT ;
    PORT
      LAYER M5 ;
      RECT 65.568 2250.024 65.592 2250.216 ;
    END
  END q[277]
  PIN q[278]
    DIRECTION OUTPUT ;
    USE SIGNAL ;
    SHAPE ABUTMENT ;
    PORT
      LAYER M5 ;
      RECT 65.808 2250.024 65.832 2250.216 ;
    END
  END q[278]
  PIN q[279]
    DIRECTION OUTPUT ;
    USE SIGNAL ;
    SHAPE ABUTMENT ;
    PORT
      LAYER M5 ;
      RECT 66.048 2250.024 66.072 2250.216 ;
    END
  END q[279]
  PIN q[280]
    DIRECTION OUTPUT ;
    USE SIGNAL ;
    SHAPE ABUTMENT ;
    PORT
      LAYER M5 ;
      RECT 66.240 2250.024 66.264 2250.216 ;
    END
  END q[280]
  PIN q[281]
    DIRECTION OUTPUT ;
    USE SIGNAL ;
    SHAPE ABUTMENT ;
    PORT
      LAYER M5 ;
      RECT 66.480 2250.024 66.504 2250.216 ;
    END
  END q[281]
  PIN q[282]
    DIRECTION OUTPUT ;
    USE SIGNAL ;
    SHAPE ABUTMENT ;
    PORT
      LAYER M5 ;
      RECT 66.672 2250.024 66.696 2250.216 ;
    END
  END q[282]
  PIN q[283]
    DIRECTION OUTPUT ;
    USE SIGNAL ;
    SHAPE ABUTMENT ;
    PORT
      LAYER M5 ;
      RECT 66.912 2250.024 66.936 2250.216 ;
    END
  END q[283]
  PIN q[284]
    DIRECTION OUTPUT ;
    USE SIGNAL ;
    SHAPE ABUTMENT ;
    PORT
      LAYER M5 ;
      RECT 67.152 2250.024 67.176 2250.216 ;
    END
  END q[284]
  PIN q[285]
    DIRECTION OUTPUT ;
    USE SIGNAL ;
    SHAPE ABUTMENT ;
    PORT
      LAYER M5 ;
      RECT 67.344 2250.024 67.368 2250.216 ;
    END
  END q[285]
  PIN q[286]
    DIRECTION OUTPUT ;
    USE SIGNAL ;
    SHAPE ABUTMENT ;
    PORT
      LAYER M5 ;
      RECT 67.584 2250.024 67.608 2250.216 ;
    END
  END q[286]
  PIN q[287]
    DIRECTION OUTPUT ;
    USE SIGNAL ;
    SHAPE ABUTMENT ;
    PORT
      LAYER M5 ;
      RECT 67.776 2250.024 67.800 2250.216 ;
    END
  END q[287]
  PIN q[288]
    DIRECTION OUTPUT ;
    USE SIGNAL ;
    SHAPE ABUTMENT ;
    PORT
      LAYER M5 ;
      RECT 68.016 2250.024 68.040 2250.216 ;
    END
  END q[288]
  PIN q[289]
    DIRECTION OUTPUT ;
    USE SIGNAL ;
    SHAPE ABUTMENT ;
    PORT
      LAYER M5 ;
      RECT 68.256 2250.024 68.280 2250.216 ;
    END
  END q[289]
  PIN q[290]
    DIRECTION OUTPUT ;
    USE SIGNAL ;
    SHAPE ABUTMENT ;
    PORT
      LAYER M5 ;
      RECT 68.448 2250.024 68.472 2250.216 ;
    END
  END q[290]
  PIN q[291]
    DIRECTION OUTPUT ;
    USE SIGNAL ;
    SHAPE ABUTMENT ;
    PORT
      LAYER M5 ;
      RECT 68.688 2250.024 68.712 2250.216 ;
    END
  END q[291]
  PIN q[292]
    DIRECTION OUTPUT ;
    USE SIGNAL ;
    SHAPE ABUTMENT ;
    PORT
      LAYER M5 ;
      RECT 68.880 2250.024 68.904 2250.216 ;
    END
  END q[292]
  PIN q[293]
    DIRECTION OUTPUT ;
    USE SIGNAL ;
    SHAPE ABUTMENT ;
    PORT
      LAYER M5 ;
      RECT 69.120 2250.024 69.144 2250.216 ;
    END
  END q[293]
  PIN q[294]
    DIRECTION OUTPUT ;
    USE SIGNAL ;
    SHAPE ABUTMENT ;
    PORT
      LAYER M5 ;
      RECT 69.360 2250.024 69.384 2250.216 ;
    END
  END q[294]
  PIN q[295]
    DIRECTION OUTPUT ;
    USE SIGNAL ;
    SHAPE ABUTMENT ;
    PORT
      LAYER M5 ;
      RECT 69.552 2250.024 69.576 2250.216 ;
    END
  END q[295]
  PIN q[296]
    DIRECTION OUTPUT ;
    USE SIGNAL ;
    SHAPE ABUTMENT ;
    PORT
      LAYER M5 ;
      RECT 69.792 2250.024 69.816 2250.216 ;
    END
  END q[296]
  PIN q[297]
    DIRECTION OUTPUT ;
    USE SIGNAL ;
    SHAPE ABUTMENT ;
    PORT
      LAYER M5 ;
      RECT 69.984 2250.024 70.008 2250.216 ;
    END
  END q[297]
  PIN q[298]
    DIRECTION OUTPUT ;
    USE SIGNAL ;
    SHAPE ABUTMENT ;
    PORT
      LAYER M5 ;
      RECT 70.224 2250.024 70.248 2250.216 ;
    END
  END q[298]
  PIN q[299]
    DIRECTION OUTPUT ;
    USE SIGNAL ;
    SHAPE ABUTMENT ;
    PORT
      LAYER M5 ;
      RECT 70.464 2250.024 70.488 2250.216 ;
    END
  END q[299]
  PIN q[300]
    DIRECTION OUTPUT ;
    USE SIGNAL ;
    SHAPE ABUTMENT ;
    PORT
      LAYER M5 ;
      RECT 70.656 2250.024 70.680 2250.216 ;
    END
  END q[300]
  PIN q[301]
    DIRECTION OUTPUT ;
    USE SIGNAL ;
    SHAPE ABUTMENT ;
    PORT
      LAYER M5 ;
      RECT 70.896 2250.024 70.920 2250.216 ;
    END
  END q[301]
  PIN q[302]
    DIRECTION OUTPUT ;
    USE SIGNAL ;
    SHAPE ABUTMENT ;
    PORT
      LAYER M5 ;
      RECT 71.088 2250.024 71.112 2250.216 ;
    END
  END q[302]
  PIN q[303]
    DIRECTION OUTPUT ;
    USE SIGNAL ;
    SHAPE ABUTMENT ;
    PORT
      LAYER M5 ;
      RECT 71.328 2250.024 71.352 2250.216 ;
    END
  END q[303]
  PIN q[304]
    DIRECTION OUTPUT ;
    USE SIGNAL ;
    SHAPE ABUTMENT ;
    PORT
      LAYER M5 ;
      RECT 71.568 2250.024 71.592 2250.216 ;
    END
  END q[304]
  PIN q[305]
    DIRECTION OUTPUT ;
    USE SIGNAL ;
    SHAPE ABUTMENT ;
    PORT
      LAYER M5 ;
      RECT 71.760 2250.024 71.784 2250.216 ;
    END
  END q[305]
  PIN q[306]
    DIRECTION OUTPUT ;
    USE SIGNAL ;
    SHAPE ABUTMENT ;
    PORT
      LAYER M5 ;
      RECT 72.000 2250.024 72.024 2250.216 ;
    END
  END q[306]
  PIN q[307]
    DIRECTION OUTPUT ;
    USE SIGNAL ;
    SHAPE ABUTMENT ;
    PORT
      LAYER M5 ;
      RECT 72.192 2250.024 72.216 2250.216 ;
    END
  END q[307]
  PIN q[308]
    DIRECTION OUTPUT ;
    USE SIGNAL ;
    SHAPE ABUTMENT ;
    PORT
      LAYER M5 ;
      RECT 72.432 2250.024 72.456 2250.216 ;
    END
  END q[308]
  PIN q[309]
    DIRECTION OUTPUT ;
    USE SIGNAL ;
    SHAPE ABUTMENT ;
    PORT
      LAYER M5 ;
      RECT 72.672 2250.024 72.696 2250.216 ;
    END
  END q[309]
  PIN q[310]
    DIRECTION OUTPUT ;
    USE SIGNAL ;
    SHAPE ABUTMENT ;
    PORT
      LAYER M5 ;
      RECT 72.864 2250.024 72.888 2250.216 ;
    END
  END q[310]
  PIN q[311]
    DIRECTION OUTPUT ;
    USE SIGNAL ;
    SHAPE ABUTMENT ;
    PORT
      LAYER M5 ;
      RECT 73.104 2250.024 73.128 2250.216 ;
    END
  END q[311]
  PIN q[312]
    DIRECTION OUTPUT ;
    USE SIGNAL ;
    SHAPE ABUTMENT ;
    PORT
      LAYER M5 ;
      RECT 73.296 2250.024 73.320 2250.216 ;
    END
  END q[312]
  PIN q[313]
    DIRECTION OUTPUT ;
    USE SIGNAL ;
    SHAPE ABUTMENT ;
    PORT
      LAYER M5 ;
      RECT 73.536 2250.024 73.560 2250.216 ;
    END
  END q[313]
  PIN q[314]
    DIRECTION OUTPUT ;
    USE SIGNAL ;
    SHAPE ABUTMENT ;
    PORT
      LAYER M5 ;
      RECT 73.776 2250.024 73.800 2250.216 ;
    END
  END q[314]
  PIN q[315]
    DIRECTION OUTPUT ;
    USE SIGNAL ;
    SHAPE ABUTMENT ;
    PORT
      LAYER M5 ;
      RECT 73.968 2250.024 73.992 2250.216 ;
    END
  END q[315]
  PIN q[316]
    DIRECTION OUTPUT ;
    USE SIGNAL ;
    SHAPE ABUTMENT ;
    PORT
      LAYER M5 ;
      RECT 74.208 2250.024 74.232 2250.216 ;
    END
  END q[316]
  PIN q[317]
    DIRECTION OUTPUT ;
    USE SIGNAL ;
    SHAPE ABUTMENT ;
    PORT
      LAYER M5 ;
      RECT 74.400 2250.024 74.424 2250.216 ;
    END
  END q[317]
  PIN q[318]
    DIRECTION OUTPUT ;
    USE SIGNAL ;
    SHAPE ABUTMENT ;
    PORT
      LAYER M5 ;
      RECT 74.640 2250.024 74.664 2250.216 ;
    END
  END q[318]
  PIN q[319]
    DIRECTION OUTPUT ;
    USE SIGNAL ;
    SHAPE ABUTMENT ;
    PORT
      LAYER M5 ;
      RECT 74.832 2250.024 74.856 2250.216 ;
    END
  END q[319]
  PIN q[320]
    DIRECTION OUTPUT ;
    USE SIGNAL ;
    SHAPE ABUTMENT ;
    PORT
      LAYER M5 ;
      RECT 75.072 2250.024 75.096 2250.216 ;
    END
  END q[320]
  PIN q[321]
    DIRECTION OUTPUT ;
    USE SIGNAL ;
    SHAPE ABUTMENT ;
    PORT
      LAYER M5 ;
      RECT 75.312 2250.024 75.336 2250.216 ;
    END
  END q[321]
  PIN q[322]
    DIRECTION OUTPUT ;
    USE SIGNAL ;
    SHAPE ABUTMENT ;
    PORT
      LAYER M5 ;
      RECT 75.504 2250.024 75.528 2250.216 ;
    END
  END q[322]
  PIN q[323]
    DIRECTION OUTPUT ;
    USE SIGNAL ;
    SHAPE ABUTMENT ;
    PORT
      LAYER M5 ;
      RECT 75.744 2250.024 75.768 2250.216 ;
    END
  END q[323]
  PIN q[324]
    DIRECTION OUTPUT ;
    USE SIGNAL ;
    SHAPE ABUTMENT ;
    PORT
      LAYER M5 ;
      RECT 75.936 2250.024 75.960 2250.216 ;
    END
  END q[324]
  PIN q[325]
    DIRECTION OUTPUT ;
    USE SIGNAL ;
    SHAPE ABUTMENT ;
    PORT
      LAYER M5 ;
      RECT 76.176 2250.024 76.200 2250.216 ;
    END
  END q[325]
  PIN q[326]
    DIRECTION OUTPUT ;
    USE SIGNAL ;
    SHAPE ABUTMENT ;
    PORT
      LAYER M5 ;
      RECT 76.416 2250.024 76.440 2250.216 ;
    END
  END q[326]
  PIN q[327]
    DIRECTION OUTPUT ;
    USE SIGNAL ;
    SHAPE ABUTMENT ;
    PORT
      LAYER M5 ;
      RECT 76.608 2250.024 76.632 2250.216 ;
    END
  END q[327]
  PIN q[328]
    DIRECTION OUTPUT ;
    USE SIGNAL ;
    SHAPE ABUTMENT ;
    PORT
      LAYER M5 ;
      RECT 76.848 2250.024 76.872 2250.216 ;
    END
  END q[328]
  PIN q[329]
    DIRECTION OUTPUT ;
    USE SIGNAL ;
    SHAPE ABUTMENT ;
    PORT
      LAYER M5 ;
      RECT 77.040 2250.024 77.064 2250.216 ;
    END
  END q[329]
  PIN q[330]
    DIRECTION OUTPUT ;
    USE SIGNAL ;
    SHAPE ABUTMENT ;
    PORT
      LAYER M5 ;
      RECT 77.280 2250.024 77.304 2250.216 ;
    END
  END q[330]
  PIN q[331]
    DIRECTION OUTPUT ;
    USE SIGNAL ;
    SHAPE ABUTMENT ;
    PORT
      LAYER M5 ;
      RECT 77.520 2250.024 77.544 2250.216 ;
    END
  END q[331]
  PIN q[332]
    DIRECTION OUTPUT ;
    USE SIGNAL ;
    SHAPE ABUTMENT ;
    PORT
      LAYER M5 ;
      RECT 77.712 2250.024 77.736 2250.216 ;
    END
  END q[332]
  PIN q[333]
    DIRECTION OUTPUT ;
    USE SIGNAL ;
    SHAPE ABUTMENT ;
    PORT
      LAYER M5 ;
      RECT 77.952 2250.024 77.976 2250.216 ;
    END
  END q[333]
  PIN q[334]
    DIRECTION OUTPUT ;
    USE SIGNAL ;
    SHAPE ABUTMENT ;
    PORT
      LAYER M5 ;
      RECT 78.144 2250.024 78.168 2250.216 ;
    END
  END q[334]
  PIN q[335]
    DIRECTION OUTPUT ;
    USE SIGNAL ;
    SHAPE ABUTMENT ;
    PORT
      LAYER M5 ;
      RECT 78.384 2250.024 78.408 2250.216 ;
    END
  END q[335]
  PIN q[336]
    DIRECTION OUTPUT ;
    USE SIGNAL ;
    SHAPE ABUTMENT ;
    PORT
      LAYER M5 ;
      RECT 78.624 2250.024 78.648 2250.216 ;
    END
  END q[336]
  PIN q[337]
    DIRECTION OUTPUT ;
    USE SIGNAL ;
    SHAPE ABUTMENT ;
    PORT
      LAYER M5 ;
      RECT 78.816 2250.024 78.840 2250.216 ;
    END
  END q[337]
  PIN q[338]
    DIRECTION OUTPUT ;
    USE SIGNAL ;
    SHAPE ABUTMENT ;
    PORT
      LAYER M5 ;
      RECT 79.056 2250.024 79.080 2250.216 ;
    END
  END q[338]
  PIN q[339]
    DIRECTION OUTPUT ;
    USE SIGNAL ;
    SHAPE ABUTMENT ;
    PORT
      LAYER M5 ;
      RECT 79.248 2250.024 79.272 2250.216 ;
    END
  END q[339]
  PIN q[340]
    DIRECTION OUTPUT ;
    USE SIGNAL ;
    SHAPE ABUTMENT ;
    PORT
      LAYER M5 ;
      RECT 79.488 2250.024 79.512 2250.216 ;
    END
  END q[340]
  PIN q[341]
    DIRECTION OUTPUT ;
    USE SIGNAL ;
    SHAPE ABUTMENT ;
    PORT
      LAYER M5 ;
      RECT 79.728 2250.024 79.752 2250.216 ;
    END
  END q[341]
  PIN q[342]
    DIRECTION OUTPUT ;
    USE SIGNAL ;
    SHAPE ABUTMENT ;
    PORT
      LAYER M5 ;
      RECT 79.920 2250.024 79.944 2250.216 ;
    END
  END q[342]
  PIN q[343]
    DIRECTION OUTPUT ;
    USE SIGNAL ;
    SHAPE ABUTMENT ;
    PORT
      LAYER M5 ;
      RECT 80.160 2250.024 80.184 2250.216 ;
    END
  END q[343]
  PIN q[344]
    DIRECTION OUTPUT ;
    USE SIGNAL ;
    SHAPE ABUTMENT ;
    PORT
      LAYER M5 ;
      RECT 80.352 2250.024 80.376 2250.216 ;
    END
  END q[344]
  PIN q[345]
    DIRECTION OUTPUT ;
    USE SIGNAL ;
    SHAPE ABUTMENT ;
    PORT
      LAYER M5 ;
      RECT 80.592 2250.024 80.616 2250.216 ;
    END
  END q[345]
  PIN q[346]
    DIRECTION OUTPUT ;
    USE SIGNAL ;
    SHAPE ABUTMENT ;
    PORT
      LAYER M5 ;
      RECT 80.832 2250.024 80.856 2250.216 ;
    END
  END q[346]
  PIN q[347]
    DIRECTION OUTPUT ;
    USE SIGNAL ;
    SHAPE ABUTMENT ;
    PORT
      LAYER M5 ;
      RECT 81.024 2250.024 81.048 2250.216 ;
    END
  END q[347]
  PIN q[348]
    DIRECTION OUTPUT ;
    USE SIGNAL ;
    SHAPE ABUTMENT ;
    PORT
      LAYER M5 ;
      RECT 81.264 2250.024 81.288 2250.216 ;
    END
  END q[348]
  PIN q[349]
    DIRECTION OUTPUT ;
    USE SIGNAL ;
    SHAPE ABUTMENT ;
    PORT
      LAYER M5 ;
      RECT 81.456 2250.024 81.480 2250.216 ;
    END
  END q[349]
  PIN q[350]
    DIRECTION OUTPUT ;
    USE SIGNAL ;
    SHAPE ABUTMENT ;
    PORT
      LAYER M5 ;
      RECT 81.696 2250.024 81.720 2250.216 ;
    END
  END q[350]
  PIN q[351]
    DIRECTION OUTPUT ;
    USE SIGNAL ;
    SHAPE ABUTMENT ;
    PORT
      LAYER M5 ;
      RECT 81.936 2250.024 81.960 2250.216 ;
    END
  END q[351]
  PIN q[352]
    DIRECTION OUTPUT ;
    USE SIGNAL ;
    SHAPE ABUTMENT ;
    PORT
      LAYER M5 ;
      RECT 82.128 2250.024 82.152 2250.216 ;
    END
  END q[352]
  PIN q[353]
    DIRECTION OUTPUT ;
    USE SIGNAL ;
    SHAPE ABUTMENT ;
    PORT
      LAYER M5 ;
      RECT 82.368 2250.024 82.392 2250.216 ;
    END
  END q[353]
  PIN q[354]
    DIRECTION OUTPUT ;
    USE SIGNAL ;
    SHAPE ABUTMENT ;
    PORT
      LAYER M5 ;
      RECT 82.560 2250.024 82.584 2250.216 ;
    END
  END q[354]
  PIN q[355]
    DIRECTION OUTPUT ;
    USE SIGNAL ;
    SHAPE ABUTMENT ;
    PORT
      LAYER M5 ;
      RECT 82.800 2250.024 82.824 2250.216 ;
    END
  END q[355]
  PIN q[356]
    DIRECTION OUTPUT ;
    USE SIGNAL ;
    SHAPE ABUTMENT ;
    PORT
      LAYER M5 ;
      RECT 83.040 2250.024 83.064 2250.216 ;
    END
  END q[356]
  PIN q[357]
    DIRECTION OUTPUT ;
    USE SIGNAL ;
    SHAPE ABUTMENT ;
    PORT
      LAYER M5 ;
      RECT 83.232 2250.024 83.256 2250.216 ;
    END
  END q[357]
  PIN q[358]
    DIRECTION OUTPUT ;
    USE SIGNAL ;
    SHAPE ABUTMENT ;
    PORT
      LAYER M5 ;
      RECT 83.472 2250.024 83.496 2250.216 ;
    END
  END q[358]
  PIN q[359]
    DIRECTION OUTPUT ;
    USE SIGNAL ;
    SHAPE ABUTMENT ;
    PORT
      LAYER M5 ;
      RECT 83.664 2250.024 83.688 2250.216 ;
    END
  END q[359]
  PIN q[360]
    DIRECTION OUTPUT ;
    USE SIGNAL ;
    SHAPE ABUTMENT ;
    PORT
      LAYER M5 ;
      RECT 83.904 2250.024 83.928 2250.216 ;
    END
  END q[360]
  PIN q[361]
    DIRECTION OUTPUT ;
    USE SIGNAL ;
    SHAPE ABUTMENT ;
    PORT
      LAYER M5 ;
      RECT 84.144 2250.024 84.168 2250.216 ;
    END
  END q[361]
  PIN q[362]
    DIRECTION OUTPUT ;
    USE SIGNAL ;
    SHAPE ABUTMENT ;
    PORT
      LAYER M5 ;
      RECT 84.336 2250.024 84.360 2250.216 ;
    END
  END q[362]
  PIN q[363]
    DIRECTION OUTPUT ;
    USE SIGNAL ;
    SHAPE ABUTMENT ;
    PORT
      LAYER M5 ;
      RECT 84.576 2250.024 84.600 2250.216 ;
    END
  END q[363]
  PIN q[364]
    DIRECTION OUTPUT ;
    USE SIGNAL ;
    SHAPE ABUTMENT ;
    PORT
      LAYER M5 ;
      RECT 84.768 2250.024 84.792 2250.216 ;
    END
  END q[364]
  PIN q[365]
    DIRECTION OUTPUT ;
    USE SIGNAL ;
    SHAPE ABUTMENT ;
    PORT
      LAYER M5 ;
      RECT 85.008 2250.024 85.032 2250.216 ;
    END
  END q[365]
  PIN q[366]
    DIRECTION OUTPUT ;
    USE SIGNAL ;
    SHAPE ABUTMENT ;
    PORT
      LAYER M5 ;
      RECT 85.200 2250.024 85.224 2250.216 ;
    END
  END q[366]
  PIN q[367]
    DIRECTION OUTPUT ;
    USE SIGNAL ;
    SHAPE ABUTMENT ;
    PORT
      LAYER M5 ;
      RECT 85.440 2250.024 85.464 2250.216 ;
    END
  END q[367]
  PIN q[368]
    DIRECTION OUTPUT ;
    USE SIGNAL ;
    SHAPE ABUTMENT ;
    PORT
      LAYER M5 ;
      RECT 85.680 2250.024 85.704 2250.216 ;
    END
  END q[368]
  PIN q[369]
    DIRECTION OUTPUT ;
    USE SIGNAL ;
    SHAPE ABUTMENT ;
    PORT
      LAYER M5 ;
      RECT 85.872 2250.024 85.896 2250.216 ;
    END
  END q[369]
  PIN q[370]
    DIRECTION OUTPUT ;
    USE SIGNAL ;
    SHAPE ABUTMENT ;
    PORT
      LAYER M5 ;
      RECT 86.112 2250.024 86.136 2250.216 ;
    END
  END q[370]
  PIN q[371]
    DIRECTION OUTPUT ;
    USE SIGNAL ;
    SHAPE ABUTMENT ;
    PORT
      LAYER M5 ;
      RECT 86.304 2250.024 86.328 2250.216 ;
    END
  END q[371]
  PIN q[372]
    DIRECTION OUTPUT ;
    USE SIGNAL ;
    SHAPE ABUTMENT ;
    PORT
      LAYER M5 ;
      RECT 86.544 2250.024 86.568 2250.216 ;
    END
  END q[372]
  PIN q[373]
    DIRECTION OUTPUT ;
    USE SIGNAL ;
    SHAPE ABUTMENT ;
    PORT
      LAYER M5 ;
      RECT 86.784 2250.024 86.808 2250.216 ;
    END
  END q[373]
  PIN q[374]
    DIRECTION OUTPUT ;
    USE SIGNAL ;
    SHAPE ABUTMENT ;
    PORT
      LAYER M5 ;
      RECT 86.976 2250.024 87.000 2250.216 ;
    END
  END q[374]
  PIN q[375]
    DIRECTION OUTPUT ;
    USE SIGNAL ;
    SHAPE ABUTMENT ;
    PORT
      LAYER M5 ;
      RECT 87.216 2250.024 87.240 2250.216 ;
    END
  END q[375]
  PIN q[376]
    DIRECTION OUTPUT ;
    USE SIGNAL ;
    SHAPE ABUTMENT ;
    PORT
      LAYER M5 ;
      RECT 87.408 2250.024 87.432 2250.216 ;
    END
  END q[376]
  PIN q[377]
    DIRECTION OUTPUT ;
    USE SIGNAL ;
    SHAPE ABUTMENT ;
    PORT
      LAYER M5 ;
      RECT 87.648 2250.024 87.672 2250.216 ;
    END
  END q[377]
  PIN q[378]
    DIRECTION OUTPUT ;
    USE SIGNAL ;
    SHAPE ABUTMENT ;
    PORT
      LAYER M5 ;
      RECT 87.888 2250.024 87.912 2250.216 ;
    END
  END q[378]
  PIN q[379]
    DIRECTION OUTPUT ;
    USE SIGNAL ;
    SHAPE ABUTMENT ;
    PORT
      LAYER M5 ;
      RECT 88.080 2250.024 88.104 2250.216 ;
    END
  END q[379]
  PIN q[380]
    DIRECTION OUTPUT ;
    USE SIGNAL ;
    SHAPE ABUTMENT ;
    PORT
      LAYER M5 ;
      RECT 88.320 2250.024 88.344 2250.216 ;
    END
  END q[380]
  PIN q[381]
    DIRECTION OUTPUT ;
    USE SIGNAL ;
    SHAPE ABUTMENT ;
    PORT
      LAYER M5 ;
      RECT 88.512 2250.024 88.536 2250.216 ;
    END
  END q[381]
  PIN q[382]
    DIRECTION OUTPUT ;
    USE SIGNAL ;
    SHAPE ABUTMENT ;
    PORT
      LAYER M5 ;
      RECT 88.752 2250.024 88.776 2250.216 ;
    END
  END q[382]
  PIN q[383]
    DIRECTION OUTPUT ;
    USE SIGNAL ;
    SHAPE ABUTMENT ;
    PORT
      LAYER M5 ;
      RECT 88.992 2250.024 89.016 2250.216 ;
    END
  END q[383]
  PIN q[384]
    DIRECTION OUTPUT ;
    USE SIGNAL ;
    SHAPE ABUTMENT ;
    PORT
      LAYER M5 ;
      RECT 89.184 2250.024 89.208 2250.216 ;
    END
  END q[384]
  PIN q[385]
    DIRECTION OUTPUT ;
    USE SIGNAL ;
    SHAPE ABUTMENT ;
    PORT
      LAYER M5 ;
      RECT 89.424 2250.024 89.448 2250.216 ;
    END
  END q[385]
  PIN q[386]
    DIRECTION OUTPUT ;
    USE SIGNAL ;
    SHAPE ABUTMENT ;
    PORT
      LAYER M5 ;
      RECT 89.616 2250.024 89.640 2250.216 ;
    END
  END q[386]
  PIN q[387]
    DIRECTION OUTPUT ;
    USE SIGNAL ;
    SHAPE ABUTMENT ;
    PORT
      LAYER M5 ;
      RECT 89.856 2250.024 89.880 2250.216 ;
    END
  END q[387]
  PIN q[388]
    DIRECTION OUTPUT ;
    USE SIGNAL ;
    SHAPE ABUTMENT ;
    PORT
      LAYER M5 ;
      RECT 90.096 2250.024 90.120 2250.216 ;
    END
  END q[388]
  PIN q[389]
    DIRECTION OUTPUT ;
    USE SIGNAL ;
    SHAPE ABUTMENT ;
    PORT
      LAYER M5 ;
      RECT 90.288 2250.024 90.312 2250.216 ;
    END
  END q[389]
  PIN q[390]
    DIRECTION OUTPUT ;
    USE SIGNAL ;
    SHAPE ABUTMENT ;
    PORT
      LAYER M5 ;
      RECT 90.528 2250.024 90.552 2250.216 ;
    END
  END q[390]
  PIN q[391]
    DIRECTION OUTPUT ;
    USE SIGNAL ;
    SHAPE ABUTMENT ;
    PORT
      LAYER M5 ;
      RECT 90.720 2250.024 90.744 2250.216 ;
    END
  END q[391]
  PIN q[392]
    DIRECTION OUTPUT ;
    USE SIGNAL ;
    SHAPE ABUTMENT ;
    PORT
      LAYER M5 ;
      RECT 90.960 2250.024 90.984 2250.216 ;
    END
  END q[392]
  PIN q[393]
    DIRECTION OUTPUT ;
    USE SIGNAL ;
    SHAPE ABUTMENT ;
    PORT
      LAYER M5 ;
      RECT 91.200 2250.024 91.224 2250.216 ;
    END
  END q[393]
  PIN q[394]
    DIRECTION OUTPUT ;
    USE SIGNAL ;
    SHAPE ABUTMENT ;
    PORT
      LAYER M5 ;
      RECT 91.392 2250.024 91.416 2250.216 ;
    END
  END q[394]
  PIN q[395]
    DIRECTION OUTPUT ;
    USE SIGNAL ;
    SHAPE ABUTMENT ;
    PORT
      LAYER M5 ;
      RECT 91.632 2250.024 91.656 2250.216 ;
    END
  END q[395]
  PIN q[396]
    DIRECTION OUTPUT ;
    USE SIGNAL ;
    SHAPE ABUTMENT ;
    PORT
      LAYER M5 ;
      RECT 91.824 2250.024 91.848 2250.216 ;
    END
  END q[396]
  PIN q[397]
    DIRECTION OUTPUT ;
    USE SIGNAL ;
    SHAPE ABUTMENT ;
    PORT
      LAYER M5 ;
      RECT 92.064 2250.024 92.088 2250.216 ;
    END
  END q[397]
  PIN q[398]
    DIRECTION OUTPUT ;
    USE SIGNAL ;
    SHAPE ABUTMENT ;
    PORT
      LAYER M5 ;
      RECT 92.304 2250.024 92.328 2250.216 ;
    END
  END q[398]
  PIN q[399]
    DIRECTION OUTPUT ;
    USE SIGNAL ;
    SHAPE ABUTMENT ;
    PORT
      LAYER M5 ;
      RECT 92.496 2250.024 92.520 2250.216 ;
    END
  END q[399]
  PIN q[400]
    DIRECTION OUTPUT ;
    USE SIGNAL ;
    SHAPE ABUTMENT ;
    PORT
      LAYER M5 ;
      RECT 92.736 2250.024 92.760 2250.216 ;
    END
  END q[400]
  PIN q[401]
    DIRECTION OUTPUT ;
    USE SIGNAL ;
    SHAPE ABUTMENT ;
    PORT
      LAYER M5 ;
      RECT 92.928 2250.024 92.952 2250.216 ;
    END
  END q[401]
  PIN q[402]
    DIRECTION OUTPUT ;
    USE SIGNAL ;
    SHAPE ABUTMENT ;
    PORT
      LAYER M5 ;
      RECT 93.168 2250.024 93.192 2250.216 ;
    END
  END q[402]
  PIN q[403]
    DIRECTION OUTPUT ;
    USE SIGNAL ;
    SHAPE ABUTMENT ;
    PORT
      LAYER M5 ;
      RECT 93.408 2250.024 93.432 2250.216 ;
    END
  END q[403]
  PIN q[404]
    DIRECTION OUTPUT ;
    USE SIGNAL ;
    SHAPE ABUTMENT ;
    PORT
      LAYER M5 ;
      RECT 93.600 2250.024 93.624 2250.216 ;
    END
  END q[404]
  PIN q[405]
    DIRECTION OUTPUT ;
    USE SIGNAL ;
    SHAPE ABUTMENT ;
    PORT
      LAYER M5 ;
      RECT 93.840 2250.024 93.864 2250.216 ;
    END
  END q[405]
  PIN q[406]
    DIRECTION OUTPUT ;
    USE SIGNAL ;
    SHAPE ABUTMENT ;
    PORT
      LAYER M5 ;
      RECT 94.032 2250.024 94.056 2250.216 ;
    END
  END q[406]
  PIN q[407]
    DIRECTION OUTPUT ;
    USE SIGNAL ;
    SHAPE ABUTMENT ;
    PORT
      LAYER M5 ;
      RECT 94.272 2250.024 94.296 2250.216 ;
    END
  END q[407]
  PIN q[408]
    DIRECTION OUTPUT ;
    USE SIGNAL ;
    SHAPE ABUTMENT ;
    PORT
      LAYER M5 ;
      RECT 94.512 2250.024 94.536 2250.216 ;
    END
  END q[408]
  PIN q[409]
    DIRECTION OUTPUT ;
    USE SIGNAL ;
    SHAPE ABUTMENT ;
    PORT
      LAYER M5 ;
      RECT 94.704 2250.024 94.728 2250.216 ;
    END
  END q[409]
  PIN q[410]
    DIRECTION OUTPUT ;
    USE SIGNAL ;
    SHAPE ABUTMENT ;
    PORT
      LAYER M5 ;
      RECT 94.944 2250.024 94.968 2250.216 ;
    END
  END q[410]
  PIN q[411]
    DIRECTION OUTPUT ;
    USE SIGNAL ;
    SHAPE ABUTMENT ;
    PORT
      LAYER M5 ;
      RECT 95.136 2250.024 95.160 2250.216 ;
    END
  END q[411]
  PIN q[412]
    DIRECTION OUTPUT ;
    USE SIGNAL ;
    SHAPE ABUTMENT ;
    PORT
      LAYER M5 ;
      RECT 95.376 2250.024 95.400 2250.216 ;
    END
  END q[412]
  PIN q[413]
    DIRECTION OUTPUT ;
    USE SIGNAL ;
    SHAPE ABUTMENT ;
    PORT
      LAYER M5 ;
      RECT 95.568 2250.024 95.592 2250.216 ;
    END
  END q[413]
  PIN q[414]
    DIRECTION OUTPUT ;
    USE SIGNAL ;
    SHAPE ABUTMENT ;
    PORT
      LAYER M5 ;
      RECT 95.808 2250.024 95.832 2250.216 ;
    END
  END q[414]
  PIN q[415]
    DIRECTION OUTPUT ;
    USE SIGNAL ;
    SHAPE ABUTMENT ;
    PORT
      LAYER M5 ;
      RECT 96.048 2250.024 96.072 2250.216 ;
    END
  END q[415]
  PIN q[416]
    DIRECTION OUTPUT ;
    USE SIGNAL ;
    SHAPE ABUTMENT ;
    PORT
      LAYER M5 ;
      RECT 96.240 2250.024 96.264 2250.216 ;
    END
  END q[416]
  PIN q[417]
    DIRECTION OUTPUT ;
    USE SIGNAL ;
    SHAPE ABUTMENT ;
    PORT
      LAYER M5 ;
      RECT 96.480 2250.024 96.504 2250.216 ;
    END
  END q[417]
  PIN q[418]
    DIRECTION OUTPUT ;
    USE SIGNAL ;
    SHAPE ABUTMENT ;
    PORT
      LAYER M5 ;
      RECT 96.672 2250.024 96.696 2250.216 ;
    END
  END q[418]
  PIN q[419]
    DIRECTION OUTPUT ;
    USE SIGNAL ;
    SHAPE ABUTMENT ;
    PORT
      LAYER M5 ;
      RECT 96.912 2250.024 96.936 2250.216 ;
    END
  END q[419]
  PIN q[420]
    DIRECTION OUTPUT ;
    USE SIGNAL ;
    SHAPE ABUTMENT ;
    PORT
      LAYER M5 ;
      RECT 97.152 2250.024 97.176 2250.216 ;
    END
  END q[420]
  PIN q[421]
    DIRECTION OUTPUT ;
    USE SIGNAL ;
    SHAPE ABUTMENT ;
    PORT
      LAYER M5 ;
      RECT 97.344 2250.024 97.368 2250.216 ;
    END
  END q[421]
  PIN q[422]
    DIRECTION OUTPUT ;
    USE SIGNAL ;
    SHAPE ABUTMENT ;
    PORT
      LAYER M5 ;
      RECT 97.584 2250.024 97.608 2250.216 ;
    END
  END q[422]
  PIN q[423]
    DIRECTION OUTPUT ;
    USE SIGNAL ;
    SHAPE ABUTMENT ;
    PORT
      LAYER M5 ;
      RECT 97.776 2250.024 97.800 2250.216 ;
    END
  END q[423]
  PIN q[424]
    DIRECTION OUTPUT ;
    USE SIGNAL ;
    SHAPE ABUTMENT ;
    PORT
      LAYER M5 ;
      RECT 98.016 2250.024 98.040 2250.216 ;
    END
  END q[424]
  PIN q[425]
    DIRECTION OUTPUT ;
    USE SIGNAL ;
    SHAPE ABUTMENT ;
    PORT
      LAYER M5 ;
      RECT 98.256 2250.024 98.280 2250.216 ;
    END
  END q[425]
  PIN q[426]
    DIRECTION OUTPUT ;
    USE SIGNAL ;
    SHAPE ABUTMENT ;
    PORT
      LAYER M5 ;
      RECT 98.448 2250.024 98.472 2250.216 ;
    END
  END q[426]
  PIN q[427]
    DIRECTION OUTPUT ;
    USE SIGNAL ;
    SHAPE ABUTMENT ;
    PORT
      LAYER M5 ;
      RECT 98.688 2250.024 98.712 2250.216 ;
    END
  END q[427]
  PIN q[428]
    DIRECTION OUTPUT ;
    USE SIGNAL ;
    SHAPE ABUTMENT ;
    PORT
      LAYER M5 ;
      RECT 98.880 2250.024 98.904 2250.216 ;
    END
  END q[428]
  PIN q[429]
    DIRECTION OUTPUT ;
    USE SIGNAL ;
    SHAPE ABUTMENT ;
    PORT
      LAYER M5 ;
      RECT 99.120 2250.024 99.144 2250.216 ;
    END
  END q[429]
  PIN q[430]
    DIRECTION OUTPUT ;
    USE SIGNAL ;
    SHAPE ABUTMENT ;
    PORT
      LAYER M5 ;
      RECT 99.360 2250.024 99.384 2250.216 ;
    END
  END q[430]
  PIN q[431]
    DIRECTION OUTPUT ;
    USE SIGNAL ;
    SHAPE ABUTMENT ;
    PORT
      LAYER M5 ;
      RECT 99.552 2250.024 99.576 2250.216 ;
    END
  END q[431]
  PIN q[432]
    DIRECTION OUTPUT ;
    USE SIGNAL ;
    SHAPE ABUTMENT ;
    PORT
      LAYER M5 ;
      RECT 99.792 2250.024 99.816 2250.216 ;
    END
  END q[432]
  PIN q[433]
    DIRECTION OUTPUT ;
    USE SIGNAL ;
    SHAPE ABUTMENT ;
    PORT
      LAYER M5 ;
      RECT 99.984 2250.024 100.008 2250.216 ;
    END
  END q[433]
  PIN q[434]
    DIRECTION OUTPUT ;
    USE SIGNAL ;
    SHAPE ABUTMENT ;
    PORT
      LAYER M5 ;
      RECT 100.224 2250.024 100.248 2250.216 ;
    END
  END q[434]
  PIN q[435]
    DIRECTION OUTPUT ;
    USE SIGNAL ;
    SHAPE ABUTMENT ;
    PORT
      LAYER M5 ;
      RECT 100.464 2250.024 100.488 2250.216 ;
    END
  END q[435]
  PIN q[436]
    DIRECTION OUTPUT ;
    USE SIGNAL ;
    SHAPE ABUTMENT ;
    PORT
      LAYER M5 ;
      RECT 100.656 2250.024 100.680 2250.216 ;
    END
  END q[436]
  PIN q[437]
    DIRECTION OUTPUT ;
    USE SIGNAL ;
    SHAPE ABUTMENT ;
    PORT
      LAYER M5 ;
      RECT 100.896 2250.024 100.920 2250.216 ;
    END
  END q[437]
  PIN q[438]
    DIRECTION OUTPUT ;
    USE SIGNAL ;
    SHAPE ABUTMENT ;
    PORT
      LAYER M5 ;
      RECT 101.088 2250.024 101.112 2250.216 ;
    END
  END q[438]
  PIN q[439]
    DIRECTION OUTPUT ;
    USE SIGNAL ;
    SHAPE ABUTMENT ;
    PORT
      LAYER M5 ;
      RECT 101.328 2250.024 101.352 2250.216 ;
    END
  END q[439]
  PIN q[440]
    DIRECTION OUTPUT ;
    USE SIGNAL ;
    SHAPE ABUTMENT ;
    PORT
      LAYER M5 ;
      RECT 101.568 2250.024 101.592 2250.216 ;
    END
  END q[440]
  PIN q[441]
    DIRECTION OUTPUT ;
    USE SIGNAL ;
    SHAPE ABUTMENT ;
    PORT
      LAYER M5 ;
      RECT 101.760 2250.024 101.784 2250.216 ;
    END
  END q[441]
  PIN q[442]
    DIRECTION OUTPUT ;
    USE SIGNAL ;
    SHAPE ABUTMENT ;
    PORT
      LAYER M5 ;
      RECT 102.000 2250.024 102.024 2250.216 ;
    END
  END q[442]
  PIN q[443]
    DIRECTION OUTPUT ;
    USE SIGNAL ;
    SHAPE ABUTMENT ;
    PORT
      LAYER M5 ;
      RECT 102.192 2250.024 102.216 2250.216 ;
    END
  END q[443]
  PIN q[444]
    DIRECTION OUTPUT ;
    USE SIGNAL ;
    SHAPE ABUTMENT ;
    PORT
      LAYER M5 ;
      RECT 102.432 2250.024 102.456 2250.216 ;
    END
  END q[444]
  PIN q[445]
    DIRECTION OUTPUT ;
    USE SIGNAL ;
    SHAPE ABUTMENT ;
    PORT
      LAYER M5 ;
      RECT 102.672 2250.024 102.696 2250.216 ;
    END
  END q[445]
  PIN q[446]
    DIRECTION OUTPUT ;
    USE SIGNAL ;
    SHAPE ABUTMENT ;
    PORT
      LAYER M5 ;
      RECT 102.864 2250.024 102.888 2250.216 ;
    END
  END q[446]
  PIN q[447]
    DIRECTION OUTPUT ;
    USE SIGNAL ;
    SHAPE ABUTMENT ;
    PORT
      LAYER M5 ;
      RECT 103.104 2250.024 103.128 2250.216 ;
    END
  END q[447]
  PIN q[448]
    DIRECTION OUTPUT ;
    USE SIGNAL ;
    SHAPE ABUTMENT ;
    PORT
      LAYER M5 ;
      RECT 103.296 2250.024 103.320 2250.216 ;
    END
  END q[448]
  PIN q[449]
    DIRECTION OUTPUT ;
    USE SIGNAL ;
    SHAPE ABUTMENT ;
    PORT
      LAYER M5 ;
      RECT 103.536 2250.024 103.560 2250.216 ;
    END
  END q[449]
  PIN q[450]
    DIRECTION OUTPUT ;
    USE SIGNAL ;
    SHAPE ABUTMENT ;
    PORT
      LAYER M5 ;
      RECT 103.776 2250.024 103.800 2250.216 ;
    END
  END q[450]
  PIN q[451]
    DIRECTION OUTPUT ;
    USE SIGNAL ;
    SHAPE ABUTMENT ;
    PORT
      LAYER M5 ;
      RECT 103.968 2250.024 103.992 2250.216 ;
    END
  END q[451]
  PIN q[452]
    DIRECTION OUTPUT ;
    USE SIGNAL ;
    SHAPE ABUTMENT ;
    PORT
      LAYER M5 ;
      RECT 104.208 2250.024 104.232 2250.216 ;
    END
  END q[452]
  PIN q[453]
    DIRECTION OUTPUT ;
    USE SIGNAL ;
    SHAPE ABUTMENT ;
    PORT
      LAYER M5 ;
      RECT 104.400 2250.024 104.424 2250.216 ;
    END
  END q[453]
  PIN q[454]
    DIRECTION OUTPUT ;
    USE SIGNAL ;
    SHAPE ABUTMENT ;
    PORT
      LAYER M5 ;
      RECT 104.640 2250.024 104.664 2250.216 ;
    END
  END q[454]
  PIN q[455]
    DIRECTION OUTPUT ;
    USE SIGNAL ;
    SHAPE ABUTMENT ;
    PORT
      LAYER M5 ;
      RECT 104.832 2250.024 104.856 2250.216 ;
    END
  END q[455]
  PIN q[456]
    DIRECTION OUTPUT ;
    USE SIGNAL ;
    SHAPE ABUTMENT ;
    PORT
      LAYER M5 ;
      RECT 105.072 2250.024 105.096 2250.216 ;
    END
  END q[456]
  PIN q[457]
    DIRECTION OUTPUT ;
    USE SIGNAL ;
    SHAPE ABUTMENT ;
    PORT
      LAYER M5 ;
      RECT 105.312 2250.024 105.336 2250.216 ;
    END
  END q[457]
  PIN q[458]
    DIRECTION OUTPUT ;
    USE SIGNAL ;
    SHAPE ABUTMENT ;
    PORT
      LAYER M5 ;
      RECT 105.504 2250.024 105.528 2250.216 ;
    END
  END q[458]
  PIN q[459]
    DIRECTION OUTPUT ;
    USE SIGNAL ;
    SHAPE ABUTMENT ;
    PORT
      LAYER M5 ;
      RECT 105.744 2250.024 105.768 2250.216 ;
    END
  END q[459]
  PIN q[460]
    DIRECTION OUTPUT ;
    USE SIGNAL ;
    SHAPE ABUTMENT ;
    PORT
      LAYER M5 ;
      RECT 105.936 2250.024 105.960 2250.216 ;
    END
  END q[460]
  PIN q[461]
    DIRECTION OUTPUT ;
    USE SIGNAL ;
    SHAPE ABUTMENT ;
    PORT
      LAYER M5 ;
      RECT 106.176 2250.024 106.200 2250.216 ;
    END
  END q[461]
  PIN q[462]
    DIRECTION OUTPUT ;
    USE SIGNAL ;
    SHAPE ABUTMENT ;
    PORT
      LAYER M5 ;
      RECT 106.416 2250.024 106.440 2250.216 ;
    END
  END q[462]
  PIN q[463]
    DIRECTION OUTPUT ;
    USE SIGNAL ;
    SHAPE ABUTMENT ;
    PORT
      LAYER M5 ;
      RECT 106.608 2250.024 106.632 2250.216 ;
    END
  END q[463]
  PIN q[464]
    DIRECTION OUTPUT ;
    USE SIGNAL ;
    SHAPE ABUTMENT ;
    PORT
      LAYER M5 ;
      RECT 106.848 2250.024 106.872 2250.216 ;
    END
  END q[464]
  PIN q[465]
    DIRECTION OUTPUT ;
    USE SIGNAL ;
    SHAPE ABUTMENT ;
    PORT
      LAYER M5 ;
      RECT 107.040 2250.024 107.064 2250.216 ;
    END
  END q[465]
  PIN q[466]
    DIRECTION OUTPUT ;
    USE SIGNAL ;
    SHAPE ABUTMENT ;
    PORT
      LAYER M5 ;
      RECT 107.280 2250.024 107.304 2250.216 ;
    END
  END q[466]
  PIN q[467]
    DIRECTION OUTPUT ;
    USE SIGNAL ;
    SHAPE ABUTMENT ;
    PORT
      LAYER M5 ;
      RECT 107.520 2250.024 107.544 2250.216 ;
    END
  END q[467]
  PIN q[468]
    DIRECTION OUTPUT ;
    USE SIGNAL ;
    SHAPE ABUTMENT ;
    PORT
      LAYER M5 ;
      RECT 107.712 2250.024 107.736 2250.216 ;
    END
  END q[468]
  PIN q[469]
    DIRECTION OUTPUT ;
    USE SIGNAL ;
    SHAPE ABUTMENT ;
    PORT
      LAYER M5 ;
      RECT 107.952 2250.024 107.976 2250.216 ;
    END
  END q[469]
  PIN q[470]
    DIRECTION OUTPUT ;
    USE SIGNAL ;
    SHAPE ABUTMENT ;
    PORT
      LAYER M5 ;
      RECT 108.144 2250.024 108.168 2250.216 ;
    END
  END q[470]
  PIN q[471]
    DIRECTION OUTPUT ;
    USE SIGNAL ;
    SHAPE ABUTMENT ;
    PORT
      LAYER M5 ;
      RECT 108.384 2250.024 108.408 2250.216 ;
    END
  END q[471]
  PIN q[472]
    DIRECTION OUTPUT ;
    USE SIGNAL ;
    SHAPE ABUTMENT ;
    PORT
      LAYER M5 ;
      RECT 108.624 2250.024 108.648 2250.216 ;
    END
  END q[472]
  PIN q[473]
    DIRECTION OUTPUT ;
    USE SIGNAL ;
    SHAPE ABUTMENT ;
    PORT
      LAYER M5 ;
      RECT 108.816 2250.024 108.840 2250.216 ;
    END
  END q[473]
  PIN q[474]
    DIRECTION OUTPUT ;
    USE SIGNAL ;
    SHAPE ABUTMENT ;
    PORT
      LAYER M5 ;
      RECT 109.056 2250.024 109.080 2250.216 ;
    END
  END q[474]
  PIN q[475]
    DIRECTION OUTPUT ;
    USE SIGNAL ;
    SHAPE ABUTMENT ;
    PORT
      LAYER M5 ;
      RECT 109.248 2250.024 109.272 2250.216 ;
    END
  END q[475]
  PIN q[476]
    DIRECTION OUTPUT ;
    USE SIGNAL ;
    SHAPE ABUTMENT ;
    PORT
      LAYER M5 ;
      RECT 109.488 2250.024 109.512 2250.216 ;
    END
  END q[476]
  PIN q[477]
    DIRECTION OUTPUT ;
    USE SIGNAL ;
    SHAPE ABUTMENT ;
    PORT
      LAYER M5 ;
      RECT 109.728 2250.024 109.752 2250.216 ;
    END
  END q[477]
  PIN q[478]
    DIRECTION OUTPUT ;
    USE SIGNAL ;
    SHAPE ABUTMENT ;
    PORT
      LAYER M5 ;
      RECT 109.920 2250.024 109.944 2250.216 ;
    END
  END q[478]
  PIN q[479]
    DIRECTION OUTPUT ;
    USE SIGNAL ;
    SHAPE ABUTMENT ;
    PORT
      LAYER M5 ;
      RECT 110.160 2250.024 110.184 2250.216 ;
    END
  END q[479]
  PIN q[480]
    DIRECTION OUTPUT ;
    USE SIGNAL ;
    SHAPE ABUTMENT ;
    PORT
      LAYER M5 ;
      RECT 110.352 2250.024 110.376 2250.216 ;
    END
  END q[480]
  PIN q[481]
    DIRECTION OUTPUT ;
    USE SIGNAL ;
    SHAPE ABUTMENT ;
    PORT
      LAYER M5 ;
      RECT 110.592 2250.024 110.616 2250.216 ;
    END
  END q[481]
  PIN q[482]
    DIRECTION OUTPUT ;
    USE SIGNAL ;
    SHAPE ABUTMENT ;
    PORT
      LAYER M5 ;
      RECT 110.832 2250.024 110.856 2250.216 ;
    END
  END q[482]
  PIN q[483]
    DIRECTION OUTPUT ;
    USE SIGNAL ;
    SHAPE ABUTMENT ;
    PORT
      LAYER M5 ;
      RECT 111.024 2250.024 111.048 2250.216 ;
    END
  END q[483]
  PIN q[484]
    DIRECTION OUTPUT ;
    USE SIGNAL ;
    SHAPE ABUTMENT ;
    PORT
      LAYER M5 ;
      RECT 111.264 2250.024 111.288 2250.216 ;
    END
  END q[484]
  PIN q[485]
    DIRECTION OUTPUT ;
    USE SIGNAL ;
    SHAPE ABUTMENT ;
    PORT
      LAYER M5 ;
      RECT 111.456 2250.024 111.480 2250.216 ;
    END
  END q[485]
  PIN q[486]
    DIRECTION OUTPUT ;
    USE SIGNAL ;
    SHAPE ABUTMENT ;
    PORT
      LAYER M5 ;
      RECT 111.696 2250.024 111.720 2250.216 ;
    END
  END q[486]
  PIN q[487]
    DIRECTION OUTPUT ;
    USE SIGNAL ;
    SHAPE ABUTMENT ;
    PORT
      LAYER M5 ;
      RECT 111.936 2250.024 111.960 2250.216 ;
    END
  END q[487]
  PIN q[488]
    DIRECTION OUTPUT ;
    USE SIGNAL ;
    SHAPE ABUTMENT ;
    PORT
      LAYER M5 ;
      RECT 112.128 2250.024 112.152 2250.216 ;
    END
  END q[488]
  PIN q[489]
    DIRECTION OUTPUT ;
    USE SIGNAL ;
    SHAPE ABUTMENT ;
    PORT
      LAYER M5 ;
      RECT 112.368 2250.024 112.392 2250.216 ;
    END
  END q[489]
  PIN q[490]
    DIRECTION OUTPUT ;
    USE SIGNAL ;
    SHAPE ABUTMENT ;
    PORT
      LAYER M5 ;
      RECT 112.560 2250.024 112.584 2250.216 ;
    END
  END q[490]
  PIN q[491]
    DIRECTION OUTPUT ;
    USE SIGNAL ;
    SHAPE ABUTMENT ;
    PORT
      LAYER M5 ;
      RECT 112.800 2250.024 112.824 2250.216 ;
    END
  END q[491]
  PIN q[492]
    DIRECTION OUTPUT ;
    USE SIGNAL ;
    SHAPE ABUTMENT ;
    PORT
      LAYER M5 ;
      RECT 113.040 2250.024 113.064 2250.216 ;
    END
  END q[492]
  PIN q[493]
    DIRECTION OUTPUT ;
    USE SIGNAL ;
    SHAPE ABUTMENT ;
    PORT
      LAYER M5 ;
      RECT 113.232 2250.024 113.256 2250.216 ;
    END
  END q[493]
  PIN q[494]
    DIRECTION OUTPUT ;
    USE SIGNAL ;
    SHAPE ABUTMENT ;
    PORT
      LAYER M5 ;
      RECT 113.472 2250.024 113.496 2250.216 ;
    END
  END q[494]
  PIN q[495]
    DIRECTION OUTPUT ;
    USE SIGNAL ;
    SHAPE ABUTMENT ;
    PORT
      LAYER M5 ;
      RECT 113.664 2250.024 113.688 2250.216 ;
    END
  END q[495]
  PIN q[496]
    DIRECTION OUTPUT ;
    USE SIGNAL ;
    SHAPE ABUTMENT ;
    PORT
      LAYER M5 ;
      RECT 113.904 2250.024 113.928 2250.216 ;
    END
  END q[496]
  PIN q[497]
    DIRECTION OUTPUT ;
    USE SIGNAL ;
    SHAPE ABUTMENT ;
    PORT
      LAYER M5 ;
      RECT 114.144 2250.024 114.168 2250.216 ;
    END
  END q[497]
  PIN q[498]
    DIRECTION OUTPUT ;
    USE SIGNAL ;
    SHAPE ABUTMENT ;
    PORT
      LAYER M5 ;
      RECT 114.336 2250.024 114.360 2250.216 ;
    END
  END q[498]
  PIN q[499]
    DIRECTION OUTPUT ;
    USE SIGNAL ;
    SHAPE ABUTMENT ;
    PORT
      LAYER M5 ;
      RECT 114.576 2250.024 114.600 2250.216 ;
    END
  END q[499]
  PIN q[500]
    DIRECTION OUTPUT ;
    USE SIGNAL ;
    SHAPE ABUTMENT ;
    PORT
      LAYER M5 ;
      RECT 114.768 2250.024 114.792 2250.216 ;
    END
  END q[500]
  PIN q[501]
    DIRECTION OUTPUT ;
    USE SIGNAL ;
    SHAPE ABUTMENT ;
    PORT
      LAYER M5 ;
      RECT 115.008 2250.024 115.032 2250.216 ;
    END
  END q[501]
  PIN q[502]
    DIRECTION OUTPUT ;
    USE SIGNAL ;
    SHAPE ABUTMENT ;
    PORT
      LAYER M5 ;
      RECT 115.200 2250.024 115.224 2250.216 ;
    END
  END q[502]
  PIN q[503]
    DIRECTION OUTPUT ;
    USE SIGNAL ;
    SHAPE ABUTMENT ;
    PORT
      LAYER M5 ;
      RECT 115.440 2250.024 115.464 2250.216 ;
    END
  END q[503]
  PIN q[504]
    DIRECTION OUTPUT ;
    USE SIGNAL ;
    SHAPE ABUTMENT ;
    PORT
      LAYER M5 ;
      RECT 115.680 2250.024 115.704 2250.216 ;
    END
  END q[504]
  PIN q[505]
    DIRECTION OUTPUT ;
    USE SIGNAL ;
    SHAPE ABUTMENT ;
    PORT
      LAYER M5 ;
      RECT 115.872 2250.024 115.896 2250.216 ;
    END
  END q[505]
  PIN q[506]
    DIRECTION OUTPUT ;
    USE SIGNAL ;
    SHAPE ABUTMENT ;
    PORT
      LAYER M5 ;
      RECT 116.112 2250.024 116.136 2250.216 ;
    END
  END q[506]
  PIN q[507]
    DIRECTION OUTPUT ;
    USE SIGNAL ;
    SHAPE ABUTMENT ;
    PORT
      LAYER M5 ;
      RECT 116.304 2250.024 116.328 2250.216 ;
    END
  END q[507]
  PIN q[508]
    DIRECTION OUTPUT ;
    USE SIGNAL ;
    SHAPE ABUTMENT ;
    PORT
      LAYER M5 ;
      RECT 116.544 2250.024 116.568 2250.216 ;
    END
  END q[508]
  PIN q[509]
    DIRECTION OUTPUT ;
    USE SIGNAL ;
    SHAPE ABUTMENT ;
    PORT
      LAYER M5 ;
      RECT 116.784 2250.024 116.808 2250.216 ;
    END
  END q[509]
  PIN q[510]
    DIRECTION OUTPUT ;
    USE SIGNAL ;
    SHAPE ABUTMENT ;
    PORT
      LAYER M5 ;
      RECT 116.976 2250.024 117.000 2250.216 ;
    END
  END q[510]
  PIN q[511]
    DIRECTION OUTPUT ;
    USE SIGNAL ;
    SHAPE ABUTMENT ;
    PORT
      LAYER M5 ;
      RECT 117.216 2250.024 117.240 2250.216 ;
    END
  END q[511]
  PIN q[512]
    DIRECTION OUTPUT ;
    USE SIGNAL ;
    SHAPE ABUTMENT ;
    PORT
      LAYER M5 ;
      RECT 117.408 2250.024 117.432 2250.216 ;
    END
  END q[512]
  PIN q[513]
    DIRECTION OUTPUT ;
    USE SIGNAL ;
    SHAPE ABUTMENT ;
    PORT
      LAYER M5 ;
      RECT 117.648 2250.024 117.672 2250.216 ;
    END
  END q[513]
  PIN q[514]
    DIRECTION OUTPUT ;
    USE SIGNAL ;
    SHAPE ABUTMENT ;
    PORT
      LAYER M5 ;
      RECT 117.888 2250.024 117.912 2250.216 ;
    END
  END q[514]
  PIN q[515]
    DIRECTION OUTPUT ;
    USE SIGNAL ;
    SHAPE ABUTMENT ;
    PORT
      LAYER M5 ;
      RECT 118.080 2250.024 118.104 2250.216 ;
    END
  END q[515]
  PIN q[516]
    DIRECTION OUTPUT ;
    USE SIGNAL ;
    SHAPE ABUTMENT ;
    PORT
      LAYER M5 ;
      RECT 118.320 2250.024 118.344 2250.216 ;
    END
  END q[516]
  PIN q[517]
    DIRECTION OUTPUT ;
    USE SIGNAL ;
    SHAPE ABUTMENT ;
    PORT
      LAYER M5 ;
      RECT 118.512 2250.024 118.536 2250.216 ;
    END
  END q[517]
  PIN q[518]
    DIRECTION OUTPUT ;
    USE SIGNAL ;
    SHAPE ABUTMENT ;
    PORT
      LAYER M5 ;
      RECT 118.752 2250.024 118.776 2250.216 ;
    END
  END q[518]
  PIN q[519]
    DIRECTION OUTPUT ;
    USE SIGNAL ;
    SHAPE ABUTMENT ;
    PORT
      LAYER M5 ;
      RECT 118.992 2250.024 119.016 2250.216 ;
    END
  END q[519]
  PIN q[520]
    DIRECTION OUTPUT ;
    USE SIGNAL ;
    SHAPE ABUTMENT ;
    PORT
      LAYER M5 ;
      RECT 119.184 2250.024 119.208 2250.216 ;
    END
  END q[520]
  PIN q[521]
    DIRECTION OUTPUT ;
    USE SIGNAL ;
    SHAPE ABUTMENT ;
    PORT
      LAYER M5 ;
      RECT 119.424 2250.024 119.448 2250.216 ;
    END
  END q[521]
  PIN q[522]
    DIRECTION OUTPUT ;
    USE SIGNAL ;
    SHAPE ABUTMENT ;
    PORT
      LAYER M5 ;
      RECT 119.616 2250.024 119.640 2250.216 ;
    END
  END q[522]
  PIN q[523]
    DIRECTION OUTPUT ;
    USE SIGNAL ;
    SHAPE ABUTMENT ;
    PORT
      LAYER M5 ;
      RECT 119.856 2250.024 119.880 2250.216 ;
    END
  END q[523]
  PIN q[524]
    DIRECTION OUTPUT ;
    USE SIGNAL ;
    SHAPE ABUTMENT ;
    PORT
      LAYER M5 ;
      RECT 120.096 2250.024 120.120 2250.216 ;
    END
  END q[524]
  PIN q[525]
    DIRECTION OUTPUT ;
    USE SIGNAL ;
    SHAPE ABUTMENT ;
    PORT
      LAYER M5 ;
      RECT 120.288 2250.024 120.312 2250.216 ;
    END
  END q[525]
  PIN q[526]
    DIRECTION OUTPUT ;
    USE SIGNAL ;
    SHAPE ABUTMENT ;
    PORT
      LAYER M5 ;
      RECT 120.528 2250.024 120.552 2250.216 ;
    END
  END q[526]
  PIN q[527]
    DIRECTION OUTPUT ;
    USE SIGNAL ;
    SHAPE ABUTMENT ;
    PORT
      LAYER M5 ;
      RECT 120.720 2250.024 120.744 2250.216 ;
    END
  END q[527]
  PIN q[528]
    DIRECTION OUTPUT ;
    USE SIGNAL ;
    SHAPE ABUTMENT ;
    PORT
      LAYER M5 ;
      RECT 120.960 2250.024 120.984 2250.216 ;
    END
  END q[528]
  PIN q[529]
    DIRECTION OUTPUT ;
    USE SIGNAL ;
    SHAPE ABUTMENT ;
    PORT
      LAYER M5 ;
      RECT 121.200 2250.024 121.224 2250.216 ;
    END
  END q[529]
  PIN q[530]
    DIRECTION OUTPUT ;
    USE SIGNAL ;
    SHAPE ABUTMENT ;
    PORT
      LAYER M5 ;
      RECT 121.392 2250.024 121.416 2250.216 ;
    END
  END q[530]
  PIN q[531]
    DIRECTION OUTPUT ;
    USE SIGNAL ;
    SHAPE ABUTMENT ;
    PORT
      LAYER M5 ;
      RECT 121.632 2250.024 121.656 2250.216 ;
    END
  END q[531]
  PIN q[532]
    DIRECTION OUTPUT ;
    USE SIGNAL ;
    SHAPE ABUTMENT ;
    PORT
      LAYER M5 ;
      RECT 121.824 2250.024 121.848 2250.216 ;
    END
  END q[532]
  PIN q[533]
    DIRECTION OUTPUT ;
    USE SIGNAL ;
    SHAPE ABUTMENT ;
    PORT
      LAYER M5 ;
      RECT 122.064 2250.024 122.088 2250.216 ;
    END
  END q[533]
  PIN q[534]
    DIRECTION OUTPUT ;
    USE SIGNAL ;
    SHAPE ABUTMENT ;
    PORT
      LAYER M5 ;
      RECT 122.304 2250.024 122.328 2250.216 ;
    END
  END q[534]
  PIN q[535]
    DIRECTION OUTPUT ;
    USE SIGNAL ;
    SHAPE ABUTMENT ;
    PORT
      LAYER M5 ;
      RECT 122.496 2250.024 122.520 2250.216 ;
    END
  END q[535]
  PIN q[536]
    DIRECTION OUTPUT ;
    USE SIGNAL ;
    SHAPE ABUTMENT ;
    PORT
      LAYER M5 ;
      RECT 122.736 2250.024 122.760 2250.216 ;
    END
  END q[536]
  PIN q[537]
    DIRECTION OUTPUT ;
    USE SIGNAL ;
    SHAPE ABUTMENT ;
    PORT
      LAYER M5 ;
      RECT 122.928 2250.024 122.952 2250.216 ;
    END
  END q[537]
  PIN q[538]
    DIRECTION OUTPUT ;
    USE SIGNAL ;
    SHAPE ABUTMENT ;
    PORT
      LAYER M5 ;
      RECT 123.168 2250.024 123.192 2250.216 ;
    END
  END q[538]
  PIN q[539]
    DIRECTION OUTPUT ;
    USE SIGNAL ;
    SHAPE ABUTMENT ;
    PORT
      LAYER M5 ;
      RECT 123.408 2250.024 123.432 2250.216 ;
    END
  END q[539]
  PIN q[540]
    DIRECTION OUTPUT ;
    USE SIGNAL ;
    SHAPE ABUTMENT ;
    PORT
      LAYER M5 ;
      RECT 123.600 2250.024 123.624 2250.216 ;
    END
  END q[540]
  PIN q[541]
    DIRECTION OUTPUT ;
    USE SIGNAL ;
    SHAPE ABUTMENT ;
    PORT
      LAYER M5 ;
      RECT 123.840 2250.024 123.864 2250.216 ;
    END
  END q[541]
  PIN q[542]
    DIRECTION OUTPUT ;
    USE SIGNAL ;
    SHAPE ABUTMENT ;
    PORT
      LAYER M5 ;
      RECT 124.032 2250.024 124.056 2250.216 ;
    END
  END q[542]
  PIN q[543]
    DIRECTION OUTPUT ;
    USE SIGNAL ;
    SHAPE ABUTMENT ;
    PORT
      LAYER M5 ;
      RECT 124.272 2250.024 124.296 2250.216 ;
    END
  END q[543]
  PIN VSS
    DIRECTION INOUT ;
    USE GROUND ;
    PORT
      LAYER M4 ;
      RECT 0.492 1.200 128.532 1.296 ;
      RECT 0.492 3.600 128.532 3.696 ;
      RECT 0.492 6.000 128.532 6.096 ;
      RECT 0.492 8.400 128.532 8.496 ;
      RECT 0.492 10.800 128.532 10.896 ;
      RECT 0.492 13.200 128.532 13.296 ;
      RECT 0.492 15.600 128.532 15.696 ;
      RECT 0.492 18.000 128.532 18.096 ;
      RECT 0.492 20.400 128.532 20.496 ;
      RECT 0.492 22.800 128.532 22.896 ;
      RECT 0.492 25.200 128.532 25.296 ;
      RECT 0.492 27.600 128.532 27.696 ;
      RECT 0.492 30.000 128.532 30.096 ;
      RECT 0.492 32.400 128.532 32.496 ;
      RECT 0.492 34.800 128.532 34.896 ;
      RECT 0.492 37.200 128.532 37.296 ;
      RECT 0.492 39.600 128.532 39.696 ;
      RECT 0.492 42.000 128.532 42.096 ;
      RECT 0.492 44.400 128.532 44.496 ;
      RECT 0.492 46.800 128.532 46.896 ;
      RECT 0.492 49.200 128.532 49.296 ;
      RECT 0.492 51.600 128.532 51.696 ;
      RECT 0.492 54.000 128.532 54.096 ;
      RECT 0.492 56.400 128.532 56.496 ;
      RECT 0.492 58.800 128.532 58.896 ;
      RECT 0.492 61.200 128.532 61.296 ;
      RECT 0.492 63.600 128.532 63.696 ;
      RECT 0.492 66.000 128.532 66.096 ;
      RECT 0.492 68.400 128.532 68.496 ;
      RECT 0.492 70.800 128.532 70.896 ;
      RECT 0.492 73.200 128.532 73.296 ;
      RECT 0.492 75.600 128.532 75.696 ;
      RECT 0.492 78.000 128.532 78.096 ;
      RECT 0.492 80.400 128.532 80.496 ;
      RECT 0.492 82.800 128.532 82.896 ;
      RECT 0.492 85.200 128.532 85.296 ;
      RECT 0.492 87.600 128.532 87.696 ;
      RECT 0.492 90.000 128.532 90.096 ;
      RECT 0.492 92.400 128.532 92.496 ;
      RECT 0.492 94.800 128.532 94.896 ;
      RECT 0.492 97.200 128.532 97.296 ;
      RECT 0.492 99.600 128.532 99.696 ;
      RECT 0.492 102.000 128.532 102.096 ;
      RECT 0.492 104.400 128.532 104.496 ;
      RECT 0.492 106.800 128.532 106.896 ;
      RECT 0.492 109.200 128.532 109.296 ;
      RECT 0.492 111.600 128.532 111.696 ;
      RECT 0.492 114.000 128.532 114.096 ;
      RECT 0.492 116.400 128.532 116.496 ;
      RECT 0.492 118.800 128.532 118.896 ;
      RECT 0.492 121.200 128.532 121.296 ;
      RECT 0.492 123.600 128.532 123.696 ;
      RECT 0.492 126.000 128.532 126.096 ;
      RECT 0.492 128.400 128.532 128.496 ;
      RECT 0.492 130.800 128.532 130.896 ;
      RECT 0.492 133.200 128.532 133.296 ;
      RECT 0.492 135.600 128.532 135.696 ;
      RECT 0.492 138.000 128.532 138.096 ;
      RECT 0.492 140.400 128.532 140.496 ;
      RECT 0.492 142.800 128.532 142.896 ;
      RECT 0.492 145.200 128.532 145.296 ;
      RECT 0.492 147.600 128.532 147.696 ;
      RECT 0.492 150.000 128.532 150.096 ;
      RECT 0.492 152.400 128.532 152.496 ;
      RECT 0.492 154.800 128.532 154.896 ;
      RECT 0.492 157.200 128.532 157.296 ;
      RECT 0.492 159.600 128.532 159.696 ;
      RECT 0.492 162.000 128.532 162.096 ;
      RECT 0.492 164.400 128.532 164.496 ;
      RECT 0.492 166.800 128.532 166.896 ;
      RECT 0.492 169.200 128.532 169.296 ;
      RECT 0.492 171.600 128.532 171.696 ;
      RECT 0.492 174.000 128.532 174.096 ;
      RECT 0.492 176.400 128.532 176.496 ;
      RECT 0.492 178.800 128.532 178.896 ;
      RECT 0.492 181.200 128.532 181.296 ;
      RECT 0.492 183.600 128.532 183.696 ;
      RECT 0.492 186.000 128.532 186.096 ;
      RECT 0.492 188.400 128.532 188.496 ;
      RECT 0.492 190.800 128.532 190.896 ;
      RECT 0.492 193.200 128.532 193.296 ;
      RECT 0.492 195.600 128.532 195.696 ;
      RECT 0.492 198.000 128.532 198.096 ;
      RECT 0.492 200.400 128.532 200.496 ;
      RECT 0.492 202.800 128.532 202.896 ;
      RECT 0.492 205.200 128.532 205.296 ;
      RECT 0.492 207.600 128.532 207.696 ;
      RECT 0.492 210.000 128.532 210.096 ;
      RECT 0.492 212.400 128.532 212.496 ;
      RECT 0.492 214.800 128.532 214.896 ;
      RECT 0.492 217.200 128.532 217.296 ;
      RECT 0.492 219.600 128.532 219.696 ;
      RECT 0.492 222.000 128.532 222.096 ;
      RECT 0.492 224.400 128.532 224.496 ;
      RECT 0.492 226.800 128.532 226.896 ;
      RECT 0.492 229.200 128.532 229.296 ;
      RECT 0.492 231.600 128.532 231.696 ;
      RECT 0.492 234.000 128.532 234.096 ;
      RECT 0.492 236.400 128.532 236.496 ;
      RECT 0.492 238.800 128.532 238.896 ;
      RECT 0.492 241.200 128.532 241.296 ;
      RECT 0.492 243.600 128.532 243.696 ;
      RECT 0.492 246.000 128.532 246.096 ;
      RECT 0.492 248.400 128.532 248.496 ;
      RECT 0.492 250.800 128.532 250.896 ;
      RECT 0.492 253.200 128.532 253.296 ;
      RECT 0.492 255.600 128.532 255.696 ;
      RECT 0.492 258.000 128.532 258.096 ;
      RECT 0.492 260.400 128.532 260.496 ;
      RECT 0.492 262.800 128.532 262.896 ;
      RECT 0.492 265.200 128.532 265.296 ;
      RECT 0.492 267.600 128.532 267.696 ;
      RECT 0.492 270.000 128.532 270.096 ;
      RECT 0.492 272.400 128.532 272.496 ;
      RECT 0.492 274.800 128.532 274.896 ;
      RECT 0.492 277.200 128.532 277.296 ;
      RECT 0.492 279.600 128.532 279.696 ;
      RECT 0.492 282.000 128.532 282.096 ;
      RECT 0.492 284.400 128.532 284.496 ;
      RECT 0.492 286.800 128.532 286.896 ;
      RECT 0.492 289.200 128.532 289.296 ;
      RECT 0.492 291.600 128.532 291.696 ;
      RECT 0.492 294.000 128.532 294.096 ;
      RECT 0.492 296.400 128.532 296.496 ;
      RECT 0.492 298.800 128.532 298.896 ;
      RECT 0.492 301.200 128.532 301.296 ;
      RECT 0.492 303.600 128.532 303.696 ;
      RECT 0.492 306.000 128.532 306.096 ;
      RECT 0.492 308.400 128.532 308.496 ;
      RECT 0.492 310.800 128.532 310.896 ;
      RECT 0.492 313.200 128.532 313.296 ;
      RECT 0.492 315.600 128.532 315.696 ;
      RECT 0.492 318.000 128.532 318.096 ;
      RECT 0.492 320.400 128.532 320.496 ;
      RECT 0.492 322.800 128.532 322.896 ;
      RECT 0.492 325.200 128.532 325.296 ;
      RECT 0.492 327.600 128.532 327.696 ;
      RECT 0.492 330.000 128.532 330.096 ;
      RECT 0.492 332.400 128.532 332.496 ;
      RECT 0.492 334.800 128.532 334.896 ;
      RECT 0.492 337.200 128.532 337.296 ;
      RECT 0.492 339.600 128.532 339.696 ;
      RECT 0.492 342.000 128.532 342.096 ;
      RECT 0.492 344.400 128.532 344.496 ;
      RECT 0.492 346.800 128.532 346.896 ;
      RECT 0.492 349.200 128.532 349.296 ;
      RECT 0.492 351.600 128.532 351.696 ;
      RECT 0.492 354.000 128.532 354.096 ;
      RECT 0.492 356.400 128.532 356.496 ;
      RECT 0.492 358.800 128.532 358.896 ;
      RECT 0.492 361.200 128.532 361.296 ;
      RECT 0.492 363.600 128.532 363.696 ;
      RECT 0.492 366.000 128.532 366.096 ;
      RECT 0.492 368.400 128.532 368.496 ;
      RECT 0.492 370.800 128.532 370.896 ;
      RECT 0.492 373.200 128.532 373.296 ;
      RECT 0.492 375.600 128.532 375.696 ;
      RECT 0.492 378.000 128.532 378.096 ;
      RECT 0.492 380.400 128.532 380.496 ;
      RECT 0.492 382.800 128.532 382.896 ;
      RECT 0.492 385.200 128.532 385.296 ;
      RECT 0.492 387.600 128.532 387.696 ;
      RECT 0.492 390.000 128.532 390.096 ;
      RECT 0.492 392.400 128.532 392.496 ;
      RECT 0.492 394.800 128.532 394.896 ;
      RECT 0.492 397.200 128.532 397.296 ;
      RECT 0.492 399.600 128.532 399.696 ;
      RECT 0.492 402.000 128.532 402.096 ;
      RECT 0.492 404.400 128.532 404.496 ;
      RECT 0.492 406.800 128.532 406.896 ;
      RECT 0.492 409.200 128.532 409.296 ;
      RECT 0.492 411.600 128.532 411.696 ;
      RECT 0.492 414.000 128.532 414.096 ;
      RECT 0.492 416.400 128.532 416.496 ;
      RECT 0.492 418.800 128.532 418.896 ;
      RECT 0.492 421.200 128.532 421.296 ;
      RECT 0.492 423.600 128.532 423.696 ;
      RECT 0.492 426.000 128.532 426.096 ;
      RECT 0.492 428.400 128.532 428.496 ;
      RECT 0.492 430.800 128.532 430.896 ;
      RECT 0.492 433.200 128.532 433.296 ;
      RECT 0.492 435.600 128.532 435.696 ;
      RECT 0.492 438.000 128.532 438.096 ;
      RECT 0.492 440.400 128.532 440.496 ;
      RECT 0.492 442.800 128.532 442.896 ;
      RECT 0.492 445.200 128.532 445.296 ;
      RECT 0.492 447.600 128.532 447.696 ;
      RECT 0.492 450.000 128.532 450.096 ;
      RECT 0.492 452.400 128.532 452.496 ;
      RECT 0.492 454.800 128.532 454.896 ;
      RECT 0.492 457.200 128.532 457.296 ;
      RECT 0.492 459.600 128.532 459.696 ;
      RECT 0.492 462.000 128.532 462.096 ;
      RECT 0.492 464.400 128.532 464.496 ;
      RECT 0.492 466.800 128.532 466.896 ;
      RECT 0.492 469.200 128.532 469.296 ;
      RECT 0.492 471.600 128.532 471.696 ;
      RECT 0.492 474.000 128.532 474.096 ;
      RECT 0.492 476.400 128.532 476.496 ;
      RECT 0.492 478.800 128.532 478.896 ;
      RECT 0.492 481.200 128.532 481.296 ;
      RECT 0.492 483.600 128.532 483.696 ;
      RECT 0.492 486.000 128.532 486.096 ;
      RECT 0.492 488.400 128.532 488.496 ;
      RECT 0.492 490.800 128.532 490.896 ;
      RECT 0.492 493.200 128.532 493.296 ;
      RECT 0.492 495.600 128.532 495.696 ;
      RECT 0.492 498.000 128.532 498.096 ;
      RECT 0.492 500.400 128.532 500.496 ;
      RECT 0.492 502.800 128.532 502.896 ;
      RECT 0.492 505.200 128.532 505.296 ;
      RECT 0.492 507.600 128.532 507.696 ;
      RECT 0.492 510.000 128.532 510.096 ;
      RECT 0.492 512.400 128.532 512.496 ;
      RECT 0.492 514.800 128.532 514.896 ;
      RECT 0.492 517.200 128.532 517.296 ;
      RECT 0.492 519.600 128.532 519.696 ;
      RECT 0.492 522.000 128.532 522.096 ;
      RECT 0.492 524.400 128.532 524.496 ;
      RECT 0.492 526.800 128.532 526.896 ;
      RECT 0.492 529.200 128.532 529.296 ;
      RECT 0.492 531.600 128.532 531.696 ;
      RECT 0.492 534.000 128.532 534.096 ;
      RECT 0.492 536.400 128.532 536.496 ;
      RECT 0.492 538.800 128.532 538.896 ;
      RECT 0.492 541.200 128.532 541.296 ;
      RECT 0.492 543.600 128.532 543.696 ;
      RECT 0.492 546.000 128.532 546.096 ;
      RECT 0.492 548.400 128.532 548.496 ;
      RECT 0.492 550.800 128.532 550.896 ;
      RECT 0.492 553.200 128.532 553.296 ;
      RECT 0.492 555.600 128.532 555.696 ;
      RECT 0.492 558.000 128.532 558.096 ;
      RECT 0.492 560.400 128.532 560.496 ;
      RECT 0.492 562.800 128.532 562.896 ;
      RECT 0.492 565.200 128.532 565.296 ;
      RECT 0.492 567.600 128.532 567.696 ;
      RECT 0.492 570.000 128.532 570.096 ;
      RECT 0.492 572.400 128.532 572.496 ;
      RECT 0.492 574.800 128.532 574.896 ;
      RECT 0.492 577.200 128.532 577.296 ;
      RECT 0.492 579.600 128.532 579.696 ;
      RECT 0.492 582.000 128.532 582.096 ;
      RECT 0.492 584.400 128.532 584.496 ;
      RECT 0.492 586.800 128.532 586.896 ;
      RECT 0.492 589.200 128.532 589.296 ;
      RECT 0.492 591.600 128.532 591.696 ;
      RECT 0.492 594.000 128.532 594.096 ;
      RECT 0.492 596.400 128.532 596.496 ;
      RECT 0.492 598.800 128.532 598.896 ;
      RECT 0.492 601.200 128.532 601.296 ;
      RECT 0.492 603.600 128.532 603.696 ;
      RECT 0.492 606.000 128.532 606.096 ;
      RECT 0.492 608.400 128.532 608.496 ;
      RECT 0.492 610.800 128.532 610.896 ;
      RECT 0.492 613.200 128.532 613.296 ;
      RECT 0.492 615.600 128.532 615.696 ;
      RECT 0.492 618.000 128.532 618.096 ;
      RECT 0.492 620.400 128.532 620.496 ;
      RECT 0.492 622.800 128.532 622.896 ;
      RECT 0.492 625.200 128.532 625.296 ;
      RECT 0.492 627.600 128.532 627.696 ;
      RECT 0.492 630.000 128.532 630.096 ;
      RECT 0.492 632.400 128.532 632.496 ;
      RECT 0.492 634.800 128.532 634.896 ;
      RECT 0.492 637.200 128.532 637.296 ;
      RECT 0.492 639.600 128.532 639.696 ;
      RECT 0.492 642.000 128.532 642.096 ;
      RECT 0.492 644.400 128.532 644.496 ;
      RECT 0.492 646.800 128.532 646.896 ;
      RECT 0.492 649.200 128.532 649.296 ;
      RECT 0.492 651.600 128.532 651.696 ;
      RECT 0.492 654.000 128.532 654.096 ;
      RECT 0.492 656.400 128.532 656.496 ;
      RECT 0.492 658.800 128.532 658.896 ;
      RECT 0.492 661.200 128.532 661.296 ;
      RECT 0.492 663.600 128.532 663.696 ;
      RECT 0.492 666.000 128.532 666.096 ;
      RECT 0.492 668.400 128.532 668.496 ;
      RECT 0.492 670.800 128.532 670.896 ;
      RECT 0.492 673.200 128.532 673.296 ;
      RECT 0.492 675.600 128.532 675.696 ;
      RECT 0.492 678.000 128.532 678.096 ;
      RECT 0.492 680.400 128.532 680.496 ;
      RECT 0.492 682.800 128.532 682.896 ;
      RECT 0.492 685.200 128.532 685.296 ;
      RECT 0.492 687.600 128.532 687.696 ;
      RECT 0.492 690.000 128.532 690.096 ;
      RECT 0.492 692.400 128.532 692.496 ;
      RECT 0.492 694.800 128.532 694.896 ;
      RECT 0.492 697.200 128.532 697.296 ;
      RECT 0.492 699.600 128.532 699.696 ;
      RECT 0.492 702.000 128.532 702.096 ;
      RECT 0.492 704.400 128.532 704.496 ;
      RECT 0.492 706.800 128.532 706.896 ;
      RECT 0.492 709.200 128.532 709.296 ;
      RECT 0.492 711.600 128.532 711.696 ;
      RECT 0.492 714.000 128.532 714.096 ;
      RECT 0.492 716.400 128.532 716.496 ;
      RECT 0.492 718.800 128.532 718.896 ;
      RECT 0.492 721.200 128.532 721.296 ;
      RECT 0.492 723.600 128.532 723.696 ;
      RECT 0.492 726.000 128.532 726.096 ;
      RECT 0.492 728.400 128.532 728.496 ;
      RECT 0.492 730.800 128.532 730.896 ;
      RECT 0.492 733.200 128.532 733.296 ;
      RECT 0.492 735.600 128.532 735.696 ;
      RECT 0.492 738.000 128.532 738.096 ;
      RECT 0.492 740.400 128.532 740.496 ;
      RECT 0.492 742.800 128.532 742.896 ;
      RECT 0.492 745.200 128.532 745.296 ;
      RECT 0.492 747.600 128.532 747.696 ;
      RECT 0.492 750.000 128.532 750.096 ;
      RECT 0.492 752.400 128.532 752.496 ;
      RECT 0.492 754.800 128.532 754.896 ;
      RECT 0.492 757.200 128.532 757.296 ;
      RECT 0.492 759.600 128.532 759.696 ;
      RECT 0.492 762.000 128.532 762.096 ;
      RECT 0.492 764.400 128.532 764.496 ;
      RECT 0.492 766.800 128.532 766.896 ;
      RECT 0.492 769.200 128.532 769.296 ;
      RECT 0.492 771.600 128.532 771.696 ;
      RECT 0.492 774.000 128.532 774.096 ;
      RECT 0.492 776.400 128.532 776.496 ;
      RECT 0.492 778.800 128.532 778.896 ;
      RECT 0.492 781.200 128.532 781.296 ;
      RECT 0.492 783.600 128.532 783.696 ;
      RECT 0.492 786.000 128.532 786.096 ;
      RECT 0.492 788.400 128.532 788.496 ;
      RECT 0.492 790.800 128.532 790.896 ;
      RECT 0.492 793.200 128.532 793.296 ;
      RECT 0.492 795.600 128.532 795.696 ;
      RECT 0.492 798.000 128.532 798.096 ;
      RECT 0.492 800.400 128.532 800.496 ;
      RECT 0.492 802.800 128.532 802.896 ;
      RECT 0.492 805.200 128.532 805.296 ;
      RECT 0.492 807.600 128.532 807.696 ;
      RECT 0.492 810.000 128.532 810.096 ;
      RECT 0.492 812.400 128.532 812.496 ;
      RECT 0.492 814.800 128.532 814.896 ;
      RECT 0.492 817.200 128.532 817.296 ;
      RECT 0.492 819.600 128.532 819.696 ;
      RECT 0.492 822.000 128.532 822.096 ;
      RECT 0.492 824.400 128.532 824.496 ;
      RECT 0.492 826.800 128.532 826.896 ;
      RECT 0.492 829.200 128.532 829.296 ;
      RECT 0.492 831.600 128.532 831.696 ;
      RECT 0.492 834.000 128.532 834.096 ;
      RECT 0.492 836.400 128.532 836.496 ;
      RECT 0.492 838.800 128.532 838.896 ;
      RECT 0.492 841.200 128.532 841.296 ;
      RECT 0.492 843.600 128.532 843.696 ;
      RECT 0.492 846.000 128.532 846.096 ;
      RECT 0.492 848.400 128.532 848.496 ;
      RECT 0.492 850.800 128.532 850.896 ;
      RECT 0.492 853.200 128.532 853.296 ;
      RECT 0.492 855.600 128.532 855.696 ;
      RECT 0.492 858.000 128.532 858.096 ;
      RECT 0.492 860.400 128.532 860.496 ;
      RECT 0.492 862.800 128.532 862.896 ;
      RECT 0.492 865.200 128.532 865.296 ;
      RECT 0.492 867.600 128.532 867.696 ;
      RECT 0.492 870.000 128.532 870.096 ;
      RECT 0.492 872.400 128.532 872.496 ;
      RECT 0.492 874.800 128.532 874.896 ;
      RECT 0.492 877.200 128.532 877.296 ;
      RECT 0.492 879.600 128.532 879.696 ;
      RECT 0.492 882.000 128.532 882.096 ;
      RECT 0.492 884.400 128.532 884.496 ;
      RECT 0.492 886.800 128.532 886.896 ;
      RECT 0.492 889.200 128.532 889.296 ;
      RECT 0.492 891.600 128.532 891.696 ;
      RECT 0.492 894.000 128.532 894.096 ;
      RECT 0.492 896.400 128.532 896.496 ;
      RECT 0.492 898.800 128.532 898.896 ;
      RECT 0.492 901.200 128.532 901.296 ;
      RECT 0.492 903.600 128.532 903.696 ;
      RECT 0.492 906.000 128.532 906.096 ;
      RECT 0.492 908.400 128.532 908.496 ;
      RECT 0.492 910.800 128.532 910.896 ;
      RECT 0.492 913.200 128.532 913.296 ;
      RECT 0.492 915.600 128.532 915.696 ;
      RECT 0.492 918.000 128.532 918.096 ;
      RECT 0.492 920.400 128.532 920.496 ;
      RECT 0.492 922.800 128.532 922.896 ;
      RECT 0.492 925.200 128.532 925.296 ;
      RECT 0.492 927.600 128.532 927.696 ;
      RECT 0.492 930.000 128.532 930.096 ;
      RECT 0.492 932.400 128.532 932.496 ;
      RECT 0.492 934.800 128.532 934.896 ;
      RECT 0.492 937.200 128.532 937.296 ;
      RECT 0.492 939.600 128.532 939.696 ;
      RECT 0.492 942.000 128.532 942.096 ;
      RECT 0.492 944.400 128.532 944.496 ;
      RECT 0.492 946.800 128.532 946.896 ;
      RECT 0.492 949.200 128.532 949.296 ;
      RECT 0.492 951.600 128.532 951.696 ;
      RECT 0.492 954.000 128.532 954.096 ;
      RECT 0.492 956.400 128.532 956.496 ;
      RECT 0.492 958.800 128.532 958.896 ;
      RECT 0.492 961.200 128.532 961.296 ;
      RECT 0.492 963.600 128.532 963.696 ;
      RECT 0.492 966.000 128.532 966.096 ;
      RECT 0.492 968.400 128.532 968.496 ;
      RECT 0.492 970.800 128.532 970.896 ;
      RECT 0.492 973.200 128.532 973.296 ;
      RECT 0.492 975.600 128.532 975.696 ;
      RECT 0.492 978.000 128.532 978.096 ;
      RECT 0.492 980.400 128.532 980.496 ;
      RECT 0.492 982.800 128.532 982.896 ;
      RECT 0.492 985.200 128.532 985.296 ;
      RECT 0.492 987.600 128.532 987.696 ;
      RECT 0.492 990.000 128.532 990.096 ;
      RECT 0.492 992.400 128.532 992.496 ;
      RECT 0.492 994.800 128.532 994.896 ;
      RECT 0.492 997.200 128.532 997.296 ;
      RECT 0.492 999.600 128.532 999.696 ;
      RECT 0.492 1002.000 128.532 1002.096 ;
      RECT 0.492 1004.400 128.532 1004.496 ;
      RECT 0.492 1006.800 128.532 1006.896 ;
      RECT 0.492 1009.200 128.532 1009.296 ;
      RECT 0.492 1011.600 128.532 1011.696 ;
      RECT 0.492 1014.000 128.532 1014.096 ;
      RECT 0.492 1016.400 128.532 1016.496 ;
      RECT 0.492 1018.800 128.532 1018.896 ;
      RECT 0.492 1021.200 128.532 1021.296 ;
      RECT 0.492 1023.600 128.532 1023.696 ;
      RECT 0.492 1026.000 128.532 1026.096 ;
      RECT 0.492 1028.400 128.532 1028.496 ;
      RECT 0.492 1030.800 128.532 1030.896 ;
      RECT 0.492 1033.200 128.532 1033.296 ;
      RECT 0.492 1035.600 128.532 1035.696 ;
      RECT 0.492 1038.000 128.532 1038.096 ;
      RECT 0.492 1040.400 128.532 1040.496 ;
      RECT 0.492 1042.800 128.532 1042.896 ;
      RECT 0.492 1045.200 128.532 1045.296 ;
      RECT 0.492 1047.600 128.532 1047.696 ;
      RECT 0.492 1050.000 128.532 1050.096 ;
      RECT 0.492 1052.400 128.532 1052.496 ;
      RECT 0.492 1054.800 128.532 1054.896 ;
      RECT 0.492 1057.200 128.532 1057.296 ;
      RECT 0.492 1059.600 128.532 1059.696 ;
      RECT 0.492 1062.000 128.532 1062.096 ;
      RECT 0.492 1064.400 128.532 1064.496 ;
      RECT 0.492 1066.800 128.532 1066.896 ;
      RECT 0.492 1069.200 128.532 1069.296 ;
      RECT 0.492 1071.600 128.532 1071.696 ;
      RECT 0.492 1074.000 128.532 1074.096 ;
      RECT 0.492 1076.400 128.532 1076.496 ;
      RECT 0.492 1078.800 128.532 1078.896 ;
      RECT 0.492 1081.200 128.532 1081.296 ;
      RECT 0.492 1083.600 128.532 1083.696 ;
      RECT 0.492 1086.000 128.532 1086.096 ;
      RECT 0.492 1088.400 128.532 1088.496 ;
      RECT 0.492 1090.800 128.532 1090.896 ;
      RECT 0.492 1093.200 128.532 1093.296 ;
      RECT 0.492 1095.600 128.532 1095.696 ;
      RECT 0.492 1098.000 128.532 1098.096 ;
      RECT 0.492 1100.400 128.532 1100.496 ;
      RECT 0.492 1102.800 128.532 1102.896 ;
      RECT 0.492 1105.200 128.532 1105.296 ;
      RECT 0.492 1107.600 128.532 1107.696 ;
      RECT 0.492 1110.000 128.532 1110.096 ;
      RECT 0.492 1112.400 128.532 1112.496 ;
      RECT 0.492 1114.800 128.532 1114.896 ;
      RECT 0.492 1117.200 128.532 1117.296 ;
      RECT 0.492 1119.600 128.532 1119.696 ;
      RECT 0.492 1122.000 128.532 1122.096 ;
      RECT 0.492 1124.400 128.532 1124.496 ;
      RECT 0.492 1126.800 128.532 1126.896 ;
      RECT 0.492 1129.200 128.532 1129.296 ;
      RECT 0.492 1131.600 128.532 1131.696 ;
      RECT 0.492 1134.000 128.532 1134.096 ;
      RECT 0.492 1136.400 128.532 1136.496 ;
      RECT 0.492 1138.800 128.532 1138.896 ;
      RECT 0.492 1141.200 128.532 1141.296 ;
      RECT 0.492 1143.600 128.532 1143.696 ;
      RECT 0.492 1146.000 128.532 1146.096 ;
      RECT 0.492 1148.400 128.532 1148.496 ;
      RECT 0.492 1150.800 128.532 1150.896 ;
      RECT 0.492 1153.200 128.532 1153.296 ;
      RECT 0.492 1155.600 128.532 1155.696 ;
      RECT 0.492 1158.000 128.532 1158.096 ;
      RECT 0.492 1160.400 128.532 1160.496 ;
      RECT 0.492 1162.800 128.532 1162.896 ;
      RECT 0.492 1165.200 128.532 1165.296 ;
      RECT 0.492 1167.600 128.532 1167.696 ;
      RECT 0.492 1170.000 128.532 1170.096 ;
      RECT 0.492 1172.400 128.532 1172.496 ;
      RECT 0.492 1174.800 128.532 1174.896 ;
      RECT 0.492 1177.200 128.532 1177.296 ;
      RECT 0.492 1179.600 128.532 1179.696 ;
      RECT 0.492 1182.000 128.532 1182.096 ;
      RECT 0.492 1184.400 128.532 1184.496 ;
      RECT 0.492 1186.800 128.532 1186.896 ;
      RECT 0.492 1189.200 128.532 1189.296 ;
      RECT 0.492 1191.600 128.532 1191.696 ;
      RECT 0.492 1194.000 128.532 1194.096 ;
      RECT 0.492 1196.400 128.532 1196.496 ;
      RECT 0.492 1198.800 128.532 1198.896 ;
      RECT 0.492 1201.200 128.532 1201.296 ;
      RECT 0.492 1203.600 128.532 1203.696 ;
      RECT 0.492 1206.000 128.532 1206.096 ;
      RECT 0.492 1208.400 128.532 1208.496 ;
      RECT 0.492 1210.800 128.532 1210.896 ;
      RECT 0.492 1213.200 128.532 1213.296 ;
      RECT 0.492 1215.600 128.532 1215.696 ;
      RECT 0.492 1218.000 128.532 1218.096 ;
      RECT 0.492 1220.400 128.532 1220.496 ;
      RECT 0.492 1222.800 128.532 1222.896 ;
      RECT 0.492 1225.200 128.532 1225.296 ;
      RECT 0.492 1227.600 128.532 1227.696 ;
      RECT 0.492 1230.000 128.532 1230.096 ;
      RECT 0.492 1232.400 128.532 1232.496 ;
      RECT 0.492 1234.800 128.532 1234.896 ;
      RECT 0.492 1237.200 128.532 1237.296 ;
      RECT 0.492 1239.600 128.532 1239.696 ;
      RECT 0.492 1242.000 128.532 1242.096 ;
      RECT 0.492 1244.400 128.532 1244.496 ;
      RECT 0.492 1246.800 128.532 1246.896 ;
      RECT 0.492 1249.200 128.532 1249.296 ;
      RECT 0.492 1251.600 128.532 1251.696 ;
      RECT 0.492 1254.000 128.532 1254.096 ;
      RECT 0.492 1256.400 128.532 1256.496 ;
      RECT 0.492 1258.800 128.532 1258.896 ;
      RECT 0.492 1261.200 128.532 1261.296 ;
      RECT 0.492 1263.600 128.532 1263.696 ;
      RECT 0.492 1266.000 128.532 1266.096 ;
      RECT 0.492 1268.400 128.532 1268.496 ;
      RECT 0.492 1270.800 128.532 1270.896 ;
      RECT 0.492 1273.200 128.532 1273.296 ;
      RECT 0.492 1275.600 128.532 1275.696 ;
      RECT 0.492 1278.000 128.532 1278.096 ;
      RECT 0.492 1280.400 128.532 1280.496 ;
      RECT 0.492 1282.800 128.532 1282.896 ;
      RECT 0.492 1285.200 128.532 1285.296 ;
      RECT 0.492 1287.600 128.532 1287.696 ;
      RECT 0.492 1290.000 128.532 1290.096 ;
      RECT 0.492 1292.400 128.532 1292.496 ;
      RECT 0.492 1294.800 128.532 1294.896 ;
      RECT 0.492 1297.200 128.532 1297.296 ;
      RECT 0.492 1299.600 128.532 1299.696 ;
      RECT 0.492 1302.000 128.532 1302.096 ;
      RECT 0.492 1304.400 128.532 1304.496 ;
      RECT 0.492 1306.800 128.532 1306.896 ;
      RECT 0.492 1309.200 128.532 1309.296 ;
      RECT 0.492 1311.600 128.532 1311.696 ;
      RECT 0.492 1314.000 128.532 1314.096 ;
      RECT 0.492 1316.400 128.532 1316.496 ;
      RECT 0.492 1318.800 128.532 1318.896 ;
      RECT 0.492 1321.200 128.532 1321.296 ;
      RECT 0.492 1323.600 128.532 1323.696 ;
      RECT 0.492 1326.000 128.532 1326.096 ;
      RECT 0.492 1328.400 128.532 1328.496 ;
      RECT 0.492 1330.800 128.532 1330.896 ;
      RECT 0.492 1333.200 128.532 1333.296 ;
      RECT 0.492 1335.600 128.532 1335.696 ;
      RECT 0.492 1338.000 128.532 1338.096 ;
      RECT 0.492 1340.400 128.532 1340.496 ;
      RECT 0.492 1342.800 128.532 1342.896 ;
      RECT 0.492 1345.200 128.532 1345.296 ;
      RECT 0.492 1347.600 128.532 1347.696 ;
      RECT 0.492 1350.000 128.532 1350.096 ;
      RECT 0.492 1352.400 128.532 1352.496 ;
      RECT 0.492 1354.800 128.532 1354.896 ;
      RECT 0.492 1357.200 128.532 1357.296 ;
      RECT 0.492 1359.600 128.532 1359.696 ;
      RECT 0.492 1362.000 128.532 1362.096 ;
      RECT 0.492 1364.400 128.532 1364.496 ;
      RECT 0.492 1366.800 128.532 1366.896 ;
      RECT 0.492 1369.200 128.532 1369.296 ;
      RECT 0.492 1371.600 128.532 1371.696 ;
      RECT 0.492 1374.000 128.532 1374.096 ;
      RECT 0.492 1376.400 128.532 1376.496 ;
      RECT 0.492 1378.800 128.532 1378.896 ;
      RECT 0.492 1381.200 128.532 1381.296 ;
      RECT 0.492 1383.600 128.532 1383.696 ;
      RECT 0.492 1386.000 128.532 1386.096 ;
      RECT 0.492 1388.400 128.532 1388.496 ;
      RECT 0.492 1390.800 128.532 1390.896 ;
      RECT 0.492 1393.200 128.532 1393.296 ;
      RECT 0.492 1395.600 128.532 1395.696 ;
      RECT 0.492 1398.000 128.532 1398.096 ;
      RECT 0.492 1400.400 128.532 1400.496 ;
      RECT 0.492 1402.800 128.532 1402.896 ;
      RECT 0.492 1405.200 128.532 1405.296 ;
      RECT 0.492 1407.600 128.532 1407.696 ;
      RECT 0.492 1410.000 128.532 1410.096 ;
      RECT 0.492 1412.400 128.532 1412.496 ;
      RECT 0.492 1414.800 128.532 1414.896 ;
      RECT 0.492 1417.200 128.532 1417.296 ;
      RECT 0.492 1419.600 128.532 1419.696 ;
      RECT 0.492 1422.000 128.532 1422.096 ;
      RECT 0.492 1424.400 128.532 1424.496 ;
      RECT 0.492 1426.800 128.532 1426.896 ;
      RECT 0.492 1429.200 128.532 1429.296 ;
      RECT 0.492 1431.600 128.532 1431.696 ;
      RECT 0.492 1434.000 128.532 1434.096 ;
      RECT 0.492 1436.400 128.532 1436.496 ;
      RECT 0.492 1438.800 128.532 1438.896 ;
      RECT 0.492 1441.200 128.532 1441.296 ;
      RECT 0.492 1443.600 128.532 1443.696 ;
      RECT 0.492 1446.000 128.532 1446.096 ;
      RECT 0.492 1448.400 128.532 1448.496 ;
      RECT 0.492 1450.800 128.532 1450.896 ;
      RECT 0.492 1453.200 128.532 1453.296 ;
      RECT 0.492 1455.600 128.532 1455.696 ;
      RECT 0.492 1458.000 128.532 1458.096 ;
      RECT 0.492 1460.400 128.532 1460.496 ;
      RECT 0.492 1462.800 128.532 1462.896 ;
      RECT 0.492 1465.200 128.532 1465.296 ;
      RECT 0.492 1467.600 128.532 1467.696 ;
      RECT 0.492 1470.000 128.532 1470.096 ;
      RECT 0.492 1472.400 128.532 1472.496 ;
      RECT 0.492 1474.800 128.532 1474.896 ;
      RECT 0.492 1477.200 128.532 1477.296 ;
      RECT 0.492 1479.600 128.532 1479.696 ;
      RECT 0.492 1482.000 128.532 1482.096 ;
      RECT 0.492 1484.400 128.532 1484.496 ;
      RECT 0.492 1486.800 128.532 1486.896 ;
      RECT 0.492 1489.200 128.532 1489.296 ;
      RECT 0.492 1491.600 128.532 1491.696 ;
      RECT 0.492 1494.000 128.532 1494.096 ;
      RECT 0.492 1496.400 128.532 1496.496 ;
      RECT 0.492 1498.800 128.532 1498.896 ;
      RECT 0.492 1501.200 128.532 1501.296 ;
      RECT 0.492 1503.600 128.532 1503.696 ;
      RECT 0.492 1506.000 128.532 1506.096 ;
      RECT 0.492 1508.400 128.532 1508.496 ;
      RECT 0.492 1510.800 128.532 1510.896 ;
      RECT 0.492 1513.200 128.532 1513.296 ;
      RECT 0.492 1515.600 128.532 1515.696 ;
      RECT 0.492 1518.000 128.532 1518.096 ;
      RECT 0.492 1520.400 128.532 1520.496 ;
      RECT 0.492 1522.800 128.532 1522.896 ;
      RECT 0.492 1525.200 128.532 1525.296 ;
      RECT 0.492 1527.600 128.532 1527.696 ;
      RECT 0.492 1530.000 128.532 1530.096 ;
      RECT 0.492 1532.400 128.532 1532.496 ;
      RECT 0.492 1534.800 128.532 1534.896 ;
      RECT 0.492 1537.200 128.532 1537.296 ;
      RECT 0.492 1539.600 128.532 1539.696 ;
      RECT 0.492 1542.000 128.532 1542.096 ;
      RECT 0.492 1544.400 128.532 1544.496 ;
      RECT 0.492 1546.800 128.532 1546.896 ;
      RECT 0.492 1549.200 128.532 1549.296 ;
      RECT 0.492 1551.600 128.532 1551.696 ;
      RECT 0.492 1554.000 128.532 1554.096 ;
      RECT 0.492 1556.400 128.532 1556.496 ;
      RECT 0.492 1558.800 128.532 1558.896 ;
      RECT 0.492 1561.200 128.532 1561.296 ;
      RECT 0.492 1563.600 128.532 1563.696 ;
      RECT 0.492 1566.000 128.532 1566.096 ;
      RECT 0.492 1568.400 128.532 1568.496 ;
      RECT 0.492 1570.800 128.532 1570.896 ;
      RECT 0.492 1573.200 128.532 1573.296 ;
      RECT 0.492 1575.600 128.532 1575.696 ;
      RECT 0.492 1578.000 128.532 1578.096 ;
      RECT 0.492 1580.400 128.532 1580.496 ;
      RECT 0.492 1582.800 128.532 1582.896 ;
      RECT 0.492 1585.200 128.532 1585.296 ;
      RECT 0.492 1587.600 128.532 1587.696 ;
      RECT 0.492 1590.000 128.532 1590.096 ;
      RECT 0.492 1592.400 128.532 1592.496 ;
      RECT 0.492 1594.800 128.532 1594.896 ;
      RECT 0.492 1597.200 128.532 1597.296 ;
      RECT 0.492 1599.600 128.532 1599.696 ;
      RECT 0.492 1602.000 128.532 1602.096 ;
      RECT 0.492 1604.400 128.532 1604.496 ;
      RECT 0.492 1606.800 128.532 1606.896 ;
      RECT 0.492 1609.200 128.532 1609.296 ;
      RECT 0.492 1611.600 128.532 1611.696 ;
      RECT 0.492 1614.000 128.532 1614.096 ;
      RECT 0.492 1616.400 128.532 1616.496 ;
      RECT 0.492 1618.800 128.532 1618.896 ;
      RECT 0.492 1621.200 128.532 1621.296 ;
      RECT 0.492 1623.600 128.532 1623.696 ;
      RECT 0.492 1626.000 128.532 1626.096 ;
      RECT 0.492 1628.400 128.532 1628.496 ;
      RECT 0.492 1630.800 128.532 1630.896 ;
      RECT 0.492 1633.200 128.532 1633.296 ;
      RECT 0.492 1635.600 128.532 1635.696 ;
      RECT 0.492 1638.000 128.532 1638.096 ;
      RECT 0.492 1640.400 128.532 1640.496 ;
      RECT 0.492 1642.800 128.532 1642.896 ;
      RECT 0.492 1645.200 128.532 1645.296 ;
      RECT 0.492 1647.600 128.532 1647.696 ;
      RECT 0.492 1650.000 128.532 1650.096 ;
      RECT 0.492 1652.400 128.532 1652.496 ;
      RECT 0.492 1654.800 128.532 1654.896 ;
      RECT 0.492 1657.200 128.532 1657.296 ;
      RECT 0.492 1659.600 128.532 1659.696 ;
      RECT 0.492 1662.000 128.532 1662.096 ;
      RECT 0.492 1664.400 128.532 1664.496 ;
      RECT 0.492 1666.800 128.532 1666.896 ;
      RECT 0.492 1669.200 128.532 1669.296 ;
      RECT 0.492 1671.600 128.532 1671.696 ;
      RECT 0.492 1674.000 128.532 1674.096 ;
      RECT 0.492 1676.400 128.532 1676.496 ;
      RECT 0.492 1678.800 128.532 1678.896 ;
      RECT 0.492 1681.200 128.532 1681.296 ;
      RECT 0.492 1683.600 128.532 1683.696 ;
      RECT 0.492 1686.000 128.532 1686.096 ;
      RECT 0.492 1688.400 128.532 1688.496 ;
      RECT 0.492 1690.800 128.532 1690.896 ;
      RECT 0.492 1693.200 128.532 1693.296 ;
      RECT 0.492 1695.600 128.532 1695.696 ;
      RECT 0.492 1698.000 128.532 1698.096 ;
      RECT 0.492 1700.400 128.532 1700.496 ;
      RECT 0.492 1702.800 128.532 1702.896 ;
      RECT 0.492 1705.200 128.532 1705.296 ;
      RECT 0.492 1707.600 128.532 1707.696 ;
      RECT 0.492 1710.000 128.532 1710.096 ;
      RECT 0.492 1712.400 128.532 1712.496 ;
      RECT 0.492 1714.800 128.532 1714.896 ;
      RECT 0.492 1717.200 128.532 1717.296 ;
      RECT 0.492 1719.600 128.532 1719.696 ;
      RECT 0.492 1722.000 128.532 1722.096 ;
      RECT 0.492 1724.400 128.532 1724.496 ;
      RECT 0.492 1726.800 128.532 1726.896 ;
      RECT 0.492 1729.200 128.532 1729.296 ;
      RECT 0.492 1731.600 128.532 1731.696 ;
      RECT 0.492 1734.000 128.532 1734.096 ;
      RECT 0.492 1736.400 128.532 1736.496 ;
      RECT 0.492 1738.800 128.532 1738.896 ;
      RECT 0.492 1741.200 128.532 1741.296 ;
      RECT 0.492 1743.600 128.532 1743.696 ;
      RECT 0.492 1746.000 128.532 1746.096 ;
      RECT 0.492 1748.400 128.532 1748.496 ;
      RECT 0.492 1750.800 128.532 1750.896 ;
      RECT 0.492 1753.200 128.532 1753.296 ;
      RECT 0.492 1755.600 128.532 1755.696 ;
      RECT 0.492 1758.000 128.532 1758.096 ;
      RECT 0.492 1760.400 128.532 1760.496 ;
      RECT 0.492 1762.800 128.532 1762.896 ;
      RECT 0.492 1765.200 128.532 1765.296 ;
      RECT 0.492 1767.600 128.532 1767.696 ;
      RECT 0.492 1770.000 128.532 1770.096 ;
      RECT 0.492 1772.400 128.532 1772.496 ;
      RECT 0.492 1774.800 128.532 1774.896 ;
      RECT 0.492 1777.200 128.532 1777.296 ;
      RECT 0.492 1779.600 128.532 1779.696 ;
      RECT 0.492 1782.000 128.532 1782.096 ;
      RECT 0.492 1784.400 128.532 1784.496 ;
      RECT 0.492 1786.800 128.532 1786.896 ;
      RECT 0.492 1789.200 128.532 1789.296 ;
      RECT 0.492 1791.600 128.532 1791.696 ;
      RECT 0.492 1794.000 128.532 1794.096 ;
      RECT 0.492 1796.400 128.532 1796.496 ;
      RECT 0.492 1798.800 128.532 1798.896 ;
      RECT 0.492 1801.200 128.532 1801.296 ;
      RECT 0.492 1803.600 128.532 1803.696 ;
      RECT 0.492 1806.000 128.532 1806.096 ;
      RECT 0.492 1808.400 128.532 1808.496 ;
      RECT 0.492 1810.800 128.532 1810.896 ;
      RECT 0.492 1813.200 128.532 1813.296 ;
      RECT 0.492 1815.600 128.532 1815.696 ;
      RECT 0.492 1818.000 128.532 1818.096 ;
      RECT 0.492 1820.400 128.532 1820.496 ;
      RECT 0.492 1822.800 128.532 1822.896 ;
      RECT 0.492 1825.200 128.532 1825.296 ;
      RECT 0.492 1827.600 128.532 1827.696 ;
      RECT 0.492 1830.000 128.532 1830.096 ;
      RECT 0.492 1832.400 128.532 1832.496 ;
      RECT 0.492 1834.800 128.532 1834.896 ;
      RECT 0.492 1837.200 128.532 1837.296 ;
      RECT 0.492 1839.600 128.532 1839.696 ;
      RECT 0.492 1842.000 128.532 1842.096 ;
      RECT 0.492 1844.400 128.532 1844.496 ;
      RECT 0.492 1846.800 128.532 1846.896 ;
      RECT 0.492 1849.200 128.532 1849.296 ;
      RECT 0.492 1851.600 128.532 1851.696 ;
      RECT 0.492 1854.000 128.532 1854.096 ;
      RECT 0.492 1856.400 128.532 1856.496 ;
      RECT 0.492 1858.800 128.532 1858.896 ;
      RECT 0.492 1861.200 128.532 1861.296 ;
      RECT 0.492 1863.600 128.532 1863.696 ;
      RECT 0.492 1866.000 128.532 1866.096 ;
      RECT 0.492 1868.400 128.532 1868.496 ;
      RECT 0.492 1870.800 128.532 1870.896 ;
      RECT 0.492 1873.200 128.532 1873.296 ;
      RECT 0.492 1875.600 128.532 1875.696 ;
      RECT 0.492 1878.000 128.532 1878.096 ;
      RECT 0.492 1880.400 128.532 1880.496 ;
      RECT 0.492 1882.800 128.532 1882.896 ;
      RECT 0.492 1885.200 128.532 1885.296 ;
      RECT 0.492 1887.600 128.532 1887.696 ;
      RECT 0.492 1890.000 128.532 1890.096 ;
      RECT 0.492 1892.400 128.532 1892.496 ;
      RECT 0.492 1894.800 128.532 1894.896 ;
      RECT 0.492 1897.200 128.532 1897.296 ;
      RECT 0.492 1899.600 128.532 1899.696 ;
      RECT 0.492 1902.000 128.532 1902.096 ;
      RECT 0.492 1904.400 128.532 1904.496 ;
      RECT 0.492 1906.800 128.532 1906.896 ;
      RECT 0.492 1909.200 128.532 1909.296 ;
      RECT 0.492 1911.600 128.532 1911.696 ;
      RECT 0.492 1914.000 128.532 1914.096 ;
      RECT 0.492 1916.400 128.532 1916.496 ;
      RECT 0.492 1918.800 128.532 1918.896 ;
      RECT 0.492 1921.200 128.532 1921.296 ;
      RECT 0.492 1923.600 128.532 1923.696 ;
      RECT 0.492 1926.000 128.532 1926.096 ;
      RECT 0.492 1928.400 128.532 1928.496 ;
      RECT 0.492 1930.800 128.532 1930.896 ;
      RECT 0.492 1933.200 128.532 1933.296 ;
      RECT 0.492 1935.600 128.532 1935.696 ;
      RECT 0.492 1938.000 128.532 1938.096 ;
      RECT 0.492 1940.400 128.532 1940.496 ;
      RECT 0.492 1942.800 128.532 1942.896 ;
      RECT 0.492 1945.200 128.532 1945.296 ;
      RECT 0.492 1947.600 128.532 1947.696 ;
      RECT 0.492 1950.000 128.532 1950.096 ;
      RECT 0.492 1952.400 128.532 1952.496 ;
      RECT 0.492 1954.800 128.532 1954.896 ;
      RECT 0.492 1957.200 128.532 1957.296 ;
      RECT 0.492 1959.600 128.532 1959.696 ;
      RECT 0.492 1962.000 128.532 1962.096 ;
      RECT 0.492 1964.400 128.532 1964.496 ;
      RECT 0.492 1966.800 128.532 1966.896 ;
      RECT 0.492 1969.200 128.532 1969.296 ;
      RECT 0.492 1971.600 128.532 1971.696 ;
      RECT 0.492 1974.000 128.532 1974.096 ;
      RECT 0.492 1976.400 128.532 1976.496 ;
      RECT 0.492 1978.800 128.532 1978.896 ;
      RECT 0.492 1981.200 128.532 1981.296 ;
      RECT 0.492 1983.600 128.532 1983.696 ;
      RECT 0.492 1986.000 128.532 1986.096 ;
      RECT 0.492 1988.400 128.532 1988.496 ;
      RECT 0.492 1990.800 128.532 1990.896 ;
      RECT 0.492 1993.200 128.532 1993.296 ;
      RECT 0.492 1995.600 128.532 1995.696 ;
      RECT 0.492 1998.000 128.532 1998.096 ;
      RECT 0.492 2000.400 128.532 2000.496 ;
      RECT 0.492 2002.800 128.532 2002.896 ;
      RECT 0.492 2005.200 128.532 2005.296 ;
      RECT 0.492 2007.600 128.532 2007.696 ;
      RECT 0.492 2010.000 128.532 2010.096 ;
      RECT 0.492 2012.400 128.532 2012.496 ;
      RECT 0.492 2014.800 128.532 2014.896 ;
      RECT 0.492 2017.200 128.532 2017.296 ;
      RECT 0.492 2019.600 128.532 2019.696 ;
      RECT 0.492 2022.000 128.532 2022.096 ;
      RECT 0.492 2024.400 128.532 2024.496 ;
      RECT 0.492 2026.800 128.532 2026.896 ;
      RECT 0.492 2029.200 128.532 2029.296 ;
      RECT 0.492 2031.600 128.532 2031.696 ;
      RECT 0.492 2034.000 128.532 2034.096 ;
      RECT 0.492 2036.400 128.532 2036.496 ;
      RECT 0.492 2038.800 128.532 2038.896 ;
      RECT 0.492 2041.200 128.532 2041.296 ;
      RECT 0.492 2043.600 128.532 2043.696 ;
      RECT 0.492 2046.000 128.532 2046.096 ;
      RECT 0.492 2048.400 128.532 2048.496 ;
      RECT 0.492 2050.800 128.532 2050.896 ;
      RECT 0.492 2053.200 128.532 2053.296 ;
      RECT 0.492 2055.600 128.532 2055.696 ;
      RECT 0.492 2058.000 128.532 2058.096 ;
      RECT 0.492 2060.400 128.532 2060.496 ;
      RECT 0.492 2062.800 128.532 2062.896 ;
      RECT 0.492 2065.200 128.532 2065.296 ;
      RECT 0.492 2067.600 128.532 2067.696 ;
      RECT 0.492 2070.000 128.532 2070.096 ;
      RECT 0.492 2072.400 128.532 2072.496 ;
      RECT 0.492 2074.800 128.532 2074.896 ;
      RECT 0.492 2077.200 128.532 2077.296 ;
      RECT 0.492 2079.600 128.532 2079.696 ;
      RECT 0.492 2082.000 128.532 2082.096 ;
      RECT 0.492 2084.400 128.532 2084.496 ;
      RECT 0.492 2086.800 128.532 2086.896 ;
      RECT 0.492 2089.200 128.532 2089.296 ;
      RECT 0.492 2091.600 128.532 2091.696 ;
      RECT 0.492 2094.000 128.532 2094.096 ;
      RECT 0.492 2096.400 128.532 2096.496 ;
      RECT 0.492 2098.800 128.532 2098.896 ;
      RECT 0.492 2101.200 128.532 2101.296 ;
      RECT 0.492 2103.600 128.532 2103.696 ;
      RECT 0.492 2106.000 128.532 2106.096 ;
      RECT 0.492 2108.400 128.532 2108.496 ;
      RECT 0.492 2110.800 128.532 2110.896 ;
      RECT 0.492 2113.200 128.532 2113.296 ;
      RECT 0.492 2115.600 128.532 2115.696 ;
      RECT 0.492 2118.000 128.532 2118.096 ;
      RECT 0.492 2120.400 128.532 2120.496 ;
      RECT 0.492 2122.800 128.532 2122.896 ;
      RECT 0.492 2125.200 128.532 2125.296 ;
      RECT 0.492 2127.600 128.532 2127.696 ;
      RECT 0.492 2130.000 128.532 2130.096 ;
      RECT 0.492 2132.400 128.532 2132.496 ;
      RECT 0.492 2134.800 128.532 2134.896 ;
      RECT 0.492 2137.200 128.532 2137.296 ;
      RECT 0.492 2139.600 128.532 2139.696 ;
      RECT 0.492 2142.000 128.532 2142.096 ;
      RECT 0.492 2144.400 128.532 2144.496 ;
      RECT 0.492 2146.800 128.532 2146.896 ;
      RECT 0.492 2149.200 128.532 2149.296 ;
      RECT 0.492 2151.600 128.532 2151.696 ;
      RECT 0.492 2154.000 128.532 2154.096 ;
      RECT 0.492 2156.400 128.532 2156.496 ;
      RECT 0.492 2158.800 128.532 2158.896 ;
      RECT 0.492 2161.200 128.532 2161.296 ;
      RECT 0.492 2163.600 128.532 2163.696 ;
      RECT 0.492 2166.000 128.532 2166.096 ;
      RECT 0.492 2168.400 128.532 2168.496 ;
      RECT 0.492 2170.800 128.532 2170.896 ;
      RECT 0.492 2173.200 128.532 2173.296 ;
      RECT 0.492 2175.600 128.532 2175.696 ;
      RECT 0.492 2178.000 128.532 2178.096 ;
      RECT 0.492 2180.400 128.532 2180.496 ;
      RECT 0.492 2182.800 128.532 2182.896 ;
      RECT 0.492 2185.200 128.532 2185.296 ;
      RECT 0.492 2187.600 128.532 2187.696 ;
      RECT 0.492 2190.000 128.532 2190.096 ;
      RECT 0.492 2192.400 128.532 2192.496 ;
      RECT 0.492 2194.800 128.532 2194.896 ;
      RECT 0.492 2197.200 128.532 2197.296 ;
      RECT 0.492 2199.600 128.532 2199.696 ;
      RECT 0.492 2202.000 128.532 2202.096 ;
      RECT 0.492 2204.400 128.532 2204.496 ;
      RECT 0.492 2206.800 128.532 2206.896 ;
      RECT 0.492 2209.200 128.532 2209.296 ;
      RECT 0.492 2211.600 128.532 2211.696 ;
      RECT 0.492 2214.000 128.532 2214.096 ;
      RECT 0.492 2216.400 128.532 2216.496 ;
      RECT 0.492 2218.800 128.532 2218.896 ;
      RECT 0.492 2221.200 128.532 2221.296 ;
      RECT 0.492 2223.600 128.532 2223.696 ;
      RECT 0.492 2226.000 128.532 2226.096 ;
      RECT 0.492 2228.400 128.532 2228.496 ;
      RECT 0.492 2230.800 128.532 2230.896 ;
      RECT 0.492 2233.200 128.532 2233.296 ;
      RECT 0.492 2235.600 128.532 2235.696 ;
      RECT 0.492 2238.000 128.532 2238.096 ;
      RECT 0.492 2240.400 128.532 2240.496 ;
      RECT 0.492 2242.800 128.532 2242.896 ;
      RECT 0.492 2245.200 128.532 2245.296 ;
      RECT 0.492 2247.600 128.532 2247.696 ;
    END
  END VSS
  PIN VDD
    DIRECTION INOUT ;
    USE POWER ;
    PORT
      LAYER M4 ;
      RECT 0.492 2.400 128.532 2.496 ;
      RECT 0.492 4.800 128.532 4.896 ;
      RECT 0.492 7.200 128.532 7.296 ;
      RECT 0.492 9.600 128.532 9.696 ;
      RECT 0.492 12.000 128.532 12.096 ;
      RECT 0.492 14.400 128.532 14.496 ;
      RECT 0.492 16.800 128.532 16.896 ;
      RECT 0.492 19.200 128.532 19.296 ;
      RECT 0.492 21.600 128.532 21.696 ;
      RECT 0.492 24.000 128.532 24.096 ;
      RECT 0.492 26.400 128.532 26.496 ;
      RECT 0.492 28.800 128.532 28.896 ;
      RECT 0.492 31.200 128.532 31.296 ;
      RECT 0.492 33.600 128.532 33.696 ;
      RECT 0.492 36.000 128.532 36.096 ;
      RECT 0.492 38.400 128.532 38.496 ;
      RECT 0.492 40.800 128.532 40.896 ;
      RECT 0.492 43.200 128.532 43.296 ;
      RECT 0.492 45.600 128.532 45.696 ;
      RECT 0.492 48.000 128.532 48.096 ;
      RECT 0.492 50.400 128.532 50.496 ;
      RECT 0.492 52.800 128.532 52.896 ;
      RECT 0.492 55.200 128.532 55.296 ;
      RECT 0.492 57.600 128.532 57.696 ;
      RECT 0.492 60.000 128.532 60.096 ;
      RECT 0.492 62.400 128.532 62.496 ;
      RECT 0.492 64.800 128.532 64.896 ;
      RECT 0.492 67.200 128.532 67.296 ;
      RECT 0.492 69.600 128.532 69.696 ;
      RECT 0.492 72.000 128.532 72.096 ;
      RECT 0.492 74.400 128.532 74.496 ;
      RECT 0.492 76.800 128.532 76.896 ;
      RECT 0.492 79.200 128.532 79.296 ;
      RECT 0.492 81.600 128.532 81.696 ;
      RECT 0.492 84.000 128.532 84.096 ;
      RECT 0.492 86.400 128.532 86.496 ;
      RECT 0.492 88.800 128.532 88.896 ;
      RECT 0.492 91.200 128.532 91.296 ;
      RECT 0.492 93.600 128.532 93.696 ;
      RECT 0.492 96.000 128.532 96.096 ;
      RECT 0.492 98.400 128.532 98.496 ;
      RECT 0.492 100.800 128.532 100.896 ;
      RECT 0.492 103.200 128.532 103.296 ;
      RECT 0.492 105.600 128.532 105.696 ;
      RECT 0.492 108.000 128.532 108.096 ;
      RECT 0.492 110.400 128.532 110.496 ;
      RECT 0.492 112.800 128.532 112.896 ;
      RECT 0.492 115.200 128.532 115.296 ;
      RECT 0.492 117.600 128.532 117.696 ;
      RECT 0.492 120.000 128.532 120.096 ;
      RECT 0.492 122.400 128.532 122.496 ;
      RECT 0.492 124.800 128.532 124.896 ;
      RECT 0.492 127.200 128.532 127.296 ;
      RECT 0.492 129.600 128.532 129.696 ;
      RECT 0.492 132.000 128.532 132.096 ;
      RECT 0.492 134.400 128.532 134.496 ;
      RECT 0.492 136.800 128.532 136.896 ;
      RECT 0.492 139.200 128.532 139.296 ;
      RECT 0.492 141.600 128.532 141.696 ;
      RECT 0.492 144.000 128.532 144.096 ;
      RECT 0.492 146.400 128.532 146.496 ;
      RECT 0.492 148.800 128.532 148.896 ;
      RECT 0.492 151.200 128.532 151.296 ;
      RECT 0.492 153.600 128.532 153.696 ;
      RECT 0.492 156.000 128.532 156.096 ;
      RECT 0.492 158.400 128.532 158.496 ;
      RECT 0.492 160.800 128.532 160.896 ;
      RECT 0.492 163.200 128.532 163.296 ;
      RECT 0.492 165.600 128.532 165.696 ;
      RECT 0.492 168.000 128.532 168.096 ;
      RECT 0.492 170.400 128.532 170.496 ;
      RECT 0.492 172.800 128.532 172.896 ;
      RECT 0.492 175.200 128.532 175.296 ;
      RECT 0.492 177.600 128.532 177.696 ;
      RECT 0.492 180.000 128.532 180.096 ;
      RECT 0.492 182.400 128.532 182.496 ;
      RECT 0.492 184.800 128.532 184.896 ;
      RECT 0.492 187.200 128.532 187.296 ;
      RECT 0.492 189.600 128.532 189.696 ;
      RECT 0.492 192.000 128.532 192.096 ;
      RECT 0.492 194.400 128.532 194.496 ;
      RECT 0.492 196.800 128.532 196.896 ;
      RECT 0.492 199.200 128.532 199.296 ;
      RECT 0.492 201.600 128.532 201.696 ;
      RECT 0.492 204.000 128.532 204.096 ;
      RECT 0.492 206.400 128.532 206.496 ;
      RECT 0.492 208.800 128.532 208.896 ;
      RECT 0.492 211.200 128.532 211.296 ;
      RECT 0.492 213.600 128.532 213.696 ;
      RECT 0.492 216.000 128.532 216.096 ;
      RECT 0.492 218.400 128.532 218.496 ;
      RECT 0.492 220.800 128.532 220.896 ;
      RECT 0.492 223.200 128.532 223.296 ;
      RECT 0.492 225.600 128.532 225.696 ;
      RECT 0.492 228.000 128.532 228.096 ;
      RECT 0.492 230.400 128.532 230.496 ;
      RECT 0.492 232.800 128.532 232.896 ;
      RECT 0.492 235.200 128.532 235.296 ;
      RECT 0.492 237.600 128.532 237.696 ;
      RECT 0.492 240.000 128.532 240.096 ;
      RECT 0.492 242.400 128.532 242.496 ;
      RECT 0.492 244.800 128.532 244.896 ;
      RECT 0.492 247.200 128.532 247.296 ;
      RECT 0.492 249.600 128.532 249.696 ;
      RECT 0.492 252.000 128.532 252.096 ;
      RECT 0.492 254.400 128.532 254.496 ;
      RECT 0.492 256.800 128.532 256.896 ;
      RECT 0.492 259.200 128.532 259.296 ;
      RECT 0.492 261.600 128.532 261.696 ;
      RECT 0.492 264.000 128.532 264.096 ;
      RECT 0.492 266.400 128.532 266.496 ;
      RECT 0.492 268.800 128.532 268.896 ;
      RECT 0.492 271.200 128.532 271.296 ;
      RECT 0.492 273.600 128.532 273.696 ;
      RECT 0.492 276.000 128.532 276.096 ;
      RECT 0.492 278.400 128.532 278.496 ;
      RECT 0.492 280.800 128.532 280.896 ;
      RECT 0.492 283.200 128.532 283.296 ;
      RECT 0.492 285.600 128.532 285.696 ;
      RECT 0.492 288.000 128.532 288.096 ;
      RECT 0.492 290.400 128.532 290.496 ;
      RECT 0.492 292.800 128.532 292.896 ;
      RECT 0.492 295.200 128.532 295.296 ;
      RECT 0.492 297.600 128.532 297.696 ;
      RECT 0.492 300.000 128.532 300.096 ;
      RECT 0.492 302.400 128.532 302.496 ;
      RECT 0.492 304.800 128.532 304.896 ;
      RECT 0.492 307.200 128.532 307.296 ;
      RECT 0.492 309.600 128.532 309.696 ;
      RECT 0.492 312.000 128.532 312.096 ;
      RECT 0.492 314.400 128.532 314.496 ;
      RECT 0.492 316.800 128.532 316.896 ;
      RECT 0.492 319.200 128.532 319.296 ;
      RECT 0.492 321.600 128.532 321.696 ;
      RECT 0.492 324.000 128.532 324.096 ;
      RECT 0.492 326.400 128.532 326.496 ;
      RECT 0.492 328.800 128.532 328.896 ;
      RECT 0.492 331.200 128.532 331.296 ;
      RECT 0.492 333.600 128.532 333.696 ;
      RECT 0.492 336.000 128.532 336.096 ;
      RECT 0.492 338.400 128.532 338.496 ;
      RECT 0.492 340.800 128.532 340.896 ;
      RECT 0.492 343.200 128.532 343.296 ;
      RECT 0.492 345.600 128.532 345.696 ;
      RECT 0.492 348.000 128.532 348.096 ;
      RECT 0.492 350.400 128.532 350.496 ;
      RECT 0.492 352.800 128.532 352.896 ;
      RECT 0.492 355.200 128.532 355.296 ;
      RECT 0.492 357.600 128.532 357.696 ;
      RECT 0.492 360.000 128.532 360.096 ;
      RECT 0.492 362.400 128.532 362.496 ;
      RECT 0.492 364.800 128.532 364.896 ;
      RECT 0.492 367.200 128.532 367.296 ;
      RECT 0.492 369.600 128.532 369.696 ;
      RECT 0.492 372.000 128.532 372.096 ;
      RECT 0.492 374.400 128.532 374.496 ;
      RECT 0.492 376.800 128.532 376.896 ;
      RECT 0.492 379.200 128.532 379.296 ;
      RECT 0.492 381.600 128.532 381.696 ;
      RECT 0.492 384.000 128.532 384.096 ;
      RECT 0.492 386.400 128.532 386.496 ;
      RECT 0.492 388.800 128.532 388.896 ;
      RECT 0.492 391.200 128.532 391.296 ;
      RECT 0.492 393.600 128.532 393.696 ;
      RECT 0.492 396.000 128.532 396.096 ;
      RECT 0.492 398.400 128.532 398.496 ;
      RECT 0.492 400.800 128.532 400.896 ;
      RECT 0.492 403.200 128.532 403.296 ;
      RECT 0.492 405.600 128.532 405.696 ;
      RECT 0.492 408.000 128.532 408.096 ;
      RECT 0.492 410.400 128.532 410.496 ;
      RECT 0.492 412.800 128.532 412.896 ;
      RECT 0.492 415.200 128.532 415.296 ;
      RECT 0.492 417.600 128.532 417.696 ;
      RECT 0.492 420.000 128.532 420.096 ;
      RECT 0.492 422.400 128.532 422.496 ;
      RECT 0.492 424.800 128.532 424.896 ;
      RECT 0.492 427.200 128.532 427.296 ;
      RECT 0.492 429.600 128.532 429.696 ;
      RECT 0.492 432.000 128.532 432.096 ;
      RECT 0.492 434.400 128.532 434.496 ;
      RECT 0.492 436.800 128.532 436.896 ;
      RECT 0.492 439.200 128.532 439.296 ;
      RECT 0.492 441.600 128.532 441.696 ;
      RECT 0.492 444.000 128.532 444.096 ;
      RECT 0.492 446.400 128.532 446.496 ;
      RECT 0.492 448.800 128.532 448.896 ;
      RECT 0.492 451.200 128.532 451.296 ;
      RECT 0.492 453.600 128.532 453.696 ;
      RECT 0.492 456.000 128.532 456.096 ;
      RECT 0.492 458.400 128.532 458.496 ;
      RECT 0.492 460.800 128.532 460.896 ;
      RECT 0.492 463.200 128.532 463.296 ;
      RECT 0.492 465.600 128.532 465.696 ;
      RECT 0.492 468.000 128.532 468.096 ;
      RECT 0.492 470.400 128.532 470.496 ;
      RECT 0.492 472.800 128.532 472.896 ;
      RECT 0.492 475.200 128.532 475.296 ;
      RECT 0.492 477.600 128.532 477.696 ;
      RECT 0.492 480.000 128.532 480.096 ;
      RECT 0.492 482.400 128.532 482.496 ;
      RECT 0.492 484.800 128.532 484.896 ;
      RECT 0.492 487.200 128.532 487.296 ;
      RECT 0.492 489.600 128.532 489.696 ;
      RECT 0.492 492.000 128.532 492.096 ;
      RECT 0.492 494.400 128.532 494.496 ;
      RECT 0.492 496.800 128.532 496.896 ;
      RECT 0.492 499.200 128.532 499.296 ;
      RECT 0.492 501.600 128.532 501.696 ;
      RECT 0.492 504.000 128.532 504.096 ;
      RECT 0.492 506.400 128.532 506.496 ;
      RECT 0.492 508.800 128.532 508.896 ;
      RECT 0.492 511.200 128.532 511.296 ;
      RECT 0.492 513.600 128.532 513.696 ;
      RECT 0.492 516.000 128.532 516.096 ;
      RECT 0.492 518.400 128.532 518.496 ;
      RECT 0.492 520.800 128.532 520.896 ;
      RECT 0.492 523.200 128.532 523.296 ;
      RECT 0.492 525.600 128.532 525.696 ;
      RECT 0.492 528.000 128.532 528.096 ;
      RECT 0.492 530.400 128.532 530.496 ;
      RECT 0.492 532.800 128.532 532.896 ;
      RECT 0.492 535.200 128.532 535.296 ;
      RECT 0.492 537.600 128.532 537.696 ;
      RECT 0.492 540.000 128.532 540.096 ;
      RECT 0.492 542.400 128.532 542.496 ;
      RECT 0.492 544.800 128.532 544.896 ;
      RECT 0.492 547.200 128.532 547.296 ;
      RECT 0.492 549.600 128.532 549.696 ;
      RECT 0.492 552.000 128.532 552.096 ;
      RECT 0.492 554.400 128.532 554.496 ;
      RECT 0.492 556.800 128.532 556.896 ;
      RECT 0.492 559.200 128.532 559.296 ;
      RECT 0.492 561.600 128.532 561.696 ;
      RECT 0.492 564.000 128.532 564.096 ;
      RECT 0.492 566.400 128.532 566.496 ;
      RECT 0.492 568.800 128.532 568.896 ;
      RECT 0.492 571.200 128.532 571.296 ;
      RECT 0.492 573.600 128.532 573.696 ;
      RECT 0.492 576.000 128.532 576.096 ;
      RECT 0.492 578.400 128.532 578.496 ;
      RECT 0.492 580.800 128.532 580.896 ;
      RECT 0.492 583.200 128.532 583.296 ;
      RECT 0.492 585.600 128.532 585.696 ;
      RECT 0.492 588.000 128.532 588.096 ;
      RECT 0.492 590.400 128.532 590.496 ;
      RECT 0.492 592.800 128.532 592.896 ;
      RECT 0.492 595.200 128.532 595.296 ;
      RECT 0.492 597.600 128.532 597.696 ;
      RECT 0.492 600.000 128.532 600.096 ;
      RECT 0.492 602.400 128.532 602.496 ;
      RECT 0.492 604.800 128.532 604.896 ;
      RECT 0.492 607.200 128.532 607.296 ;
      RECT 0.492 609.600 128.532 609.696 ;
      RECT 0.492 612.000 128.532 612.096 ;
      RECT 0.492 614.400 128.532 614.496 ;
      RECT 0.492 616.800 128.532 616.896 ;
      RECT 0.492 619.200 128.532 619.296 ;
      RECT 0.492 621.600 128.532 621.696 ;
      RECT 0.492 624.000 128.532 624.096 ;
      RECT 0.492 626.400 128.532 626.496 ;
      RECT 0.492 628.800 128.532 628.896 ;
      RECT 0.492 631.200 128.532 631.296 ;
      RECT 0.492 633.600 128.532 633.696 ;
      RECT 0.492 636.000 128.532 636.096 ;
      RECT 0.492 638.400 128.532 638.496 ;
      RECT 0.492 640.800 128.532 640.896 ;
      RECT 0.492 643.200 128.532 643.296 ;
      RECT 0.492 645.600 128.532 645.696 ;
      RECT 0.492 648.000 128.532 648.096 ;
      RECT 0.492 650.400 128.532 650.496 ;
      RECT 0.492 652.800 128.532 652.896 ;
      RECT 0.492 655.200 128.532 655.296 ;
      RECT 0.492 657.600 128.532 657.696 ;
      RECT 0.492 660.000 128.532 660.096 ;
      RECT 0.492 662.400 128.532 662.496 ;
      RECT 0.492 664.800 128.532 664.896 ;
      RECT 0.492 667.200 128.532 667.296 ;
      RECT 0.492 669.600 128.532 669.696 ;
      RECT 0.492 672.000 128.532 672.096 ;
      RECT 0.492 674.400 128.532 674.496 ;
      RECT 0.492 676.800 128.532 676.896 ;
      RECT 0.492 679.200 128.532 679.296 ;
      RECT 0.492 681.600 128.532 681.696 ;
      RECT 0.492 684.000 128.532 684.096 ;
      RECT 0.492 686.400 128.532 686.496 ;
      RECT 0.492 688.800 128.532 688.896 ;
      RECT 0.492 691.200 128.532 691.296 ;
      RECT 0.492 693.600 128.532 693.696 ;
      RECT 0.492 696.000 128.532 696.096 ;
      RECT 0.492 698.400 128.532 698.496 ;
      RECT 0.492 700.800 128.532 700.896 ;
      RECT 0.492 703.200 128.532 703.296 ;
      RECT 0.492 705.600 128.532 705.696 ;
      RECT 0.492 708.000 128.532 708.096 ;
      RECT 0.492 710.400 128.532 710.496 ;
      RECT 0.492 712.800 128.532 712.896 ;
      RECT 0.492 715.200 128.532 715.296 ;
      RECT 0.492 717.600 128.532 717.696 ;
      RECT 0.492 720.000 128.532 720.096 ;
      RECT 0.492 722.400 128.532 722.496 ;
      RECT 0.492 724.800 128.532 724.896 ;
      RECT 0.492 727.200 128.532 727.296 ;
      RECT 0.492 729.600 128.532 729.696 ;
      RECT 0.492 732.000 128.532 732.096 ;
      RECT 0.492 734.400 128.532 734.496 ;
      RECT 0.492 736.800 128.532 736.896 ;
      RECT 0.492 739.200 128.532 739.296 ;
      RECT 0.492 741.600 128.532 741.696 ;
      RECT 0.492 744.000 128.532 744.096 ;
      RECT 0.492 746.400 128.532 746.496 ;
      RECT 0.492 748.800 128.532 748.896 ;
      RECT 0.492 751.200 128.532 751.296 ;
      RECT 0.492 753.600 128.532 753.696 ;
      RECT 0.492 756.000 128.532 756.096 ;
      RECT 0.492 758.400 128.532 758.496 ;
      RECT 0.492 760.800 128.532 760.896 ;
      RECT 0.492 763.200 128.532 763.296 ;
      RECT 0.492 765.600 128.532 765.696 ;
      RECT 0.492 768.000 128.532 768.096 ;
      RECT 0.492 770.400 128.532 770.496 ;
      RECT 0.492 772.800 128.532 772.896 ;
      RECT 0.492 775.200 128.532 775.296 ;
      RECT 0.492 777.600 128.532 777.696 ;
      RECT 0.492 780.000 128.532 780.096 ;
      RECT 0.492 782.400 128.532 782.496 ;
      RECT 0.492 784.800 128.532 784.896 ;
      RECT 0.492 787.200 128.532 787.296 ;
      RECT 0.492 789.600 128.532 789.696 ;
      RECT 0.492 792.000 128.532 792.096 ;
      RECT 0.492 794.400 128.532 794.496 ;
      RECT 0.492 796.800 128.532 796.896 ;
      RECT 0.492 799.200 128.532 799.296 ;
      RECT 0.492 801.600 128.532 801.696 ;
      RECT 0.492 804.000 128.532 804.096 ;
      RECT 0.492 806.400 128.532 806.496 ;
      RECT 0.492 808.800 128.532 808.896 ;
      RECT 0.492 811.200 128.532 811.296 ;
      RECT 0.492 813.600 128.532 813.696 ;
      RECT 0.492 816.000 128.532 816.096 ;
      RECT 0.492 818.400 128.532 818.496 ;
      RECT 0.492 820.800 128.532 820.896 ;
      RECT 0.492 823.200 128.532 823.296 ;
      RECT 0.492 825.600 128.532 825.696 ;
      RECT 0.492 828.000 128.532 828.096 ;
      RECT 0.492 830.400 128.532 830.496 ;
      RECT 0.492 832.800 128.532 832.896 ;
      RECT 0.492 835.200 128.532 835.296 ;
      RECT 0.492 837.600 128.532 837.696 ;
      RECT 0.492 840.000 128.532 840.096 ;
      RECT 0.492 842.400 128.532 842.496 ;
      RECT 0.492 844.800 128.532 844.896 ;
      RECT 0.492 847.200 128.532 847.296 ;
      RECT 0.492 849.600 128.532 849.696 ;
      RECT 0.492 852.000 128.532 852.096 ;
      RECT 0.492 854.400 128.532 854.496 ;
      RECT 0.492 856.800 128.532 856.896 ;
      RECT 0.492 859.200 128.532 859.296 ;
      RECT 0.492 861.600 128.532 861.696 ;
      RECT 0.492 864.000 128.532 864.096 ;
      RECT 0.492 866.400 128.532 866.496 ;
      RECT 0.492 868.800 128.532 868.896 ;
      RECT 0.492 871.200 128.532 871.296 ;
      RECT 0.492 873.600 128.532 873.696 ;
      RECT 0.492 876.000 128.532 876.096 ;
      RECT 0.492 878.400 128.532 878.496 ;
      RECT 0.492 880.800 128.532 880.896 ;
      RECT 0.492 883.200 128.532 883.296 ;
      RECT 0.492 885.600 128.532 885.696 ;
      RECT 0.492 888.000 128.532 888.096 ;
      RECT 0.492 890.400 128.532 890.496 ;
      RECT 0.492 892.800 128.532 892.896 ;
      RECT 0.492 895.200 128.532 895.296 ;
      RECT 0.492 897.600 128.532 897.696 ;
      RECT 0.492 900.000 128.532 900.096 ;
      RECT 0.492 902.400 128.532 902.496 ;
      RECT 0.492 904.800 128.532 904.896 ;
      RECT 0.492 907.200 128.532 907.296 ;
      RECT 0.492 909.600 128.532 909.696 ;
      RECT 0.492 912.000 128.532 912.096 ;
      RECT 0.492 914.400 128.532 914.496 ;
      RECT 0.492 916.800 128.532 916.896 ;
      RECT 0.492 919.200 128.532 919.296 ;
      RECT 0.492 921.600 128.532 921.696 ;
      RECT 0.492 924.000 128.532 924.096 ;
      RECT 0.492 926.400 128.532 926.496 ;
      RECT 0.492 928.800 128.532 928.896 ;
      RECT 0.492 931.200 128.532 931.296 ;
      RECT 0.492 933.600 128.532 933.696 ;
      RECT 0.492 936.000 128.532 936.096 ;
      RECT 0.492 938.400 128.532 938.496 ;
      RECT 0.492 940.800 128.532 940.896 ;
      RECT 0.492 943.200 128.532 943.296 ;
      RECT 0.492 945.600 128.532 945.696 ;
      RECT 0.492 948.000 128.532 948.096 ;
      RECT 0.492 950.400 128.532 950.496 ;
      RECT 0.492 952.800 128.532 952.896 ;
      RECT 0.492 955.200 128.532 955.296 ;
      RECT 0.492 957.600 128.532 957.696 ;
      RECT 0.492 960.000 128.532 960.096 ;
      RECT 0.492 962.400 128.532 962.496 ;
      RECT 0.492 964.800 128.532 964.896 ;
      RECT 0.492 967.200 128.532 967.296 ;
      RECT 0.492 969.600 128.532 969.696 ;
      RECT 0.492 972.000 128.532 972.096 ;
      RECT 0.492 974.400 128.532 974.496 ;
      RECT 0.492 976.800 128.532 976.896 ;
      RECT 0.492 979.200 128.532 979.296 ;
      RECT 0.492 981.600 128.532 981.696 ;
      RECT 0.492 984.000 128.532 984.096 ;
      RECT 0.492 986.400 128.532 986.496 ;
      RECT 0.492 988.800 128.532 988.896 ;
      RECT 0.492 991.200 128.532 991.296 ;
      RECT 0.492 993.600 128.532 993.696 ;
      RECT 0.492 996.000 128.532 996.096 ;
      RECT 0.492 998.400 128.532 998.496 ;
      RECT 0.492 1000.800 128.532 1000.896 ;
      RECT 0.492 1003.200 128.532 1003.296 ;
      RECT 0.492 1005.600 128.532 1005.696 ;
      RECT 0.492 1008.000 128.532 1008.096 ;
      RECT 0.492 1010.400 128.532 1010.496 ;
      RECT 0.492 1012.800 128.532 1012.896 ;
      RECT 0.492 1015.200 128.532 1015.296 ;
      RECT 0.492 1017.600 128.532 1017.696 ;
      RECT 0.492 1020.000 128.532 1020.096 ;
      RECT 0.492 1022.400 128.532 1022.496 ;
      RECT 0.492 1024.800 128.532 1024.896 ;
      RECT 0.492 1027.200 128.532 1027.296 ;
      RECT 0.492 1029.600 128.532 1029.696 ;
      RECT 0.492 1032.000 128.532 1032.096 ;
      RECT 0.492 1034.400 128.532 1034.496 ;
      RECT 0.492 1036.800 128.532 1036.896 ;
      RECT 0.492 1039.200 128.532 1039.296 ;
      RECT 0.492 1041.600 128.532 1041.696 ;
      RECT 0.492 1044.000 128.532 1044.096 ;
      RECT 0.492 1046.400 128.532 1046.496 ;
      RECT 0.492 1048.800 128.532 1048.896 ;
      RECT 0.492 1051.200 128.532 1051.296 ;
      RECT 0.492 1053.600 128.532 1053.696 ;
      RECT 0.492 1056.000 128.532 1056.096 ;
      RECT 0.492 1058.400 128.532 1058.496 ;
      RECT 0.492 1060.800 128.532 1060.896 ;
      RECT 0.492 1063.200 128.532 1063.296 ;
      RECT 0.492 1065.600 128.532 1065.696 ;
      RECT 0.492 1068.000 128.532 1068.096 ;
      RECT 0.492 1070.400 128.532 1070.496 ;
      RECT 0.492 1072.800 128.532 1072.896 ;
      RECT 0.492 1075.200 128.532 1075.296 ;
      RECT 0.492 1077.600 128.532 1077.696 ;
      RECT 0.492 1080.000 128.532 1080.096 ;
      RECT 0.492 1082.400 128.532 1082.496 ;
      RECT 0.492 1084.800 128.532 1084.896 ;
      RECT 0.492 1087.200 128.532 1087.296 ;
      RECT 0.492 1089.600 128.532 1089.696 ;
      RECT 0.492 1092.000 128.532 1092.096 ;
      RECT 0.492 1094.400 128.532 1094.496 ;
      RECT 0.492 1096.800 128.532 1096.896 ;
      RECT 0.492 1099.200 128.532 1099.296 ;
      RECT 0.492 1101.600 128.532 1101.696 ;
      RECT 0.492 1104.000 128.532 1104.096 ;
      RECT 0.492 1106.400 128.532 1106.496 ;
      RECT 0.492 1108.800 128.532 1108.896 ;
      RECT 0.492 1111.200 128.532 1111.296 ;
      RECT 0.492 1113.600 128.532 1113.696 ;
      RECT 0.492 1116.000 128.532 1116.096 ;
      RECT 0.492 1118.400 128.532 1118.496 ;
      RECT 0.492 1120.800 128.532 1120.896 ;
      RECT 0.492 1123.200 128.532 1123.296 ;
      RECT 0.492 1125.600 128.532 1125.696 ;
      RECT 0.492 1128.000 128.532 1128.096 ;
      RECT 0.492 1130.400 128.532 1130.496 ;
      RECT 0.492 1132.800 128.532 1132.896 ;
      RECT 0.492 1135.200 128.532 1135.296 ;
      RECT 0.492 1137.600 128.532 1137.696 ;
      RECT 0.492 1140.000 128.532 1140.096 ;
      RECT 0.492 1142.400 128.532 1142.496 ;
      RECT 0.492 1144.800 128.532 1144.896 ;
      RECT 0.492 1147.200 128.532 1147.296 ;
      RECT 0.492 1149.600 128.532 1149.696 ;
      RECT 0.492 1152.000 128.532 1152.096 ;
      RECT 0.492 1154.400 128.532 1154.496 ;
      RECT 0.492 1156.800 128.532 1156.896 ;
      RECT 0.492 1159.200 128.532 1159.296 ;
      RECT 0.492 1161.600 128.532 1161.696 ;
      RECT 0.492 1164.000 128.532 1164.096 ;
      RECT 0.492 1166.400 128.532 1166.496 ;
      RECT 0.492 1168.800 128.532 1168.896 ;
      RECT 0.492 1171.200 128.532 1171.296 ;
      RECT 0.492 1173.600 128.532 1173.696 ;
      RECT 0.492 1176.000 128.532 1176.096 ;
      RECT 0.492 1178.400 128.532 1178.496 ;
      RECT 0.492 1180.800 128.532 1180.896 ;
      RECT 0.492 1183.200 128.532 1183.296 ;
      RECT 0.492 1185.600 128.532 1185.696 ;
      RECT 0.492 1188.000 128.532 1188.096 ;
      RECT 0.492 1190.400 128.532 1190.496 ;
      RECT 0.492 1192.800 128.532 1192.896 ;
      RECT 0.492 1195.200 128.532 1195.296 ;
      RECT 0.492 1197.600 128.532 1197.696 ;
      RECT 0.492 1200.000 128.532 1200.096 ;
      RECT 0.492 1202.400 128.532 1202.496 ;
      RECT 0.492 1204.800 128.532 1204.896 ;
      RECT 0.492 1207.200 128.532 1207.296 ;
      RECT 0.492 1209.600 128.532 1209.696 ;
      RECT 0.492 1212.000 128.532 1212.096 ;
      RECT 0.492 1214.400 128.532 1214.496 ;
      RECT 0.492 1216.800 128.532 1216.896 ;
      RECT 0.492 1219.200 128.532 1219.296 ;
      RECT 0.492 1221.600 128.532 1221.696 ;
      RECT 0.492 1224.000 128.532 1224.096 ;
      RECT 0.492 1226.400 128.532 1226.496 ;
      RECT 0.492 1228.800 128.532 1228.896 ;
      RECT 0.492 1231.200 128.532 1231.296 ;
      RECT 0.492 1233.600 128.532 1233.696 ;
      RECT 0.492 1236.000 128.532 1236.096 ;
      RECT 0.492 1238.400 128.532 1238.496 ;
      RECT 0.492 1240.800 128.532 1240.896 ;
      RECT 0.492 1243.200 128.532 1243.296 ;
      RECT 0.492 1245.600 128.532 1245.696 ;
      RECT 0.492 1248.000 128.532 1248.096 ;
      RECT 0.492 1250.400 128.532 1250.496 ;
      RECT 0.492 1252.800 128.532 1252.896 ;
      RECT 0.492 1255.200 128.532 1255.296 ;
      RECT 0.492 1257.600 128.532 1257.696 ;
      RECT 0.492 1260.000 128.532 1260.096 ;
      RECT 0.492 1262.400 128.532 1262.496 ;
      RECT 0.492 1264.800 128.532 1264.896 ;
      RECT 0.492 1267.200 128.532 1267.296 ;
      RECT 0.492 1269.600 128.532 1269.696 ;
      RECT 0.492 1272.000 128.532 1272.096 ;
      RECT 0.492 1274.400 128.532 1274.496 ;
      RECT 0.492 1276.800 128.532 1276.896 ;
      RECT 0.492 1279.200 128.532 1279.296 ;
      RECT 0.492 1281.600 128.532 1281.696 ;
      RECT 0.492 1284.000 128.532 1284.096 ;
      RECT 0.492 1286.400 128.532 1286.496 ;
      RECT 0.492 1288.800 128.532 1288.896 ;
      RECT 0.492 1291.200 128.532 1291.296 ;
      RECT 0.492 1293.600 128.532 1293.696 ;
      RECT 0.492 1296.000 128.532 1296.096 ;
      RECT 0.492 1298.400 128.532 1298.496 ;
      RECT 0.492 1300.800 128.532 1300.896 ;
      RECT 0.492 1303.200 128.532 1303.296 ;
      RECT 0.492 1305.600 128.532 1305.696 ;
      RECT 0.492 1308.000 128.532 1308.096 ;
      RECT 0.492 1310.400 128.532 1310.496 ;
      RECT 0.492 1312.800 128.532 1312.896 ;
      RECT 0.492 1315.200 128.532 1315.296 ;
      RECT 0.492 1317.600 128.532 1317.696 ;
      RECT 0.492 1320.000 128.532 1320.096 ;
      RECT 0.492 1322.400 128.532 1322.496 ;
      RECT 0.492 1324.800 128.532 1324.896 ;
      RECT 0.492 1327.200 128.532 1327.296 ;
      RECT 0.492 1329.600 128.532 1329.696 ;
      RECT 0.492 1332.000 128.532 1332.096 ;
      RECT 0.492 1334.400 128.532 1334.496 ;
      RECT 0.492 1336.800 128.532 1336.896 ;
      RECT 0.492 1339.200 128.532 1339.296 ;
      RECT 0.492 1341.600 128.532 1341.696 ;
      RECT 0.492 1344.000 128.532 1344.096 ;
      RECT 0.492 1346.400 128.532 1346.496 ;
      RECT 0.492 1348.800 128.532 1348.896 ;
      RECT 0.492 1351.200 128.532 1351.296 ;
      RECT 0.492 1353.600 128.532 1353.696 ;
      RECT 0.492 1356.000 128.532 1356.096 ;
      RECT 0.492 1358.400 128.532 1358.496 ;
      RECT 0.492 1360.800 128.532 1360.896 ;
      RECT 0.492 1363.200 128.532 1363.296 ;
      RECT 0.492 1365.600 128.532 1365.696 ;
      RECT 0.492 1368.000 128.532 1368.096 ;
      RECT 0.492 1370.400 128.532 1370.496 ;
      RECT 0.492 1372.800 128.532 1372.896 ;
      RECT 0.492 1375.200 128.532 1375.296 ;
      RECT 0.492 1377.600 128.532 1377.696 ;
      RECT 0.492 1380.000 128.532 1380.096 ;
      RECT 0.492 1382.400 128.532 1382.496 ;
      RECT 0.492 1384.800 128.532 1384.896 ;
      RECT 0.492 1387.200 128.532 1387.296 ;
      RECT 0.492 1389.600 128.532 1389.696 ;
      RECT 0.492 1392.000 128.532 1392.096 ;
      RECT 0.492 1394.400 128.532 1394.496 ;
      RECT 0.492 1396.800 128.532 1396.896 ;
      RECT 0.492 1399.200 128.532 1399.296 ;
      RECT 0.492 1401.600 128.532 1401.696 ;
      RECT 0.492 1404.000 128.532 1404.096 ;
      RECT 0.492 1406.400 128.532 1406.496 ;
      RECT 0.492 1408.800 128.532 1408.896 ;
      RECT 0.492 1411.200 128.532 1411.296 ;
      RECT 0.492 1413.600 128.532 1413.696 ;
      RECT 0.492 1416.000 128.532 1416.096 ;
      RECT 0.492 1418.400 128.532 1418.496 ;
      RECT 0.492 1420.800 128.532 1420.896 ;
      RECT 0.492 1423.200 128.532 1423.296 ;
      RECT 0.492 1425.600 128.532 1425.696 ;
      RECT 0.492 1428.000 128.532 1428.096 ;
      RECT 0.492 1430.400 128.532 1430.496 ;
      RECT 0.492 1432.800 128.532 1432.896 ;
      RECT 0.492 1435.200 128.532 1435.296 ;
      RECT 0.492 1437.600 128.532 1437.696 ;
      RECT 0.492 1440.000 128.532 1440.096 ;
      RECT 0.492 1442.400 128.532 1442.496 ;
      RECT 0.492 1444.800 128.532 1444.896 ;
      RECT 0.492 1447.200 128.532 1447.296 ;
      RECT 0.492 1449.600 128.532 1449.696 ;
      RECT 0.492 1452.000 128.532 1452.096 ;
      RECT 0.492 1454.400 128.532 1454.496 ;
      RECT 0.492 1456.800 128.532 1456.896 ;
      RECT 0.492 1459.200 128.532 1459.296 ;
      RECT 0.492 1461.600 128.532 1461.696 ;
      RECT 0.492 1464.000 128.532 1464.096 ;
      RECT 0.492 1466.400 128.532 1466.496 ;
      RECT 0.492 1468.800 128.532 1468.896 ;
      RECT 0.492 1471.200 128.532 1471.296 ;
      RECT 0.492 1473.600 128.532 1473.696 ;
      RECT 0.492 1476.000 128.532 1476.096 ;
      RECT 0.492 1478.400 128.532 1478.496 ;
      RECT 0.492 1480.800 128.532 1480.896 ;
      RECT 0.492 1483.200 128.532 1483.296 ;
      RECT 0.492 1485.600 128.532 1485.696 ;
      RECT 0.492 1488.000 128.532 1488.096 ;
      RECT 0.492 1490.400 128.532 1490.496 ;
      RECT 0.492 1492.800 128.532 1492.896 ;
      RECT 0.492 1495.200 128.532 1495.296 ;
      RECT 0.492 1497.600 128.532 1497.696 ;
      RECT 0.492 1500.000 128.532 1500.096 ;
      RECT 0.492 1502.400 128.532 1502.496 ;
      RECT 0.492 1504.800 128.532 1504.896 ;
      RECT 0.492 1507.200 128.532 1507.296 ;
      RECT 0.492 1509.600 128.532 1509.696 ;
      RECT 0.492 1512.000 128.532 1512.096 ;
      RECT 0.492 1514.400 128.532 1514.496 ;
      RECT 0.492 1516.800 128.532 1516.896 ;
      RECT 0.492 1519.200 128.532 1519.296 ;
      RECT 0.492 1521.600 128.532 1521.696 ;
      RECT 0.492 1524.000 128.532 1524.096 ;
      RECT 0.492 1526.400 128.532 1526.496 ;
      RECT 0.492 1528.800 128.532 1528.896 ;
      RECT 0.492 1531.200 128.532 1531.296 ;
      RECT 0.492 1533.600 128.532 1533.696 ;
      RECT 0.492 1536.000 128.532 1536.096 ;
      RECT 0.492 1538.400 128.532 1538.496 ;
      RECT 0.492 1540.800 128.532 1540.896 ;
      RECT 0.492 1543.200 128.532 1543.296 ;
      RECT 0.492 1545.600 128.532 1545.696 ;
      RECT 0.492 1548.000 128.532 1548.096 ;
      RECT 0.492 1550.400 128.532 1550.496 ;
      RECT 0.492 1552.800 128.532 1552.896 ;
      RECT 0.492 1555.200 128.532 1555.296 ;
      RECT 0.492 1557.600 128.532 1557.696 ;
      RECT 0.492 1560.000 128.532 1560.096 ;
      RECT 0.492 1562.400 128.532 1562.496 ;
      RECT 0.492 1564.800 128.532 1564.896 ;
      RECT 0.492 1567.200 128.532 1567.296 ;
      RECT 0.492 1569.600 128.532 1569.696 ;
      RECT 0.492 1572.000 128.532 1572.096 ;
      RECT 0.492 1574.400 128.532 1574.496 ;
      RECT 0.492 1576.800 128.532 1576.896 ;
      RECT 0.492 1579.200 128.532 1579.296 ;
      RECT 0.492 1581.600 128.532 1581.696 ;
      RECT 0.492 1584.000 128.532 1584.096 ;
      RECT 0.492 1586.400 128.532 1586.496 ;
      RECT 0.492 1588.800 128.532 1588.896 ;
      RECT 0.492 1591.200 128.532 1591.296 ;
      RECT 0.492 1593.600 128.532 1593.696 ;
      RECT 0.492 1596.000 128.532 1596.096 ;
      RECT 0.492 1598.400 128.532 1598.496 ;
      RECT 0.492 1600.800 128.532 1600.896 ;
      RECT 0.492 1603.200 128.532 1603.296 ;
      RECT 0.492 1605.600 128.532 1605.696 ;
      RECT 0.492 1608.000 128.532 1608.096 ;
      RECT 0.492 1610.400 128.532 1610.496 ;
      RECT 0.492 1612.800 128.532 1612.896 ;
      RECT 0.492 1615.200 128.532 1615.296 ;
      RECT 0.492 1617.600 128.532 1617.696 ;
      RECT 0.492 1620.000 128.532 1620.096 ;
      RECT 0.492 1622.400 128.532 1622.496 ;
      RECT 0.492 1624.800 128.532 1624.896 ;
      RECT 0.492 1627.200 128.532 1627.296 ;
      RECT 0.492 1629.600 128.532 1629.696 ;
      RECT 0.492 1632.000 128.532 1632.096 ;
      RECT 0.492 1634.400 128.532 1634.496 ;
      RECT 0.492 1636.800 128.532 1636.896 ;
      RECT 0.492 1639.200 128.532 1639.296 ;
      RECT 0.492 1641.600 128.532 1641.696 ;
      RECT 0.492 1644.000 128.532 1644.096 ;
      RECT 0.492 1646.400 128.532 1646.496 ;
      RECT 0.492 1648.800 128.532 1648.896 ;
      RECT 0.492 1651.200 128.532 1651.296 ;
      RECT 0.492 1653.600 128.532 1653.696 ;
      RECT 0.492 1656.000 128.532 1656.096 ;
      RECT 0.492 1658.400 128.532 1658.496 ;
      RECT 0.492 1660.800 128.532 1660.896 ;
      RECT 0.492 1663.200 128.532 1663.296 ;
      RECT 0.492 1665.600 128.532 1665.696 ;
      RECT 0.492 1668.000 128.532 1668.096 ;
      RECT 0.492 1670.400 128.532 1670.496 ;
      RECT 0.492 1672.800 128.532 1672.896 ;
      RECT 0.492 1675.200 128.532 1675.296 ;
      RECT 0.492 1677.600 128.532 1677.696 ;
      RECT 0.492 1680.000 128.532 1680.096 ;
      RECT 0.492 1682.400 128.532 1682.496 ;
      RECT 0.492 1684.800 128.532 1684.896 ;
      RECT 0.492 1687.200 128.532 1687.296 ;
      RECT 0.492 1689.600 128.532 1689.696 ;
      RECT 0.492 1692.000 128.532 1692.096 ;
      RECT 0.492 1694.400 128.532 1694.496 ;
      RECT 0.492 1696.800 128.532 1696.896 ;
      RECT 0.492 1699.200 128.532 1699.296 ;
      RECT 0.492 1701.600 128.532 1701.696 ;
      RECT 0.492 1704.000 128.532 1704.096 ;
      RECT 0.492 1706.400 128.532 1706.496 ;
      RECT 0.492 1708.800 128.532 1708.896 ;
      RECT 0.492 1711.200 128.532 1711.296 ;
      RECT 0.492 1713.600 128.532 1713.696 ;
      RECT 0.492 1716.000 128.532 1716.096 ;
      RECT 0.492 1718.400 128.532 1718.496 ;
      RECT 0.492 1720.800 128.532 1720.896 ;
      RECT 0.492 1723.200 128.532 1723.296 ;
      RECT 0.492 1725.600 128.532 1725.696 ;
      RECT 0.492 1728.000 128.532 1728.096 ;
      RECT 0.492 1730.400 128.532 1730.496 ;
      RECT 0.492 1732.800 128.532 1732.896 ;
      RECT 0.492 1735.200 128.532 1735.296 ;
      RECT 0.492 1737.600 128.532 1737.696 ;
      RECT 0.492 1740.000 128.532 1740.096 ;
      RECT 0.492 1742.400 128.532 1742.496 ;
      RECT 0.492 1744.800 128.532 1744.896 ;
      RECT 0.492 1747.200 128.532 1747.296 ;
      RECT 0.492 1749.600 128.532 1749.696 ;
      RECT 0.492 1752.000 128.532 1752.096 ;
      RECT 0.492 1754.400 128.532 1754.496 ;
      RECT 0.492 1756.800 128.532 1756.896 ;
      RECT 0.492 1759.200 128.532 1759.296 ;
      RECT 0.492 1761.600 128.532 1761.696 ;
      RECT 0.492 1764.000 128.532 1764.096 ;
      RECT 0.492 1766.400 128.532 1766.496 ;
      RECT 0.492 1768.800 128.532 1768.896 ;
      RECT 0.492 1771.200 128.532 1771.296 ;
      RECT 0.492 1773.600 128.532 1773.696 ;
      RECT 0.492 1776.000 128.532 1776.096 ;
      RECT 0.492 1778.400 128.532 1778.496 ;
      RECT 0.492 1780.800 128.532 1780.896 ;
      RECT 0.492 1783.200 128.532 1783.296 ;
      RECT 0.492 1785.600 128.532 1785.696 ;
      RECT 0.492 1788.000 128.532 1788.096 ;
      RECT 0.492 1790.400 128.532 1790.496 ;
      RECT 0.492 1792.800 128.532 1792.896 ;
      RECT 0.492 1795.200 128.532 1795.296 ;
      RECT 0.492 1797.600 128.532 1797.696 ;
      RECT 0.492 1800.000 128.532 1800.096 ;
      RECT 0.492 1802.400 128.532 1802.496 ;
      RECT 0.492 1804.800 128.532 1804.896 ;
      RECT 0.492 1807.200 128.532 1807.296 ;
      RECT 0.492 1809.600 128.532 1809.696 ;
      RECT 0.492 1812.000 128.532 1812.096 ;
      RECT 0.492 1814.400 128.532 1814.496 ;
      RECT 0.492 1816.800 128.532 1816.896 ;
      RECT 0.492 1819.200 128.532 1819.296 ;
      RECT 0.492 1821.600 128.532 1821.696 ;
      RECT 0.492 1824.000 128.532 1824.096 ;
      RECT 0.492 1826.400 128.532 1826.496 ;
      RECT 0.492 1828.800 128.532 1828.896 ;
      RECT 0.492 1831.200 128.532 1831.296 ;
      RECT 0.492 1833.600 128.532 1833.696 ;
      RECT 0.492 1836.000 128.532 1836.096 ;
      RECT 0.492 1838.400 128.532 1838.496 ;
      RECT 0.492 1840.800 128.532 1840.896 ;
      RECT 0.492 1843.200 128.532 1843.296 ;
      RECT 0.492 1845.600 128.532 1845.696 ;
      RECT 0.492 1848.000 128.532 1848.096 ;
      RECT 0.492 1850.400 128.532 1850.496 ;
      RECT 0.492 1852.800 128.532 1852.896 ;
      RECT 0.492 1855.200 128.532 1855.296 ;
      RECT 0.492 1857.600 128.532 1857.696 ;
      RECT 0.492 1860.000 128.532 1860.096 ;
      RECT 0.492 1862.400 128.532 1862.496 ;
      RECT 0.492 1864.800 128.532 1864.896 ;
      RECT 0.492 1867.200 128.532 1867.296 ;
      RECT 0.492 1869.600 128.532 1869.696 ;
      RECT 0.492 1872.000 128.532 1872.096 ;
      RECT 0.492 1874.400 128.532 1874.496 ;
      RECT 0.492 1876.800 128.532 1876.896 ;
      RECT 0.492 1879.200 128.532 1879.296 ;
      RECT 0.492 1881.600 128.532 1881.696 ;
      RECT 0.492 1884.000 128.532 1884.096 ;
      RECT 0.492 1886.400 128.532 1886.496 ;
      RECT 0.492 1888.800 128.532 1888.896 ;
      RECT 0.492 1891.200 128.532 1891.296 ;
      RECT 0.492 1893.600 128.532 1893.696 ;
      RECT 0.492 1896.000 128.532 1896.096 ;
      RECT 0.492 1898.400 128.532 1898.496 ;
      RECT 0.492 1900.800 128.532 1900.896 ;
      RECT 0.492 1903.200 128.532 1903.296 ;
      RECT 0.492 1905.600 128.532 1905.696 ;
      RECT 0.492 1908.000 128.532 1908.096 ;
      RECT 0.492 1910.400 128.532 1910.496 ;
      RECT 0.492 1912.800 128.532 1912.896 ;
      RECT 0.492 1915.200 128.532 1915.296 ;
      RECT 0.492 1917.600 128.532 1917.696 ;
      RECT 0.492 1920.000 128.532 1920.096 ;
      RECT 0.492 1922.400 128.532 1922.496 ;
      RECT 0.492 1924.800 128.532 1924.896 ;
      RECT 0.492 1927.200 128.532 1927.296 ;
      RECT 0.492 1929.600 128.532 1929.696 ;
      RECT 0.492 1932.000 128.532 1932.096 ;
      RECT 0.492 1934.400 128.532 1934.496 ;
      RECT 0.492 1936.800 128.532 1936.896 ;
      RECT 0.492 1939.200 128.532 1939.296 ;
      RECT 0.492 1941.600 128.532 1941.696 ;
      RECT 0.492 1944.000 128.532 1944.096 ;
      RECT 0.492 1946.400 128.532 1946.496 ;
      RECT 0.492 1948.800 128.532 1948.896 ;
      RECT 0.492 1951.200 128.532 1951.296 ;
      RECT 0.492 1953.600 128.532 1953.696 ;
      RECT 0.492 1956.000 128.532 1956.096 ;
      RECT 0.492 1958.400 128.532 1958.496 ;
      RECT 0.492 1960.800 128.532 1960.896 ;
      RECT 0.492 1963.200 128.532 1963.296 ;
      RECT 0.492 1965.600 128.532 1965.696 ;
      RECT 0.492 1968.000 128.532 1968.096 ;
      RECT 0.492 1970.400 128.532 1970.496 ;
      RECT 0.492 1972.800 128.532 1972.896 ;
      RECT 0.492 1975.200 128.532 1975.296 ;
      RECT 0.492 1977.600 128.532 1977.696 ;
      RECT 0.492 1980.000 128.532 1980.096 ;
      RECT 0.492 1982.400 128.532 1982.496 ;
      RECT 0.492 1984.800 128.532 1984.896 ;
      RECT 0.492 1987.200 128.532 1987.296 ;
      RECT 0.492 1989.600 128.532 1989.696 ;
      RECT 0.492 1992.000 128.532 1992.096 ;
      RECT 0.492 1994.400 128.532 1994.496 ;
      RECT 0.492 1996.800 128.532 1996.896 ;
      RECT 0.492 1999.200 128.532 1999.296 ;
      RECT 0.492 2001.600 128.532 2001.696 ;
      RECT 0.492 2004.000 128.532 2004.096 ;
      RECT 0.492 2006.400 128.532 2006.496 ;
      RECT 0.492 2008.800 128.532 2008.896 ;
      RECT 0.492 2011.200 128.532 2011.296 ;
      RECT 0.492 2013.600 128.532 2013.696 ;
      RECT 0.492 2016.000 128.532 2016.096 ;
      RECT 0.492 2018.400 128.532 2018.496 ;
      RECT 0.492 2020.800 128.532 2020.896 ;
      RECT 0.492 2023.200 128.532 2023.296 ;
      RECT 0.492 2025.600 128.532 2025.696 ;
      RECT 0.492 2028.000 128.532 2028.096 ;
      RECT 0.492 2030.400 128.532 2030.496 ;
      RECT 0.492 2032.800 128.532 2032.896 ;
      RECT 0.492 2035.200 128.532 2035.296 ;
      RECT 0.492 2037.600 128.532 2037.696 ;
      RECT 0.492 2040.000 128.532 2040.096 ;
      RECT 0.492 2042.400 128.532 2042.496 ;
      RECT 0.492 2044.800 128.532 2044.896 ;
      RECT 0.492 2047.200 128.532 2047.296 ;
      RECT 0.492 2049.600 128.532 2049.696 ;
      RECT 0.492 2052.000 128.532 2052.096 ;
      RECT 0.492 2054.400 128.532 2054.496 ;
      RECT 0.492 2056.800 128.532 2056.896 ;
      RECT 0.492 2059.200 128.532 2059.296 ;
      RECT 0.492 2061.600 128.532 2061.696 ;
      RECT 0.492 2064.000 128.532 2064.096 ;
      RECT 0.492 2066.400 128.532 2066.496 ;
      RECT 0.492 2068.800 128.532 2068.896 ;
      RECT 0.492 2071.200 128.532 2071.296 ;
      RECT 0.492 2073.600 128.532 2073.696 ;
      RECT 0.492 2076.000 128.532 2076.096 ;
      RECT 0.492 2078.400 128.532 2078.496 ;
      RECT 0.492 2080.800 128.532 2080.896 ;
      RECT 0.492 2083.200 128.532 2083.296 ;
      RECT 0.492 2085.600 128.532 2085.696 ;
      RECT 0.492 2088.000 128.532 2088.096 ;
      RECT 0.492 2090.400 128.532 2090.496 ;
      RECT 0.492 2092.800 128.532 2092.896 ;
      RECT 0.492 2095.200 128.532 2095.296 ;
      RECT 0.492 2097.600 128.532 2097.696 ;
      RECT 0.492 2100.000 128.532 2100.096 ;
      RECT 0.492 2102.400 128.532 2102.496 ;
      RECT 0.492 2104.800 128.532 2104.896 ;
      RECT 0.492 2107.200 128.532 2107.296 ;
      RECT 0.492 2109.600 128.532 2109.696 ;
      RECT 0.492 2112.000 128.532 2112.096 ;
      RECT 0.492 2114.400 128.532 2114.496 ;
      RECT 0.492 2116.800 128.532 2116.896 ;
      RECT 0.492 2119.200 128.532 2119.296 ;
      RECT 0.492 2121.600 128.532 2121.696 ;
      RECT 0.492 2124.000 128.532 2124.096 ;
      RECT 0.492 2126.400 128.532 2126.496 ;
      RECT 0.492 2128.800 128.532 2128.896 ;
      RECT 0.492 2131.200 128.532 2131.296 ;
      RECT 0.492 2133.600 128.532 2133.696 ;
      RECT 0.492 2136.000 128.532 2136.096 ;
      RECT 0.492 2138.400 128.532 2138.496 ;
      RECT 0.492 2140.800 128.532 2140.896 ;
      RECT 0.492 2143.200 128.532 2143.296 ;
      RECT 0.492 2145.600 128.532 2145.696 ;
      RECT 0.492 2148.000 128.532 2148.096 ;
      RECT 0.492 2150.400 128.532 2150.496 ;
      RECT 0.492 2152.800 128.532 2152.896 ;
      RECT 0.492 2155.200 128.532 2155.296 ;
      RECT 0.492 2157.600 128.532 2157.696 ;
      RECT 0.492 2160.000 128.532 2160.096 ;
      RECT 0.492 2162.400 128.532 2162.496 ;
      RECT 0.492 2164.800 128.532 2164.896 ;
      RECT 0.492 2167.200 128.532 2167.296 ;
      RECT 0.492 2169.600 128.532 2169.696 ;
      RECT 0.492 2172.000 128.532 2172.096 ;
      RECT 0.492 2174.400 128.532 2174.496 ;
      RECT 0.492 2176.800 128.532 2176.896 ;
      RECT 0.492 2179.200 128.532 2179.296 ;
      RECT 0.492 2181.600 128.532 2181.696 ;
      RECT 0.492 2184.000 128.532 2184.096 ;
      RECT 0.492 2186.400 128.532 2186.496 ;
      RECT 0.492 2188.800 128.532 2188.896 ;
      RECT 0.492 2191.200 128.532 2191.296 ;
      RECT 0.492 2193.600 128.532 2193.696 ;
      RECT 0.492 2196.000 128.532 2196.096 ;
      RECT 0.492 2198.400 128.532 2198.496 ;
      RECT 0.492 2200.800 128.532 2200.896 ;
      RECT 0.492 2203.200 128.532 2203.296 ;
      RECT 0.492 2205.600 128.532 2205.696 ;
      RECT 0.492 2208.000 128.532 2208.096 ;
      RECT 0.492 2210.400 128.532 2210.496 ;
      RECT 0.492 2212.800 128.532 2212.896 ;
      RECT 0.492 2215.200 128.532 2215.296 ;
      RECT 0.492 2217.600 128.532 2217.696 ;
      RECT 0.492 2220.000 128.532 2220.096 ;
      RECT 0.492 2222.400 128.532 2222.496 ;
      RECT 0.492 2224.800 128.532 2224.896 ;
      RECT 0.492 2227.200 128.532 2227.296 ;
      RECT 0.492 2229.600 128.532 2229.696 ;
      RECT 0.492 2232.000 128.532 2232.096 ;
      RECT 0.492 2234.400 128.532 2234.496 ;
      RECT 0.492 2236.800 128.532 2236.896 ;
      RECT 0.492 2239.200 128.532 2239.296 ;
      RECT 0.492 2241.600 128.532 2241.696 ;
      RECT 0.492 2244.000 128.532 2244.096 ;
      RECT 0.492 2246.400 128.532 2246.496 ;
      RECT 0.492 2248.800 128.532 2248.896 ;
    END
  END VDD
  OBS
    LAYER M1 ;
    RECT 0 0 129.024 2250.216 ;
    LAYER M2 ;
    RECT 0 0 129.024 2250.216 ;
    LAYER M3 ;
    RECT 0 0 129.024 2250.216 ;
    LAYER M4 ;
    RECT 0 0 129.024 2250.216 ;
  END
END ot_s81_pma_rxm

END LIBRARY
